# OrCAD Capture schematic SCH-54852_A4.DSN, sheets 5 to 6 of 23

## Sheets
5 C-20 REMOTE DEBUG: size D
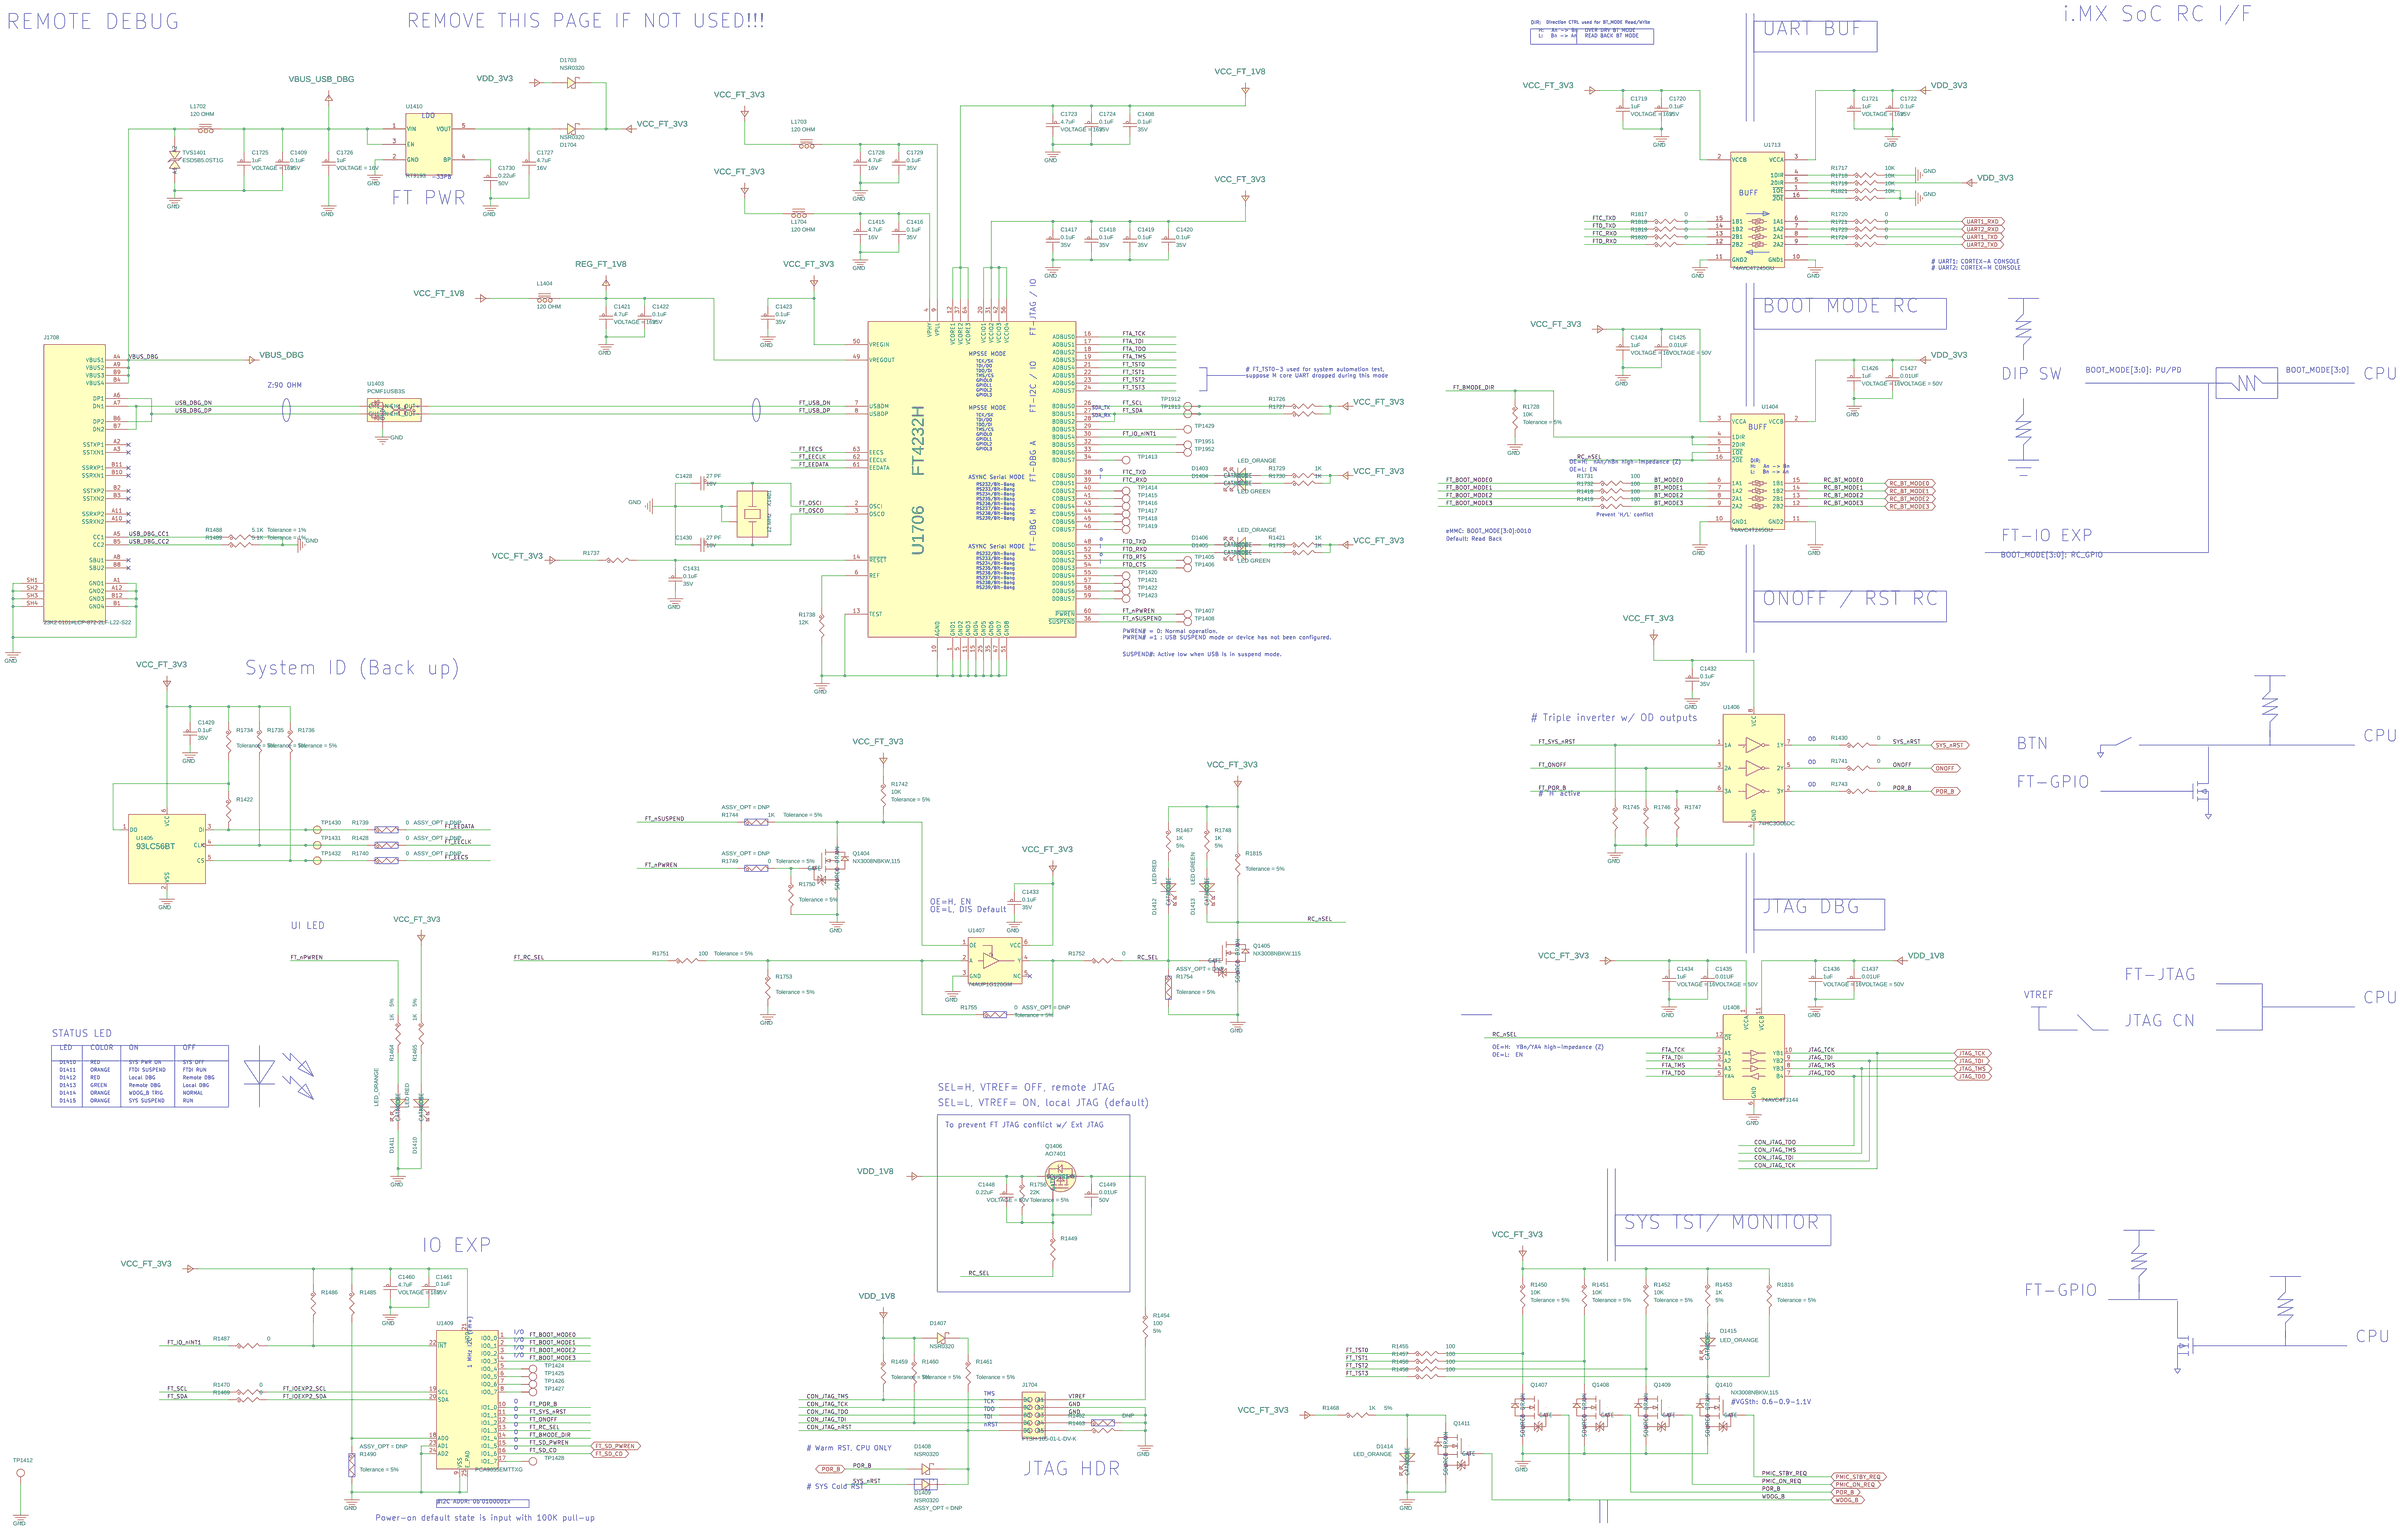
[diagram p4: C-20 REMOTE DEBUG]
6 C-18 CODEC: size C

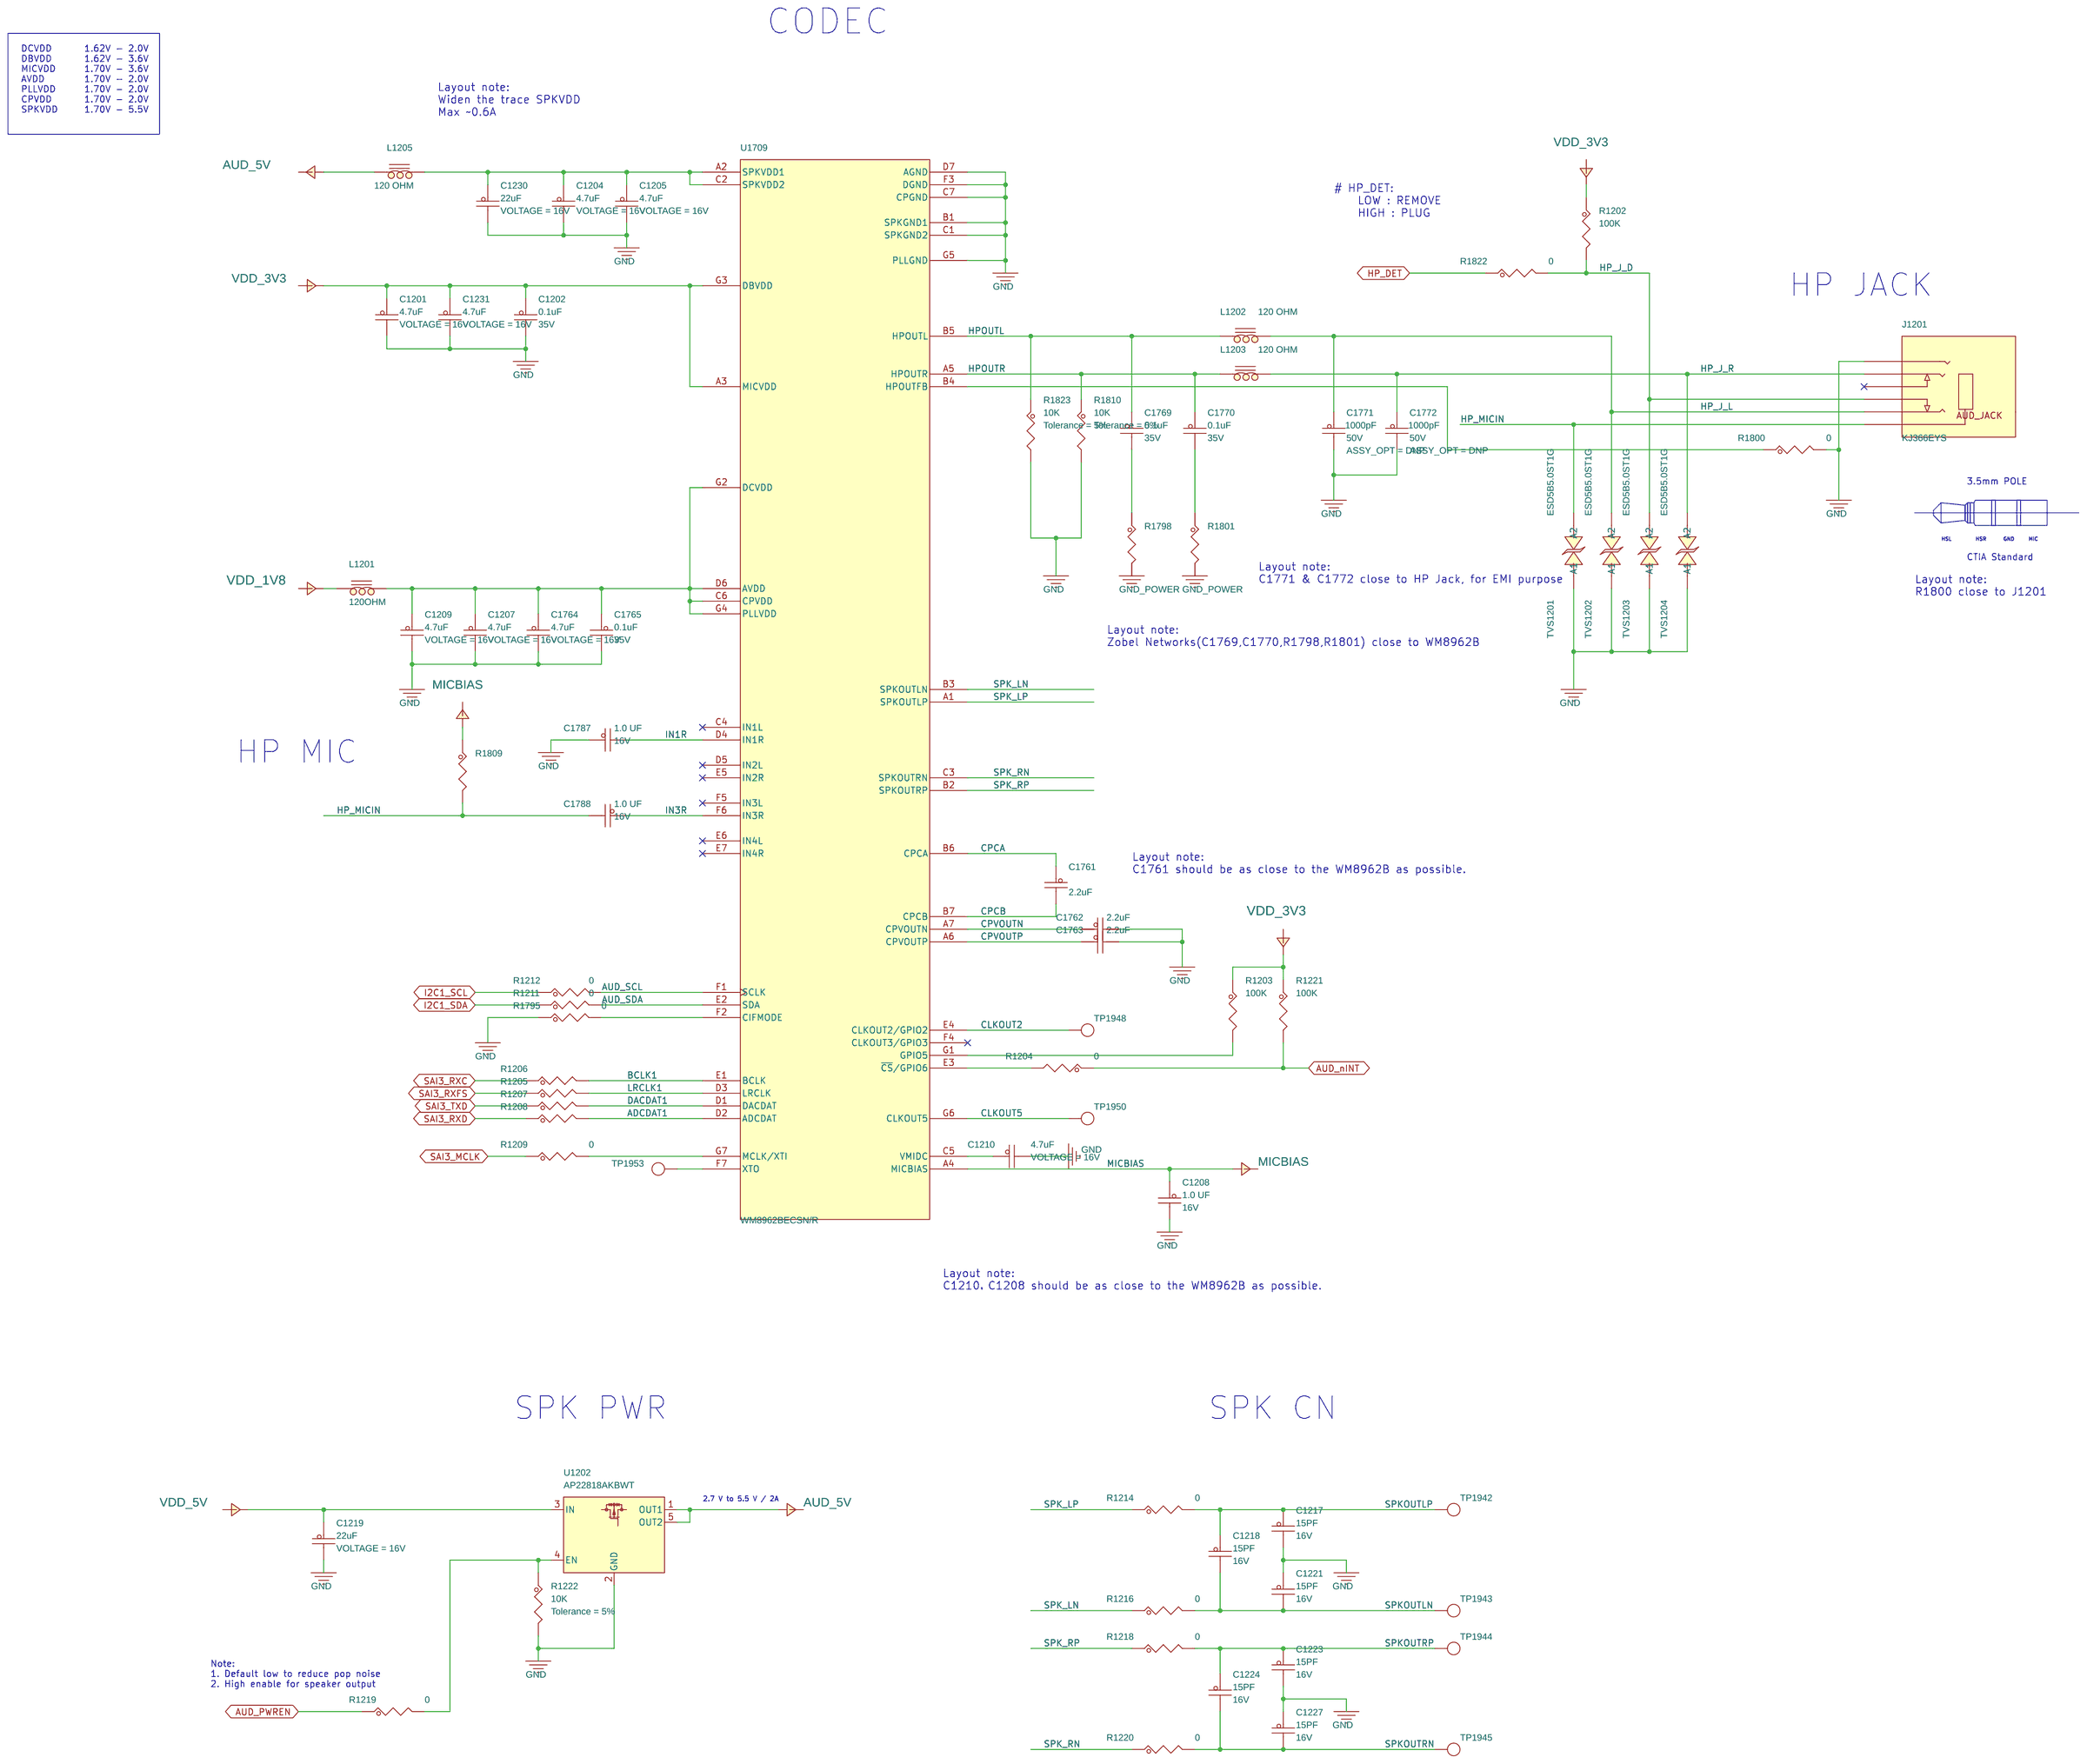
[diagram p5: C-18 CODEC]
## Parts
sheet C-18 CODEC
C1201  4.7uF  [CC0603_OV]
C1202  0.1uF  [CC0402_25]
C1204  4.7uF  [CC0603_OV]
C1205  4.7uF  [CC0603_OV]
C1207  4.7uF  [CC0603_OV]
C1208  1.0 UF  [0603_CC]
C1209  4.7uF  [CC0603_OV]
C1210  4.7uF  [CC0603_OV]
C1217  15PF  [0402_CC]
C1218  15PF  [0402_CC]
C1219  22uF  [CC0805_OV]
C1221  15PF  [0402_CC]
C1223  15PF  [0402_CC]
C1224  15PF  [0402_CC]
C1227  15PF  [0402_CC]
C1230  22uF  [CC0805_OV]
C1231  4.7uF  [CC0603_OV]
C1761  2.2uF  [CC0603_OV]
C1762  2.2uF  [CC0603_OV]
C1763  2.2uF  [CC0603_OV]
C1764  4.7uF  [CC0603_OV]
C1765  0.1uF  [CC0402_25]
C1769  0.1uF  [CC0402_25]
C1770  0.1uF  [CC0402_25]
C1771  1000pF  [0402_CC]
C1772  1000pF  [0402_CC]
C1787  1.0 UF  [0603_CC]
C1788  1.0 UF  [0603_CC]
J1201  KJ366EYS  [con6_audiojack_ra_th]
L1201  120OHM  [0603_CC]
L1202  120 OHM  [IND_0603]
L1203  120 OHM  [IND_0603]
L1205  120 OHM  [IND_0603]
R1202  100K  [0402_CC]
R1203  100K  [0402_CC]
R1204  0  [0402_CC]
R1205  0  [0402_CC]
R1206  0  [0402_CC]
R1207  0  [0402_CC]
R1208  0  [0402_CC]
R1209  0  [0402_CC]
R1211  0  [0402_CC]
R1212  0  [0402_CC]
R1214  0  [0402_CC]
R1216  0  [0402_CC]
R1218  0  [0402_CC]
R1219  0  [0402_CC]
R1220  0  [0402_CC]
R1221  100K  [0402_CC]
R1222  10K  [0402_CC]
R1795  0  [0402_CC]
R1798  20  [0603_CC]
R1800  0  [0402_CC]
R1801  20  [0603_CC]
R1809  2.20K  [0603_CC]
R1810  10K  [0402_CC]
R1822  0  [0402_CC]
R1823  10K  [0402_CC]
TP1942  TPAD_050  [TPAD_050]
TP1943  TPAD_050  [TPAD_050]
TP1944  TPAD_050  [TPAD_050]
TP1945  TPAD_050  [TPAD_050]
TP1948  TPAD_020  [tpad_020]
TP1950  TPAD_020  [tpad_020]
TP1953  TPAD_020  [tpad_020]
TVS1201  ESD5B5.0ST1G  [diode2_sod523]
TVS1202  ESD5B5.0ST1G  [diode2_sod523]
TVS1203  ESD5B5.0ST1G  [diode2_sod523]
TVS1204  ESD5B5.0ST1G  [diode2_sod523]
U1202  AP22818AKBWT  [sot23-5]
U1709  WM8962BECSN/R  [BGA49_0P5_3P62X4]
sheet C-20 REMOTE DEBUG
C1408  0.1uF  [CC0402_25]
C1409  0.1uF  [CC0402_25]
C1415  4.7uF  [CC0603_OV]
C1416  0.1uF  [CC0402_25]
C1417  0.1uF  [CC0402_25]
C1418  0.1uF  [CC0402_25]
C1419  0.1uF  [CC0402_25]
C1420  0.1uF  [CC0402_25]
C1421  4.7uF  [CC0603_OV]
C1422  0.1uF  [CC0402_25]
C1423  0.1uF  [CC0402_25]
C1424  1uF  [CC0402_25]
C1425  0.01UF  [0402_CC]
C1426  1uF  [CC0402_25]
C1427  0.01UF  [0402_CC]
C1428  27 PF  [0402_CC]
C1429  0.1uF  [CC0402_25]
C1430  27 PF  [0402_CC]
C1431  0.1uF  [CC0402_25]
C1432  0.1uF  [CC0402_25]
C1433  0.1uF  [CC0402_25]
C1434  1uF  [CC0402_25]
C1435  0.01UF  [0402_CC]
C1436  1uF  [CC0402_25]
C1437  0.01UF  [0402_CC]
C1448  0.22uF  [0402_CC]
C1449  0.01UF  [0402_CC]
C1460  4.7uF  [CC0603_OV]
C1461  0.1uF  [CC0402_25]
C1719  1uF  [CC0402_25]
C1720  0.1uF  [CC0402_25]
C1721  1uF  [CC0402_25]
C1722  0.1uF  [CC0402_25]
C1723  4.7uF  [CC0603_OV]
C1724  0.1uF  [CC0402_25]
C1725  1uF  [CC0402_25]
C1726  1uF  [CC0402_25]
C1727  4.7uF  [CC0603_OV]
C1728  4.7uF  [CC0603_OV]
C1729  0.1uF  [CC0402_25]
C1730  0.22uF  [0402_CC]
D1403  LED_ORANGE  [led_0603_11mil]
D1404  LED GREEN  [LED_0603]
D1405  LED GREEN  [LED_0603]
D1406  LED_ORANGE  [led_0603_11mil]
D1407  NSR0320  [SOD323]
D1408  NSR0320  [SOD323]
D1409  NSR0320  [SOD323]
D1410  LED RED  [LED_0603]
D1411  LED_ORANGE  [led_0603_11mil]
D1412  LED RED  [LED_0603]
D1413  LED GREEN  [LED_0603]
D1414  LED_ORANGE  [led_0603_11mil]
D1415  LED_ORANGE  [led_0603_11mil]
D1703  NSR0320  [SOD323]
D1704  NSR0320  [SOD323]
J1704  FTSH-105-01-L-DV-K  [hdr205_10m_50_sm_k]
J1708  23K2 0101#LCP-872-2LF-L22-S22  [con24_usb_typec_ra_smt_th_2p2l]
L1404  120 OHM  [IND_0603]
L1702  120 OHM  [IND_0603]
L1703  120 OHM  [IND_0603]
L1704  120 OHM  [IND_0603]
Q1404  NX3008NBKW,115  [sc70_3]
Q1405  NX3008NBKW,115  [sc70_3]
Q1406  AO7401  [sc70_3]
Q1407  NX3008NBKW,115  [sc70_3]
Q1408  NX3008NBKW,115  [sc70_3]
Q1409  NX3008NBKW,115  [sc70_3]
Q1410  NX3008NBKW,115  [sc70_3]
Q1411  NX3008NBKW,115  [sc70_3]
R1418  100  [RC0402_25]
R1419  100  [RC0402_25]
R1421  1K  [0402_CC]
R1422  2.2K  [0402_CC]
R1428  0  [0402_CC]
R1430  0  [0402_CC]
R1449  0  [0402_CC]
R1450  10K  [0402_CC]
R1451  10K  [0402_CC]
R1452  10K  [0402_CC]
R1453  1K  [0402_CC]
R1454  100  [RC0402_25]
R1455  100  [RC0402_25]
R1456  100  [RC0402_25]
R1457  100  [RC0402_25]
R1458  100  [RC0402_25]
R1459  10K  [0402_CC]
R1460  10K  [0402_CC]
R1461  10K  [0402_CC]
R1462  0  [0402_CC]
R1463  0  [0402_CC]
R1464  1K  [0402_CC]
R1465  1K  [0402_CC]
R1467  1K  [0402_CC]
R1468  1K  [0402_CC]
R1469  0  [0402_CC]
R1470  0  [0402_CC]
R1485  10K  [0402_CC]
R1486  10K  [0402_CC]
R1487  0  [0402_CC]
R1488  5.1K  [RC0402_25]
R1489  5.1K  [RC0402_25]
R1490  10K  [0402_CC]
R1717  10K  [0402_CC]
R1718  10K  [0402_CC]
R1719  10K  [0402_CC]
R1720  0  [0402_CC]
R1721  0  [0402_CC]
R1723  0  [0402_CC]
R1724  0  [0402_CC]
R1726  2.2K  [0402_CC]
R1727  2.2K  [0402_CC]
R1728  10K  [0402_CC]
R1729  1K  [0402_CC]
R1730  1K  [0402_CC]
R1731  100  [RC0402_25]
R1732  100  [RC0402_25]
R1733  1K  [0402_CC]
R1734  10K  [0402_CC]
R1735  10K  [0402_CC]
R1736  10K  [0402_CC]
R1737  10K  [0402_CC]
R1738  12K  [0402_CC]
R1739  0  [0402_CC]
R1740  0  [0402_CC]
R1741  0  [0402_CC]
R1742  10K  [0402_CC]
R1743  0  [0402_CC]
R1744  1K  [0402_CC]
R1745  10K  [0402_CC]
R1746  10K  [0402_CC]
R1747  10K  [0402_CC]
R1748  1K  [0402_CC]
R1749  0  [0402_CC]
R1750  10K  [0402_CC]
R1751  100  [RC0402_25]
R1752  0  [0402_CC]
R1753  10K  [0402_CC]
R1754  10K  [0402_CC]
R1755  0  [0402_CC]
R1756  22K  [0402_CC]
R1815  10K  [0402_CC]
R1816  10K  [0402_CC]
R1817  0  [0402_CC]
R1818  0  [0402_CC]
R1819  0  [0402_CC]
R1820  0  [0402_CC]
R1821  10K  [0402_CC]
TP1405  TPAD_020  [tpad_020]
TP1406  TPAD_020  [tpad_020]
TP1407  TPAD_020  [tpad_020]
TP1408  TPAD_020  [tpad_020]
TP1412  TPAD_020  [tpad_020]
TP1413  TPAD_020  [tpad_020]
TP1414  TPAD_020  [tpad_020]
TP1415  TPAD_020  [tpad_020]
TP1416  TPAD_020  [tpad_020]
TP1417  TPAD_020  [tpad_020]
TP1418  TPAD_020  [tpad_020]
TP1419  TPAD_020  [tpad_020]
TP1420  TPAD_020  [tpad_020]
TP1421  TPAD_020  [tpad_020]
TP1422  TPAD_020  [tpad_020]
TP1423  TPAD_020  [tpad_020]
TP1424  TPAD_020  [tpad_020]
TP1425  TPAD_020  [tpad_020]
TP1426  TPAD_020  [tpad_020]
TP1427  TPAD_020  [tpad_020]
TP1428  TPAD_020  [tpad_020]
TP1429  TPAD_020  [tpad_020]
TP1430  TP_35MIL  [testpoint_35mil]
TP1431  TP_35MIL  [testpoint_35mil]
TP1432  TP_35MIL  [testpoint_35mil]
TP1912  TPAD_020  [tpad_020]
TP1913  TPAD_020  [tpad_020]
TP1951  TPAD_020  [tpad_020]
TP1952  TPAD_020  [tpad_020]
TVS1401  ESD5B5.0ST1G  [diode2_sod523]
U1403  PCMF1USB3S  [wlcsp5_0p4_0p82x1p22]
U1404  74AVC4T245GU  [xqfn16_0p4_2p7x1p9]
U1405  93LC56BT  [sot23-6]
U1406  74HC3G06DC  [ssop8_dcu]
U1407  74AUP1G126GM  [udfn6_1x1p5mm]
U1408  74AVC4T3144  [xqfn12_0p4_1p8x2p1]
U1409  PCA9655EMTTXG  [qfn24_4X4_ep2p25mm]
U1410  RT9193  [sot23-5]
U1706  FT4232H  [lqfp64_0p5_10x10]
U1713  74AVC4T245GU  [xqfn16_0p4_2p7x1p9]
X1401  12 MHz  [xtal_4_3p3x2p6mm]

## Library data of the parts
C1201 C1204 C1205 C1207 C1209 C1210 C1231 C1421 C1460 C1723 C1764 = CAP_NP: CAP CER 4.7uF 16V 10% X5R 0603; AGILE_PN: 150-80061; CAD_APPROVED: Yes; FPLIST: CC0603_OV,CC0603,cc0603_0805_nsp,0603_CC_NSP; HEIGHT: 0.95MM; MFG_NAME01: MURATA; MFG_PN01: GRM188R61C475KE11D; ROHS: Yes; Temp Range: -55°C to + 85°C; VOLTAGE: 16V; voltage rating: 6.3V
C1202 C1408 C1409 C1416-C1420 C1422 C1423 C1429 C1431-C1433 C1720 C1722 C1724 C1729 C1765 C1769 C1770 = CAP_NP: CAP CER 0.1UF 35V 10% X5R 0402; AGILE_PN: 150-78506; CAD_APPROVED: Yes; FPLIST: CC0402_25,CC0402_HD,0402_CC,capc0402_l; HEIGHT: 0.55MM; MFG_NAME01: TAIYO YUDEN; MFG_PN01: GMK105BJ104KV-F; ROHS: Yes; Tolerance: 10%; VOLTAGE: 35V
C1208 C1787 C1788 = CAP_NP: CAP CER 1.0UF 16V 10% X7R 0603; AGILE_PN: 150-30028; CAD_APPROVED: Yes; FPLIST: CC0603_OV,CC0603,0603_CC; HEIGHT: 1.0MM; MFG_NAME01: AVX; MFG_PN01: 0603YC105KAT2A; ROHS: Yes; Tolerance: 10%; VOLTAGE: 16V; WVDC: 16V
C1217 C1218 C1221 C1223 C1224 C1227 = CAP_NP: CAP CER 15PF 16V 5% C0G 0402; AGILE_PN: 150-75720; CAD_APPROVED: Yes; FPLIST: CC0402_25,CC0402_HD,0402_CC; HEIGHT: 0.55MM; MFG_NAME01: KEMET; MFG_PN01: C0402C150J4GAC; Package Size: 0402; ROHS: Yes; Tolerance: 5%; VOLTAGE: 16V
C1219 C1230 = CAP_NP: CAP CER 22UF 16V 20% X5R 0805; AGILE_PN: 150-81221; CAD_APPROVED: Yes; FPLIST: CC0805_OV,CC0805,0805_CC; HEIGHT: 1.45MM; MFG_NAME01: TDK Corporation; MFG_PN01: C2012X5R1C226M125AC; ROHS: Yes; Tolerance: 20%; VOLTAGE: 16V
C1761-C1763 = CAP_NP: CAP CER 2.2UF 16V 10% X5R 0603; AGILE_PN: 150-75417; CAD_APPROVED: YES; FPLIST: CC0603_OV,CC0603,0603_CC,cc0603_0402_nsp; HEIGHT: 0.9 MM; MFG_NAME01: CAPAX TECHNOLOGIES INC.; MFG_PN01: 0603B225K160SNT; Package Size: 0603; ROHS: Yes; Tolerance: 10%; VOLTAGE: 16V
C1771 C1772 = CAP_NP: CAP CER 1000PF 50V 5% C0G 0402; AGILE_PN: 150-76334; ASSY_OPT: DNP; CAD_APPROVED: Yes; FPLIST: CC0402_25,CC0402_HD,0402_CC; HEIGHT: 0.55MM; MFG_NAME01: MURATA; MFG_PN01: GRM1555C1H102JA01D; ROHS: Yes; Tolerance: 5%; VOLTAGE: 50V
J1201 = CON_KJ366EYS_AUDIOJACK_6P: CON 6 AUDIO JACK 3.5MM SKT RA SMT -- 177H AU; AGILE_PN: 211-80200; CAD_APPROVED: Yes; HEIGHT: 4.5MM; MFG_NAME01: FODOT ELECTRONICS CO.,LTD.; MFG_PN01: KJ366EYS-00RJ03B; ROHS: Yes; Temp Range: -25 to +85°C; Temp_Range: -25 to +85°C
L1201 = BEAD_0: IND FER BEAD 120OHM@100MHZ 2A 25% 0603; AGILE_PN: 180-30008; CAD_APPROVED: Yes; FPLIST: IND_0603,0603_CC; HEIGHT: 0.95MM; MFG_NAME01: MURATA; MFG_PN01: BLM18PG121SH1; PART_TYPE: FERRITE; PRIORITY_PN: 024-00067; ROHS: Yes; ROOM: RGMII_PHY; Tolerance: 25%
L1202 L1203 L1205 L1404 L1702-L1704 = BEAD_0: IND FER BEAD 120OHM@100MHZ 2A 25% 0603; AGILE_PN: 180-78419; CAD_APPROVED: Yes; FPLIST: IND_0603,0603_CC; HEIGHT: 0.95MM; MFG_NAME01: MURATA; MFG_PN01: BLM18PG121SN1D; ROHS: Yes
R1202 R1203 R1221 = RES: RES MF 100K 1/16W 5% 0402; AGILE_PN: 470-75597; CAD_APPROVED: Yes; FPLIST: RC0402_25,RC0402_HD,0402_CC; HEIGHT: 0.40 MM; MFG_NAME01: VENKEL COMPANY; MFG_PN01: CR0402-16W-104JT; ROHS: Yes; Temp Range: -55C to +155C; Temp_Range: -55C to +155C; Tolerance: 5%; VOLTAGE: 50V
R1204 R1209 R1211 R1212 R1214 R1216 R1218-R1220 R1720 R1721 R1723 R1724 R1795 R1800 R1817-R1820 R1822 = RES: RES MF ZERO OHM 1/16W 5% 0402; AGILE_PN: 470-75394; CAD_APPROVED: Yes; FPLIST: RC0402_25,RC0402_HD,RC0402_X2,0402_CC; HEIGHT: 0.45 MM; MFG_NAME01: ROHM; MFG_PN01: MCR01MZPJ000; ROHS: Yes; Tolerance: 5%; VOLTAGE: 1/16W
R1205-R1208 = RES: RES MF ZERO OHM 1/10W -- 0402; AGILE_PN: 470-79965; CAD_APPROVED: Yes; FPLIST: RC0402_25,RC0402_HD,RC0402_X2,0402_CC; HEIGHT: 0.4MM; MFG_NAME01: Panasonic; MFG_PN01: ERJ-2GE0R00X; ROHS: Yes; SIGNAL_MODEL: DEFAULT_RESISTOR_0.001OHM_2_1
R1222 R1450-R1452 R1459-R1461 R1485 R1486 R1717-R1719 R1728 R1734-R1737 R1742 R1745-R1747 R1750 R1753 R1810 R1815 R1816 R1821 R1823 = RES: RES MF 10K 1/16W 5% 0402; AGILE_PN: 470-75557; CAD_APPROVED: Yes; FPLIST: RC0402_25,RC0402_HD,0402_CC; HEIGHT: 0.4 MM; MFG_NAME01: VISHAY INTERTECHNOLOGY; MFG_PN01: CRCW040210K0JNED; ROHS: Yes; Tolerance: 5%
R1798 R1801 = RES: RES MF 20.0OHM 1/10W 1% 0603; AGILE_PN: 470-75405; CAD_APPROVED: Yes; FPLIST: RC0603_OV,RC0603,0603_CC; HEIGHT: 0.55 MM; MFG_NAME01: KOA SPEER; MFG_PN01: RK73H1JTTD20R0F; ROHS: Yes; SIGNAL_MODEL: DEFAULT_RESISTOR_20OHM_2_1; Tolerance: 1%
R1809 = RES: RES MF 2.20K 1/10W 1% 0603; AGILE_PN: 470-75806; CAD_APPROVED: Yes; FPLIST: RC0603_OV,RC0603,0603_CC; HEIGHT: 0.55 MM; MFG_NAME01: KOA SPEER; MFG_PN01: RK73H1JTTD2201F; ROHS: Yes; SIGNAL_MODEL: DEFAULT_RESISTOR_2200OHM_2_1; Tolerance: 1%
TP1942-TP1945 = TESTLOOP: TEST POINT PAD 50MIL DIA SMT, NO PART TO ORDER; AGILE_PN: 211-76644; ASSY_OPT: DNP; CAD_APPROVED: Yes; HEIGHT: 0.1MM; MFG_NAME01: NOTACOMPONENT; MFG_PN01: NOTACOMPONENT; ROHS: Yes
TP1405-TP1408 TP1412-TP1429 TP1912 TP1913 TP1948 TP1950-TP1953 = TESTLOOP: TEST POINT PAD 0.5MM DIA SMT, NO PART TO ORDER; AGILE_PN: 211-77484; ASSY_OPT: DNP; CAD_APPROVED: Yes; HEIGHT: 0.1MM; ROHS: Yes
TVS1201-TVS1204 TVS1401 = DIODE_TVS_BIDIR: DIODE SUPPRESSOR 16A@30NS 5V@1UA SOD-523; AGILE_PN: 480-76937; CAD_APPROVED: Yes; HEIGHT: 0.7MM; MFG_NAME01: on semiconductor; ROHS: Yes
U1202 = AP22818AKB: IC USB POWER SWITCH 2A 2.7-5.5V TSOT25; 3D_Mechanical_Footprint_File: ftp://fcl.am.freescale.net/ALLEGRO/step/sot23-5.STEP; AGILE_PN: 315-83467; CAD_APPROVED: Yes; HEIGHT: 1MM; MFG_NAME01: DIODES INC; MFG_PN01: AP22818AKBWT-7; ROHS: Yes; Temp Range: -40°C to +85°C; VOLTAGE: 2.7-5.5V
U1709 = WM8962_BGA_49P_CUST: IC AUDIO CODEC 24BIT DAC 2 CH ADC 1.8V BGA49; 3D_Mechanical_Footprint_File: ftp://fcl.am.freescale.net/ALLEGRO/step/BGA49_0P5_3P62X4.STEP; AGILE_PN: 315-80353; CAD_APPROVED: Yes; HEIGHT: 0.75MM; MFG_NAME01: WOLFSON MICROELECTRONICS; ROHS: Yes; VOLTAGE: 1.8V
C1415 C1727 C1728 = CAP_NP: CAP CER 4.7uF 16V 10% X5R 0603; AGILE_PN: 150-80061; CAD_APPROVED: Yes; FPLIST: CC0603_OV,CC0603,cc0603_0805_nsp,0603_CC_NSP; HEIGHT: 0.95MM; MFG_NAME01: MURATA; MFG_PN01: GRM188R61C475KE11D; ROHS: Yes; Temp Range: -55°C to + 85°C; VOLTAGE: 16V
C1424 C1426 C1434 C1436 C1719 C1721 C1726 = CAP_NP: CAP CER 1uF 16V 10% X5R 0402; AGILE_PN: 150-78973; CAD_APPROVED: Yes; FPLIST: CC0402_25,CC0402_HD,0402_CC,capc0402_l; HEIGHT: 0.55 MM; MFG_NAME01: YAGEO; MFG_PN01: CC0402KRX5R7BB105; ROHS: Yes; SIGNAL_MODEL: DEFAULT_CAPACITOR_1e+06pF_2_1; TOL: 10%; Tolerance: 10%; VOLTAGE: 16V; voltage rating: 10V
C1425 C1427 C1435 C1437 = CAP_NP: CAP CER 0.01UF 50V 10% X7R 0402; AGILE_PN: 150-30114; CAD_APPROVED: Yes; FPLIST: CC0402_25,CC0402_HD,0402_CC; HEIGHT: 0.74 MM; MFG_NAME01: KEMET; MFG_PN01: C0402C103K5RAC; ROHS: Yes; Tolerance: 10%; VOLTAGE: 50V
C1428 C1430 = CAP_NP: CAP CER 27PF 16V 5% C0G 0402; AGILE_PN: 150-75267; CAD_APPROVED: Yes; EN: 102-1-02308; FPLIST: CC0402_25,CC0402_HD,0402_CC; HEIGHT: 0.56 MM; MFG_NAME01: AVX; MFG_PN01: 0402YA270JAT2A; PRIORITY_PN: 021-00234; Package Size: 0402; Package Type: Tape & reel; ROHS: Yes; ROOM: RGMII_PHY; SIGNAL_MODEL: DEFAULT_CAPACITOR_22pF_2_1; TOL: 5%; Tolerance: 5%; VOLTAGE: 16V; WVDC: 50V
C1448 = CAP_NP: CAP CER 0.22uF 50V 10% X5R 0402; AGILE_PN: 150-79999; CAD_APPROVED: Yes; FPLIST: CC0402_25,CC0402_HD,0402_CC,capc0402_l; HEIGHT: 0.55MM; MFG_NAME01: TAIYO YUDEN; MFG_PN01: UMK105BJ224KV-F; Package Size: 0402; ROHS: Yes; Temp Range: -55°C to +85°C; Temp_Range: -55°C to +85°C; Tolerance: 10%; VOLTAGE: 50V
C1449 = CAP_NP: CAP CER 0.01UF 50V 10% X7R 0402; AGILE_PN: 150-30114; CAD_APPROVED: Yes; FPLIST: CC0402_25,CC0402_HD,0402_CC,capc0402_l; HEIGHT: 0.55 MM; MFG_NAME01: MURATA; MFG_PN01: GRM155R71H103KA88D; ROHS: Yes; Tolerance: 10%; VOLTAGE: 50V
C1461 = CAP_NP: CAP CER 0.1UF 35V 10% X5R 0402; AGILE_PN: 150-78506; CAD_APPROVED: Yes; FPLIST: CC0402_25,CC0402_HD,0402_CC,capc0402_l; HEIGHT: 0.55MM; MFG_NAME01: TAIYO YUDEN; MFG_PN01: GMK105BJ104KV-F; ROHS: Yes; Temp_Range: -55°C to +125°C; Tolerance: 10%; VOLTAGE: 35V
C1725 = CAP_NP: CAP CER 1uF 16V 10% X5R 0402; AGILE_PN: 150-78973; CAD_APPROVED: Yes; FPLIST: CC0402_25,CC0402_HD,0402_CC,capc0402_l; HEIGHT: 0.55 MM; MFG_NAME01: YAGEO; MFG_PN01: CC0402KRX5R7BB105; ROHS: Yes; Tolerance: 10%; VOLTAGE: 16V
C1730 = CAP_NP: CAP CER 0.22uF 50V 10% X5R 0402; AGILE_PN: 150-79999; CAD_APPROVED: Yes; FPLIST: CC0402_25,CC0402_HD,0402_CC; HEIGHT: 0.55MM; MFG_NAME01: TAIYO YUDEN; MFG_PN01: UMK105BJ224KV-F; Package Size: 0402; ROHS: Yes; Temp Range: -55°C to +85°C; Temp_Range: -55°C to +85°C; Tolerance: 10%; VOLTAGE: 50V
D1403 D1406 D1411 D1414 D1415 = LED: LED OR SGL 20MA 0603; AGILE_PN: 370-76572; CAD_APPROVED: Yes; HEIGHT: 0.28MM; MFG_NAME01: KINGBRIGHT; MFG_PN01: APG1608SEKC/T; ROHS: Yes; Rated Voltage: 2V; Temp Range: -40°C to +85°C; Temp_Range: -40°C to +85°C; VOLTAGE: 2v
D1404 D1405 D1413 = LED: LED GRN SGL 25MA SMT 0603; AGILE_PN: 370-76672; CAD_APPROVED: Yes; HEIGHT: 0.8 MM; MFG_NAME01: DIALIGHT; MFG_PN01: 598-8070-107F; ROHS: Yes; VOLTAGE: 2V
D1407 D1408 D1703 D1704 = DIODE_SCHTKY: DIODE SCH PWR RECT LOW VF 1A 20V SOD323; AGILE_PN: 480-77923; CAD_APPROVED: Yes; HEIGHT: 1.1MM; MFG_NAME01: ON Semiconductor; MFG_PN01: NSR0320MW2T1G; ROHS: Yes
D1409 = DIODE_SCHTKY: DIODE SCH PWR RECT LOW VF 1A 20V SOD323; AGILE_PN: 480-77923; ASSY_OPT: DNP; CAD_APPROVED: Yes; HEIGHT: 1.1MM; MFG_NAME01: ON Semiconductor; MFG_PN01: NSR0320MW2T1G; ROHS: Yes
D1410 D1412 = LED: LED RED SGL 25MA 0603; AGILE_PN: 370-76658; CAD_APPROVED: Yes; HEIGHT: 0.8 MM; MFG_NAME01: DIALIGHT; MFG_PN01: 598-8010-107F; ROHS: Yes
J1704 = CONN_HDR_5X2: HDR 2X5 SMT 50MIL CTR 246H AU; 3D_Mechanical_Footprint_File: ftp://fcl.am.freescale.net/ALLEGRO/step/hdr205_10m_50_sm_k.STEP; AGILE_PN: 211-79478; CAD_APPROVED: Yes; HEIGHT: 6.25MM; MFG_NAME01: SAMTEC; ROHS: Yes
J1708 = USB24_TYPEC_SH4: CON 24 USB TYPE C RA SHLD HYBRID SMT-TH 0.5MM SP 145H AU 87L; AGILE_PN: 211-83409; CAD_APPROVED: Yes; HEIGHT: 3.67MM; MFG_NAME01: ANYTRONIC CORPORATION LIMITED; MFG_PN01: 23K20101#LCP-872-2LF-L22-S22; ROHS: Yes; Temp Range: -55°C to +105°C
Q1404 Q1405 Q1407-Q1411 = NX3008NBKW_SOT323: TRAN NMOS SW 30V 350mA AEC-Q101 SC-70; AGILE_PN: 480-79736; CAD_APPROVED: Yes; HEIGHT: 1.1MM; MFG_NAME01: NEXPERIA; ROHS: Yes
Q1406 = MOSFET_P: TRAN PMOS 20V 1.4A SOT-323; AGILE_PN: 480-79637; CAD_APPROVED: Yes; HEIGHT: 1.1MM; MFG_NAME01: ALPHA AND OMEGA SEMICONDUCTOR; ROHS: Yes
R1418 R1419 R1454-R1458 R1731 R1732 R1751 = RES: RES MF 100 OHM 1/16W 5% 0402; AGILE_PN: 470-82142; CAD_APPROVED: Yes; FPLIST: RC0402_25,RC0402_HD,RC0402_X2,0402_CC; HEIGHT: 0.45MM; MFG_NAME01: SMEC; MFG_PN01: RC73L2Z101JTF; ROHS: Yes; Temp Range: -55°C to +175°C; Tolerance: 5%
R1421 R1453 R1464 R1465 R1467 R1468 R1729 R1730 R1733 R1748 = RES: RES MF 1.0K 1/16W 5% 0402; AGILE_PN: 470-75555; CAD_APPROVED: Yes; FPLIST: RC0402_25,RC0402_HD,RC0402_X2,0402_CC,CAPC0402_L; HEIGHT: 0.41mm; MFG_NAME01: VISHAY INTERTECHNOLOGY; MFG_PN01: CRCW04021K00JNED; ROHS: Yes; Tolerance: 5%
R1422 R1726 R1727 = RES: RES MF 2.2K 1/16W 5% 0402; AGILE_PN: 470-76602; CAD_APPROVED: Yes; FPLIST: RC0402_25,RC0402_HD,0402_CC; HEIGHT: 0.4 MM; MFG_NAME01: YAGEO AMERICA; MFG_PN01: RC0402JR-072K2L; RATING: 1/16W; ROHS: Yes; Tolerance: 5%
R1428 R1739 R1740 R1755 = RES: RES MF ZERO OHM 1/16W 5% 0402; AGILE_PN: 470-75394; ASSY_OPT: DNP; CAD_APPROVED: Yes; FPLIST: RC0402_25,RC0402_HD,RC0402_X2,0402_CC; HEIGHT: 0.45 MM; MFG_NAME01: YAGEO AMERICA; MFG_PN01: RC0402JR-070RL; ROHS: Yes; Tolerance: 5%; VOLTAGE: 1/16W
R1430 R1487 R1741 R1743 R1752 = RES: RES MF ZERO OHM 1/16W 5% 0402; AGILE_PN: 470-75394; CAD_APPROVED: Yes; FPLIST: RC0402_25,RC0402_HD,RC0402_X2,0402_CC; HEIGHT: 0.45 MM; MFG_NAME01: YAGEO AMERICA; MFG_PN01: RC0402JR-070RL; ROHS: Yes; Tolerance: 5%; VOLTAGE: 1/16W
R1449 R1463 = RES: RES MF ZERO OHM 1/16W 5% 0402; AGILE_PN: 470-75394; CAD_APPROVED: Yes; FPLIST: RC0402_25,RC0402_HD,RC0402_X2,0402_CC; HEIGHT: 0.45 MM; MFG_NAME01: ROHM; MFG_PN01: MCR01MZPJ000; ROHS: Yes; SIGNAL_MODEL: DEFAULT_RESISTOR_10000OHM_2_1; TOL: 1%; Tolerance: 5%; VOLTAGE: 1/16W
R1462 = RES: RES MF ZERO OHM 1/16W 5% 0402; AGILE_PN: 470-75394; ASSY_OPT: DNP; CAD_APPROVED: Yes; FPLIST: RC0402_25,RC0402_HD,RC0402_X2,0402_CC; HEIGHT: 0.45 MM; MFG_NAME01: ROHM; MFG_PN01: MCR01MZPJ000; ROHS: Yes; SIGNAL_MODEL: DEFAULT_RESISTOR_10000OHM_2_1; TOL: 1%; Tolerance: 5%; VOLTAGE: 1/16W
R1469 R1470 = RES: RES MF ZERO OHM 1/16W 5% 0402; AGILE_PN: 470-75394; CAD_APPROVED: Yes; FPLIST: RC0402_25,RC0402_HD,RC0402_X2,0402_CC; HEIGHT: 0.45 MM; MFG_NAME01: YAGEO AMERICA; MFG_PN01: RC0402JR-070RL; ROHS: Yes; Temp_Range: -55°C to +155°C; Tolerance: 5%; VOLTAGE: 1/16W
R1488 R1489 = RES: RES MF 5.1K  1/16W 1% 0402; AGILE_PN: 470-30914; CAD_APPROVED: Yes; FPLIST: RC0402_25,RC0402_HD,0402_CC; HEIGHT: 0.40 MM; MFG_NAME01: YAGEO AMERICA; MFG_PN01: RC0402FR-075K1L; ROHS: Yes; Tolerance: 1%
R1490 R1754 = RES: RES MF 10K 1/16W 5% 0402; AGILE_PN: 470-75557; ASSY_OPT: DNP; CAD_APPROVED: Yes; FPLIST: RC0402_25,RC0402_HD,0402_CC; HEIGHT: 0.4 MM; MFG_NAME01: VISHAY INTERTECHNOLOGY; MFG_PN01: CRCW040210K0JNED; ROHS: Yes; Tolerance: 5%
R1738 = RES: RES MF 12K 1/10W 1% AEC-Q200 0402; AGILE_PN: 470-30955; CAD_APPROVED: Yes; EN: 101-1-03373; FPLIST: RC0402_25,RC0402_HD,0402_CC; HEIGHT: 0.40 MM; MFG_NAME01: KOA SPEER; MFG_PN01: RK73H1ETTP1202F; ROHS: Yes; TOL: 1%; Temp Range: -55C to +155C; Tolerance: 1%; VOLTAGE: 50V
R1744 = RES: RES MF 1.0K 1/16W 5% 0402; AGILE_PN: 470-75555; ASSY_OPT: DNP; CAD_APPROVED: Yes; FPLIST: RC0402_25,RC0402_HD,RC0402_X2,0402_CC,CAPC0402_L; HEIGHT: 0.41mm; MFG_NAME01: VISHAY INTERTECHNOLOGY; MFG_PN01: CRCW04021K00JNED; ROHS: Yes; Tolerance: 5%
R1749 = RES: RES MF ZERO OHM 1/16W 5% 0402; AGILE_PN: 470-75394; ASSY_OPT: DNP; CAD_APPROVED: Yes; FPLIST: RC0402_25,RC0402_HD,RC0402_X2,0402_CC; HEIGHT: 0.45 MM; MFG_NAME01: ROHM; MFG_PN01: MCR01MZPJ000; ROHS: Yes; Tolerance: 5%; VOLTAGE: 1/16W
R1756 = RES: RES MF 22K 1/16W 5% 0402; AGILE_PN: 470-75609; CAD_APPROVED: Yes; FPLIST: RC0402_25,RC0402_HD,0402_CC; HEIGHT: 0.41mm; MFG_NAME01: SMEC; MFG_PN01: RC73L2Z223JTF; ROHS: Yes; Tolerance: 5%
TP1430-TP1432 = T_POINT_R: TEST POINT PAD .035 SMT, no part to order; AGILE_PN: 510-75618; CAD_APPROVED: Yes; HEIGHT: 0.1MM; ROHS: Yes
U1403 = PESD1USB30_5P: IC EMI FILTER ESD PROTECTION 15kV/LINE WLCSP5; 3D_Mechanical_Footprint_File: http://fcl.am.freescale.net/ALLEGRO/step/wlcsp5_0p4_0p82x1p22.STEP; AGILE_PN: 315-84061; CAD_APPROVED: Yes; HEIGHT: 0.6MM; MFG_NAME01: NEXPERIA; MFG_PN01: PCMF1USB3SZ; ROHS: Yes
U1404 U1713 = 74AVC4T245GU_XQFN16: IC XCVR VXLTR 4BIT DUAL 0.8-3.6V XQFN16; 3D_Mechanical_Footprint_File: ftp://fcl.am.freescale.net/ALLEGRO/step/xqfn16_0p4_2p7x1p9.STEP; AGILE_PN: 312-82314; CAD_APPROVED: Yes; HEIGHT: 0.5MM; MFG_NAME01: Nexperia; ROHS: Yes; Temp Range: -40°C ~ 125°C
U1405 = 93AA56BT_SOT23-6: IC MEM EEPROM SERIAL 2K 16BIT 2.5-5.5V SOT23-6; AGILE_PN: 334-77717; CAD_APPROVED: Yes; HEIGHT: 1.45MM; MFG_NAME01: MICROCHIP TECHNOLOGY INC; MFG_PN01: 93LC56BT-I/OT; ROHS: Yes; Temp Range: -40C to +85C; VOLTAGE: 2.5-5.5V
U1406 = 74HC3G06DC: IC INV 3CH W/OPEN DRAIN OUT 2.0-6.0V VSSOP8; 3D_Mechanical_Footprint_File: ftp://fcl.am.freescale.net/ALLEGRO/step/ssop8_dcu.STEP; AGILE_PN: 312-83300; CAD_APPROVED: Yes; HEIGHT: 1.0MM; MFG_NAME01: NEXPERIA; ROHS: Yes; Temp Range: -40C to +125C; VOLTAGE: 2.0-6.0V
U1407 = 74AUP1G126GM: IC BUFFER/LINE DRIVER 3STATE 0.8-3.6V XSON6; AGILE_PN: 312-82356; CAD_APPROVED: Yes; HEIGHT: 0.5MM; MFG_NAME01: Nexperia; MFG_PN01: 74AUP1G126GM,115; Package Size: XSON-6; ROHS: Yes; Supply Voltage: 1.8 V, 2.5 V, 3.3 V
U1408 = 74AVC4T3144_12P_A: IC BUF DUAL 4BIT NON-INVERT TS 0.8-3.6V XQFN12; AGILE_PN: 315-82443; CAD_APPROVED: Yes; HEIGHT: 0.5MM; MFG_NAME01: Nexperia; MFG_PN01: 74AVC4T3144GU12X; ROHS: Yes; Supply Voltage: 0.8-3.6V; Temp Range: -40°C to 125°C; VOLTAGE: 0.8-3.6V
U1409 = PCA9655EMTTXG_WQFN24_A: IC I/O EXPANDER 16BIT I2C 1.65-5.5V WQFN24; AGILE_PN: 312-83382; CAD_APPROVED: Yes; HEIGHT: 0.8MM; MFG_NAME01: onsemi; Package Size: 24-WFQFN Exposed Pad; ROHS: Yes; Supply Voltage: 1.65V ~ 5.5V; Temp Range: -55 to +125°C
U1410 = RT9193-33PB: IC VREG LDO 3.3V 300MA SOT-23-5; AGILE_PN: 315-76265; CAD_APPROVED: Yes; HEIGHT: 1.295MM; MFG_NAME01: RICHTEK; ROHS: Yes
U1706 = FT4232HL_LQFP64: IC QUAD USB UART/FIFO 3.3V LQFP64; AGILE_PN: 312-81268; CAD_APPROVED: Yes; EN: 301-0-02252; HEIGHT: 1.6MM; MFG_NAME01: FUTURE TECHNOLOGY DEVICES INTERNATIONAL LTD.; MFG_PN01: FT4232HL-REEL; ROHS: Yes; VOLTAGE: 3-3.6V
X1401 = XTAL_13: XTAL 12Mhz 18pF -- SMD; AGILE_PN: 230-77934; CAD_APPROVED: Yes; EN: 108-1-00213; HEIGHT: 0.8 MM; MFG_NAME01: TXC CORP; MFG_PN01: 7M-12.000MAAJ-T; ROHS: Yes

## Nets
GND: C1201.2 C1202.2 C1204.2 C1205.2 C1207.2 C1208.2 C1209.2 C1210.2 C1217.2 C1219.2 C1221.1 C1223.2 C1227.1 C1230.2 C1231.2 C1408.2 C1409.2 C1415.2 C1416.2 C1417.2 C1418.2 C1419.2 C1420.2 C1421.2 C1422.2 C1423.2 C1424.2 C1425.2 C1426.2 C1427.2 C1428.2 C1429.2 C1430.2 C1431.2 C1432.2 C1433.2 C1434.2 C1435.2 C1436.2 C1437.2 C1460.2 C1461.2 C1719.2 C1720.2 C1721.2 C1722.2 C1723.2 C1724.2 C1725.2 C1726.2 C1727.2 C1728.2 C1729.2 C1730.2 C1762.2 C1763.2 C1764.2 C1765.2 C1771.2 C1772.2 C1787.1 D1410.C(CATHODE) D1411.C(CATHODE) D1414.C(CATHODE) J1201.2 J1704.3(A2) J1704.5(A3) J1708.A1(GND1) J1708.A12(GND2) J1708.B1(GND4) J1708.B12(GND3) J1708.SH1 J1708.SH2 J1708.SH3 J1708.SH4 Q1404.2(SOURCE) Q1405.2(SOURCE) Q1407.2(SOURCE) Q1408.2(SOURCE) Q1409.2(SOURCE) Q1410.2(SOURCE) Q1411.2(SOURCE) R1222.2 R1462.2 R1463.2 R1488.2 R1489.2 R1490.2 R1717.2 R1719.2 R1728.2 R1738.2 R1745.2 R1746.2 R1747.2 R1750.2 R1753.2 R1754.2 R1795.1 R1798.2 R1800.2 R1801.2 R1810.2 R1821.2 R1823.2 TP1412.1(Pin1) TVS1201.1(A1) TVS1202.1(A1) TVS1203.1(A1) TVS1204.1(A1) TVS1401.1(A1) U1202.2(GND) U1403.B1(GND) U1404.10(GND1) U1404.11(GND2) U1405.2(VSS) U1406.4(GND) U1407.3(GND) U1408.6(GND) U1409.9(VSS) U1409.23(AD1) U1409.24(AD2) U1409.25(E_PAD) U1410.2(GND) U1706.1(GND1) U1706.5(GND2) U1706.10(AGND) U1706.11(GND3) U1706.13(TEST) U1706.15(GND4) U1706.25(GND5) U1706.35(GND6) U1706.47(GND7) U1706.51(GND8) U1709.B1(SPKGND1) U1709.C1(SPKGND2) U1709.C7(CPGND) U1709.D7(AGND) U1709.F3(DGND) U1709.G5(PLLGND) U1713.10(GND1) U1713.11(GND2) X1401.2 X1401.4 ; also on sheet 1 4 7 8 9 10 11 12 16 17 18 19 20 21 22 23
VBUS_DBG: J1708.A4(VBUS1) J1708.A9(VBUS2) J1708.B4(VBUS4) J1708.B9(VBUS3) L1702.1 TVS1401.2(A2)
VBUS_USB_DBG: C1409.1 C1725.1 C1726.1 L1702.2 U1410.1(VIN) U1410.3(EN)
VCC_FT_1V8: C1408.1 C1723.1 C1724.1 L1404.1 U1706.12(VCORE1) U1706.37(VCORE2) U1706.64(VCORE3)
VCC_FT_3V3: C1417.1 C1418.1 C1419.1 C1420.1 C1423.1 C1424.1 C1425.1 C1429.1 C1432.1 C1433.1 C1434.1 C1435.1 C1460.1 C1461.1 C1719.1 C1720.1 D1703.C D1704.C L1703.1 L1704.1 R1421.2 R1450.1 R1451.1 R1452.1 R1453.1 R1465.1 R1467.1 R1468.1 R1485.1 R1486.1 R1726.2 R1727.2 R1729.2 R1730.2 R1733.2 R1734.1 R1735.1 R1736.1 R1737.1 R1742.1 R1748.1 R1815.1 R1816.1 U1404.3(VCCA) U1405.6(VCC) U1406.8(VCC) U1407.6(VCC) U1408.1(VCCA) U1409.21(VDD) U1706.20(VCCIO1) U1706.31(VCCIO2) U1706.42(VCCIO3) U1706.50(VREGIN) U1706.56(VCCIO4) U1713.2(VCCB) ; also on sheet 21
VDD_1V8: C1436.1 C1437.1 C1448.1 D1407.A L1201.1 Q1406.2(SOURCE) R1459.1 R1460.1 R1756.1 U1408.11(VCCB) ; also on sheet 7 8 9 12 16 17 18 19 21 23
VDD_3V3: C1201.1 C1202.1 C1231.1 C1426.1 C1427.1 C1721.1 C1722.1 D1703.A R1202.1 R1203.1 R1221.1 R1718.2 U1404.2(VCCB) U1709.A3(MICVDD) U1709.G3(DBVDD) U1713.3(VCCA) ; also on sheet 7 8 9 10 11 12 16 17 19 20 21 22 23
VDD_5V: C1219.1 U1202.3(IN) ; also on sheet 9 10 11 19 22
ADCDAT1: R1208.2 U1709.D2(ADCDAT)
AUD_5V: L1205.1 U1202.1(OUT1) U1202.5(OUT2)
AUD_nINT: R1204.1 R1221.2 ; also on sheet 12
AUD_PWREN: R1219.1 ; also on sheet 12
AUD_SCL: R1212.2 U1709.F1(SCLK)
AUD_SDA: R1211.2 U1709.E2(SDA)
BCLK1: R1206.2 U1709.E1(BCLK)
BT_MODE0: R1731.2 U1404.6(1A1)
BT_MODE1: R1732.2 U1404.7(1A2)
BT_MODE2: R1418.2 U1404.8(2A1)
BT_MODE3: R1419.2 U1404.9(2A2)
CLKOUT2: TP1948.1(Pin1) U1709.E4(CLKOUT2/GPIO2)
CLKOUT5: TP1950.1(Pin1) U1709.G6(CLKOUT5)
CON_JTAG_nRST: D1408.C D1409.C J1704.10(B5) R1461.2
CPCA: C1761.1 U1709.B6(CPCA)
CPCB: C1761.2 U1709.B7(CPCB)
CPVOUTN: C1762.1 U1709.A7(CPVOUTN)
CPVOUTP: C1763.1 U1709.A6(CPVOUTP)
DACDAT1: R1207.2 U1709.D1(DACDAT)
FT_BMODE_DIR: R1728.1 U1404.4(1DIR) U1404.5(2DIR) U1409.14(IO1_4)
FT_BOOT_MODE0: R1731.1 U1409.1(IO0_0)
FT_BOOT_MODE1: R1732.1 U1409.2(IO0_1)
FT_BOOT_MODE2: R1418.1 U1409.3(IO0_2)
FT_BOOT_MODE3: R1419.1 U1409.4(IO0_3)
FT_EECLK: R1428.2 U1706.62(EECLK)
FT_EECS: R1740.2 U1706.63(EECS)
FT_EEDATA: R1739.2 U1706.61(EEDATA)
FT_IO_nINT1: R1487.1 U1706.30(BDBUS4)
FT_IOEXP2_SCL: R1470.2 U1409.19(SCL)
FT_IOEXP2_SDA: R1469.2 U1409.20(SDA)
FT_nPWREN: R1464.1 R1749.1 TP1407.1(Pin1) U1706.60(~{PWREN})
FT_nSUSPEND: R1744.1 TP1408.1(Pin1) U1706.36(~{SUSPEND})
FT_ONOFF: R1746.1 U1406.3(2A) U1409.12(IO1_2)
FT_OSCI: C1428.1 U1706.2(OSCI) X1401.1
FT_OSCO: C1430.1 U1706.3(OSCO) X1401.3
FT_POR_B: R1747.1 U1406.6(3A) U1409.10(IO1_0)
FT_RC_SEL: R1751.1 U1409.13(IO1_3)
FT_SCL: R1470.1 R1726.1 TP1912.1(Pin1) U1706.26(BDBUS0)
FT_SD_CD: U1409.16(IO1_6) ; also on sheet 21
FT_SD_PWREN: U1409.15(IO1_5) ; also on sheet 21
FT_SDA: R1469.1 R1727.1 TP1913.1(Pin1) U1706.27(BDBUS1) U1706.28(BDBUS2)
FT_SYS_nRST: R1745.1 U1406.1(1A) U1409.11(IO1_1)
FT_TST0: R1455.1 U1706.21(ADBUS4)
FT_TST1: R1457.1 U1706.22(ADBUS5)
FT_TST2: R1456.1 U1706.23(ADBUS6)
FT_TST3: R1458.1 U1706.24(ADBUS7)
FT_USB_DN: U1403.C1(CH1_OUT+) U1706.7(USBDM)
FT_USB_DP: U1403.C2(CH1_OUT-) U1706.8(USBDP)
FTA_TCK: U1408.2(A1) U1706.16(ADBUS0)
FTA_TDI: U1408.3(A2) U1706.17(ADBUS1)
FTA_TDO: U1408.5(YA4) U1706.18(ADBUS2)
FTA_TMS: U1408.4(A3) U1706.19(ADBUS3)
FTC_RXD: D1404.C(CATHODE) R1819.1 U1706.39(CDBUS1)
FTC_TXD: D1403.C(CATHODE) R1817.1 U1706.38(CDBUS0)
FTD_CTS: TP1406.1(Pin1) U1706.54(DDBUS3)
FTD_RTS: TP1405.1(Pin1) U1706.53(DDBUS2)
FTD_RXD: D1405.C(CATHODE) R1820.1 U1706.52(DDBUS1)
FTD_TXD: D1406.C(CATHODE) R1818.1 U1706.48(DDBUS0)
HP_DET: R1822.1 ; also on sheet 12
HP_J_D: J1201.5 R1202.2 R1822.2 TVS1203.2(A2)
HP_J_L: C1771.1 J1201.4 L1202.2 TVS1202.2(A2)
HP_J_R: C1772.1 J1201.3 L1203.2 TVS1204.2(A2)
HP_MICIN: C1788.2 J1201.1 R1809.2 TVS1201.2(A2)
HPOUTL: C1769.1 L1202.1 R1823.1 U1709.B5(HPOUTL)
HPOUTR: C1770.1 L1203.1 R1810.1 U1709.A5(HPOUTR)
I2C1_SCL: R1212.1 ; also on sheet 7 10 12 17 19 20
I2C1_SDA: R1211.1 ; also on sheet 7 10 12 17 19 20
IN1R: C1787.2 U1709.D4(IN1R)
IN3R: C1788.1 U1709.F6(IN3R)
JTAG_TCK: J1704.4(B2) U1408.10(YB1) ; also on sheet 1
JTAG_TDI: J1704.8(B4) R1460.2 U1408.9(YB2) ; also on sheet 1
JTAG_TDO: J1704.6(B3) U1408.7(B4) ; also on sheet 1
JTAG_TMS: J1704.2(B1) R1459.2 U1408.8(YB3) ; also on sheet 1
LRCLK1: R1205.2 U1709.D3(LRCLK)
MICBIAS: C1208.1 R1809.1 U1709.A4(MICBIAS)
ONOFF: R1741.2 ; also on sheet 1 19
PMIC_ON_REQ: Q1409.1(GATE) ; also on sheet 1 11 17
PMIC_STBY_REQ: Q1410.1(GATE) ; also on sheet 1 17
POR_B: D1408.A Q1408.1(GATE) R1743.2 ; also on sheet 1 12 17
RC_BT_MODE0: U1404.15(1B1) ; also on sheet 23
RC_BT_MODE1: U1404.14(1B2) ; also on sheet 23
RC_BT_MODE2: U1404.13(2B1) ; also on sheet 23
RC_BT_MODE3: U1404.12(2B2) ; also on sheet 23
RC_nSEL: D1413.C(CATHODE) Q1405.3(DRAIN) R1815.2 U1404.1(~{1OE}) U1404.16(~{2OE}) U1408.12(~{OE})
RC_SEL: D1412.C(CATHODE) Q1405.1(GATE) R1449.2 R1752.2 R1754.1
REG_FT_1V8: C1421.1 C1422.1 L1404.2 U1706.49(VREGOUT)
SAI3_MCLK: R1209.1 ; also on sheet 12
SAI3_RXC: R1206.1 ; also on sheet 12
SAI3_RXD: R1208.1 ; also on sheet 12
SAI3_RXFS: R1205.1 ; also on sheet 12
SAI3_TXD: R1207.1 ; also on sheet 12
SPK_LN: R1216.1 U1709.B3(SPKOUTLN)
SPK_LP: R1214.1 U1709.A1(SPKOUTLP)
SPK_RN: R1220.1 U1709.C3(SPKOUTRN)
SPK_RP: R1218.1 U1709.B2(SPKOUTRP)
SPKOUTLN: C1218.2 C1221.2 R1216.2 TP1943.1(Pin1)
SPKOUTLP: C1217.1 C1218.1 R1214.2 TP1942.1(Pin1)
SPKOUTRN: C1224.2 C1227.2 R1220.2 TP1945.1(Pin1)
SPKOUTRP: C1223.1 C1224.1 R1218.2 TP1944.1(Pin1)
SYS_nRST: D1409.A R1430.2 ; also on sheet 17 19 22
UART1_RXD: R1720.2 ; also on sheet 20 22
UART1_TXD: R1723.2 ; also on sheet 20 22 23
UART2_RXD: R1721.2 ; also on sheet 20 22
UART2_TXD: R1724.2 ; also on sheet 20 22 23
USB_DBG_CC1: J1708.A5(CC1) R1488.1
USB_DBG_CC2: J1708.B5(CC2) R1489.1
USB_DBG_DN: J1708.A7(DN1) J1708.B7(DN2) U1403.A1(CH1_IN+)
USB_DBG_DP: J1708.A6(DP1) J1708.B6(DP2) U1403.A2(CH1_IN-)
VTREF: J1704.1(A1) R1454.2
WDOG_B: Q1407.1(GATE) Q1411.1(GATE) ; also on sheet 17 20
N115646354: C1727.1 D1704.A U1410.5(VOUT)
N115646421: C1728.1 C1729.1 L1703.2 U1706.9(VPLL)
N115646547: C1730.1 U1410.4(BP)
N115646842: C1415.1 C1416.1 L1704.2 U1706.4(VPHY)
N115647748: TP1429.1(Pin1) U1706.29(BDBUS3)
N115647777: TP1951.1(Pin1) U1706.32(BDBUS5)
N115647791: TP1952.1(Pin1) U1706.33(BDBUS6)
N115647810: TP1413.1(Pin1) U1706.34(BDBUS7)
N115647904: D1403.A(ANODE) R1729.1
N115647959: D1404.A(ANODE) R1730.1
N115647999: TP1414.1(Pin1) U1706.40(CDBUS2)
N115648034: TP1415.1(Pin1) U1706.41(CDBUS3)
N115648083: TP1416.1(Pin1) U1706.43(CDBUS4)
N115648105: TP1417.1(Pin1) U1706.44(CDBUS5)
N115648131: TP1418.1(Pin1) U1706.45(CDBUS6)
N115648181: TP1419.1(Pin1) U1706.46(CDBUS7)
N115648263: D1406.A(ANODE) R1421.1
N115648354: D1405.A(ANODE) R1733.1
N115648363: C1431.1 R1737.2 U1706.14(~{RESET})
N115648415: R1738.1 U1706.6(REF)
N115648419: TP1420.1(Pin1) U1706.55(DDBUS4)
N115648439: R1422.1 R1734.2 U1405.1(DO)
N115648441: R1428.1 R1735.2 TP1431.1(TP) U1405.4(CLK)
N115648443: R1736.2 R1740.1 TP1432.1(TP) U1405.5(CS)
N115648445: TP1421.1(Pin1) U1706.57(DDBUS5)
N115648473: TP1422.1(Pin1) U1706.58(DDBUS6)
N115648499: TP1423.1(Pin1) U1706.59(DDBUS7)
N115648584: R1422.2 R1739.1 TP1430.1(TP) U1405.3(DI)
N115648905: R1430.1 U1406.7(1Y)
N115648976: R1741.1 U1406.5(2Y)
N115649042: R1743.1 U1406.2(3Y)
N115649073: Q1404.3(DRAIN) R1742.2 R1744.2 U1407.1(OE)
N115649242: D1412.A(ANODE) R1467.2
N115649244: D1413.A(ANODE) R1748.2
N115649263: Q1404.1(GATE) R1749.2 R1750.1
N115649426: D1411.A(ANODE) R1464.2
N115649428: D1410.A(ANODE) R1465.2
N115649511: R1751.2 R1753.1 R1755.1 U1407.2(A)
N115649521: R1752.1 R1755.2 U1407.4(Y)
N115650186: R1486.2 R1487.2 U1409.22(~{INT})
N115650188: R1485.2 R1490.1 U1409.18(AD0)
N115650272: TP1424.1(Pin1) U1409.5(IO0_4)
N115650294: TP1425.1(Pin1) U1409.6(IO0_5)
N115650321: TP1426.1(Pin1) U1409.7(IO0_6)
N115650337: C1449.1 Q1406.3(DRAIN) R1454.1
N115650366: TP1427.1(Pin1) U1409.8(IO0_7)
N115650410: C1448.2 C1449.2 Q1406.1(GATE) R1449.1 R1756.2
N115650590: TP1428.1(Pin1) U1409.17(IO1_7)
N115650809: Q1407.3(DRAIN) R1450.2 R1455.2
N115650811: Q1408.3(DRAIN) R1451.2 R1457.2
N115650813: Q1409.3(DRAIN) R1452.2 R1456.2
N115650815: D1415.A(ANODE) R1453.2
N115650891: D1407.C R1461.1
N115651044: D1415.C(CATHODE) Q1410.3(DRAIN) R1458.2 R1816.2
N115651255: D1414.A(ANODE) Q1411.3(DRAIN) R1468.2
N115651302: J1704.7(A4) R1462.1
N115651381: J1704.9(A5) R1463.1
N115756645: R1204.2 U1709.E3(~{CS}/GPIO6)
N115756807: R1209.2 U1709.G7(MCLK/XTI)
N115757278: R1219.2 R1222.1 U1202.4(EN)
N115865392: R1795.2 U1709.F2(CIFMODE)
N115871876: R1203.2 U1709.G1(GPIO5)
N115938225: C1204.1 C1205.1 C1230.1 L1205.2 U1709.A2(SPKVDD1) U1709.C2(SPKVDD2)
N115938370: R1800.1 U1709.B4(HPOUTFB)
N115938505: C1207.1 C1209.1 C1764.1 C1765.1 L1201.2 U1709.C6(CPVDD) U1709.D6(AVDD) U1709.G2(DCVDD) U1709.G4(PLLVDD)
N115954867: C1769.2 R1798.1
N115954870: C1770.2 R1801.1
N115959933: C1210.1 U1709.C5(VMIDC)
N116057568: TP1953.1(Pin1) U1709.F7(XTO)
N116084647: R1718.1 U1713.5(2DIR)
N116084649: R1723.1 U1713.8(2A1)
N116084651: R1717.1 U1713.4(1DIR)
N116084659: R1724.1 U1713.9(2A2)
N116084661: R1719.1 U1713.1(~{1OE})
N116086427: R1817.2 U1713.15(1B1)
N116086430: R1818.2 U1713.14(1B2)
N116086433: R1819.2 U1713.13(2B1)
N116086500: R1820.2 U1713.12(2B2)
N116087925: R1821.1 U1713.16(~{2OE})
N116088365: R1720.1 U1713.6(1A1)
N116088374: R1721.1 U1713.7(1A2)

Not connected (* = marked no-connect by the designer): J1201 6*; J1708 A2(SSTXP1)* A3(SSTXN1)* A8(SBU1)* A10(SSRXN2)* A11(SSRXP2)* B2(SSTXP2)* B3(SSTXN2)* B8(SBU2)* B10(SSRXN1)* B11(SSRXP1)*; U1407 5(NC)*; U1709 C4(IN1L)* D5(IN2L)* E5(IN2R)* E6(IN4L)* E7(IN4R)* F4(CLKOUT3/GPIO3)* F5(IN3L)*

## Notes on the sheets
sheet 5
- i.MX SoC RC I/F
- REMOTE DEBUG
- REMOVE THIS PAGE IF NOT USED!!!
- DIR:
- H:   An -> Bn
  L:   Bn -> An
- Direction CTRL used for BT_MODE Read/Write
- OVER DRV BT MODE
  READ BACK BT MODE
- UART BUF
- LDO
- -33PB
- FT PWR
- BUFF
- # UART1: CORTEX-A CONSOLE
  # UART2: CORTEX-M CONSOLE
- BOOT MODE RC
- FT-JTAG / IO
- MPSSE MODE
- TCK/SK
  TDI/DO
  TDO/DI
  TMS/CS
  GPIOL0
  GPIOL1
  GPIOL2
  GPIOL3
- # FT_TST0-3 used for system automation test,
  suppose M core UART dropped during this mode
- DIP SW
- BOOT_MODE[3:0]: PU/PD
- BOOT_MODE[3:0]
- CPU
- Z:90 OHM
- MPSSE MODE
- SDA_TX
- TCK/SK
  TDI/DO
  TDO/DI
  TMS/CS
  GPIOL0
  GPIOL1
  GPIOL2
  GPIOL3
- FT-I2C / IO
- SDA_RX
- BUFF
- OE=H:  nAn/nBn high-impedance (Z)
- DIR:
  H:   An -> Bn
  L:   Bn -> An
- o
- OE=L: EN
- ASYNC Serial MODE
- RS232/Bit-Bang
  RS233/Bit-Bang
  RS234/Bit-Bang
  RS235/Bit-Bang
  RS236/Bit-Bang
  RS237/Bit-Bang
  RS238/Bit-Bang
  RS239/Bit-Bang
- FT-DBG A
- i
- Prevent 'H/L' confilct
- o
- Default: Read Back
- eMMC: BOOT_MODE[3:0]:0010
- FT-IO EXP
- ASYNC Serial MODE
- i
- RS232/Bit-Bang
  RS233/Bit-Bang
  RS234/Bit-Bang
  RS235/Bit-Bang
  RS236/Bit-Bang
  RS237/Bit-Bang
  RS238/Bit-Bang
  RS239/Bit-Bang
- FT-DBG M
- o
- BOOT_MODE[3:0]: RC_GPIO
- i
- ONOFF / RST RC
- PWREN# = 0: Normal operation.
  PWREN# =1 : USB SUSPEND mode or device has not been configured.
- SUSPEND#: Active low when USB is in suspend mode.
- System ID (Back up)
- # Triple inverter w/ OD outputs
- OD
- BTN
- CPU
- OD
- OD
- FT-GPIO
- # 'H' active
- OE=H, EN
- JTAG DBG
- OE=L, DIS Default
- UI LED
- FT-JTAG
- VTREF
- CPU
- JTAG CN
- STATUS LED
- LED
- COLOR
- ON
- OFF
- OE=H:  YBn/YA4 high-impedance (Z)
- OE=L:  EN
- D1410
- RED
- SYS PWR ON
- SYS OFF
- D1411
- ORANGE
- FTDI SUSPEND
- FTDI RUN
- D1412
- D1413
- GREEN
- RED
- Local DBG
- Remote DBG
- Local DBG
- Remote DBG
- SEL=H, VTREF= OFF, remote JTAG
- D1414
- ORANGE
- WDOG_B TRIG
- NORMAL
- D1415
- ORANGE
- SYS SUSPEND
- RUN
- SEL=L, VTREF= ON, local JTAG (default)
- To prevent FT JTAG conflict w/ Ext JTAG
- SYS TST/ MONITOR
- IO EXP
- FT-GPIO
- I/O
- I/O
- CPU
- I/O
- I/O
- 1 MHz I2C (Fm+)
- TMS
- O
- TCK
- #VGSth: 0.6-0.9-1.1V
- O
- TDO
- O
- TDI
- O
- nRST
- O
- O
- O
- # Warm RST, CPU ONLY
- JTAG HDR
- # SYS Cold RST
- #I2C ADDR: 0b'0100001x
- Power-on default state is input with 100K pull-up
sheet 6
- CODEC
- DCVDD
  DBVDD
  MICVDD
  AVDD
  PLLVDD
  CPVDD
  SPKVDD
- 1.62V - 2.0V
  1.62V - 3.6V
  1.70V - 3.6V
  1.70V - 2.0V
  1.70V - 2.0V
  1.70V - 2.0V
  1.70V - 5.5V
- Layout note:
  Widen the trace SPKVDD
  Max ~0.6A
- # HP_DET:
      LOW : REMOVE
      HIGH : PLUG
- HP JACK
- 3.5mm POLE
- HSL
- HSR
- GND
- MIC
- Layout note:
  C1771 & C1772 close to HP Jack, for EMI purpose
- CTIA Standard
- Layout note:
  R1800 close to J1201
- Layout note:
  Zobel Networks(C1769,C1770,R1798,R1801) close to WM8962B
- HP MIC
- Layout note:
  C1761 should be as close to the WM8962B as possible.
- Layout note:
  C1210，C1208 should be as close to the WM8962B as possible.
- SPK PWR
- SPK CN
- 2.7 V to 5.5 V / 2A
- Note:
  1. Default low to reduce pop noise
  2. High enable for speaker output
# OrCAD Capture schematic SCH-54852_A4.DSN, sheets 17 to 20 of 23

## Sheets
17 C-09 PMIC: size C
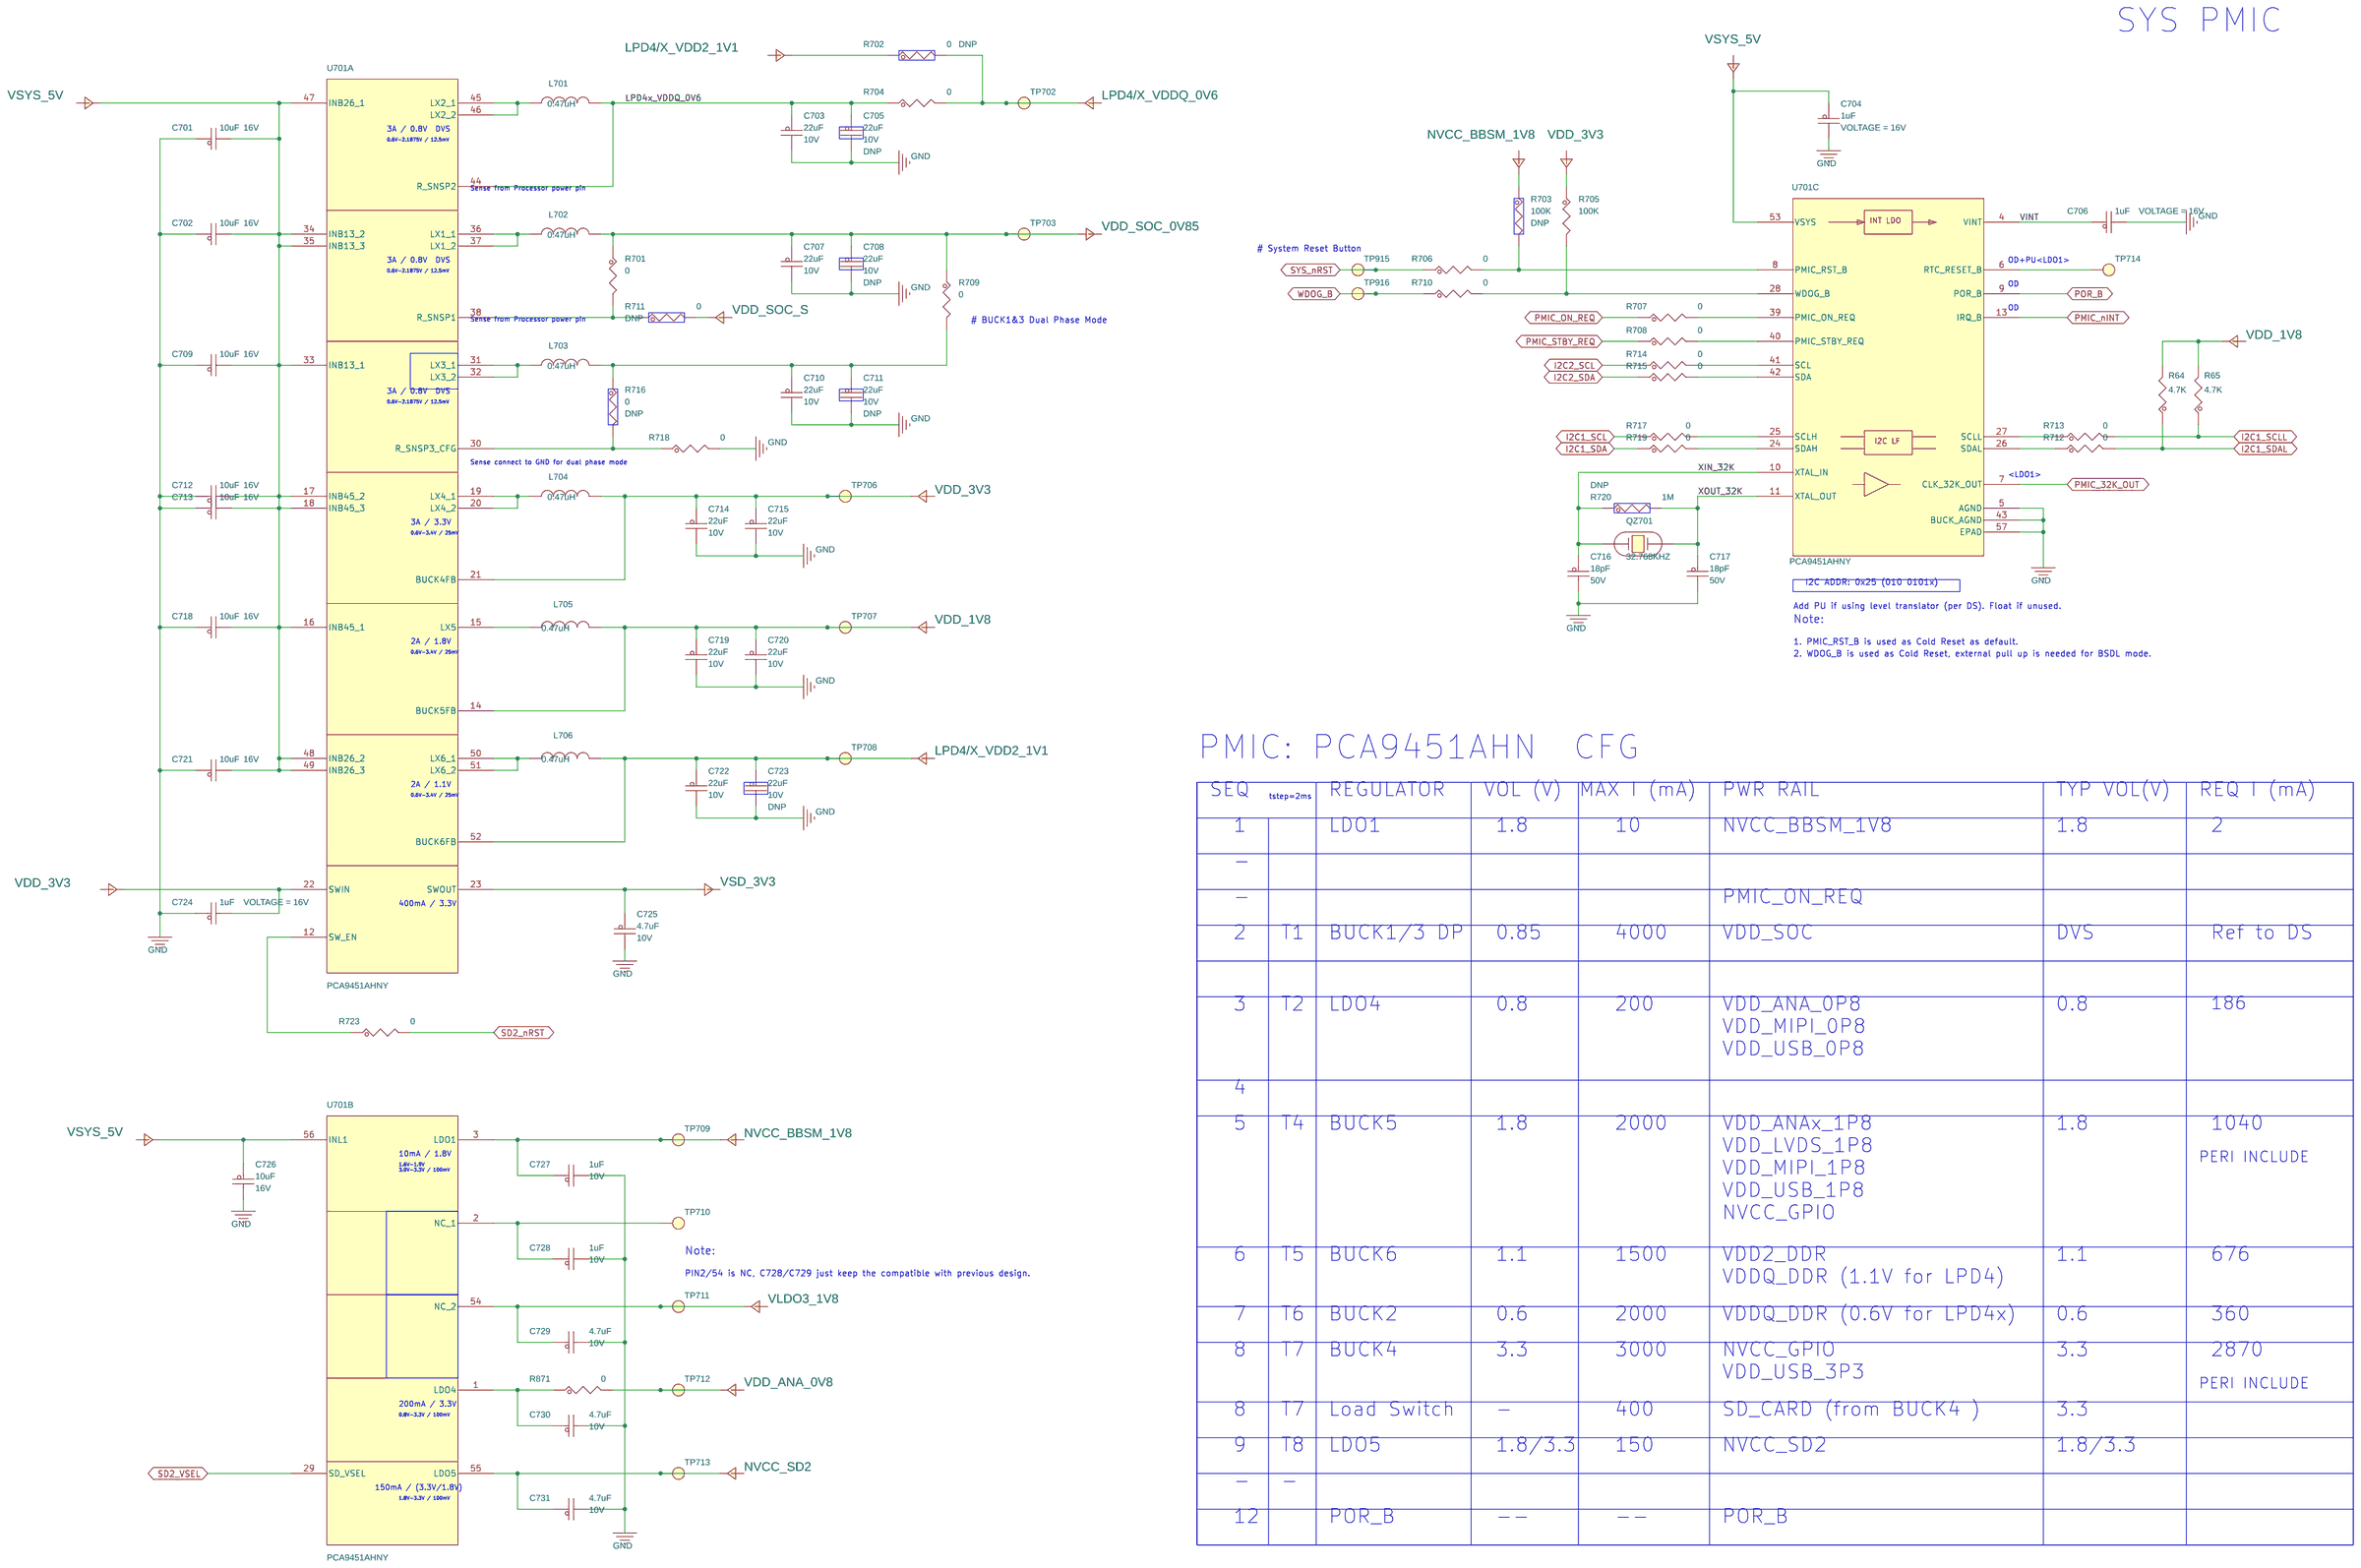
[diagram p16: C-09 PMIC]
18 C-05 LPDDR4/x: size C
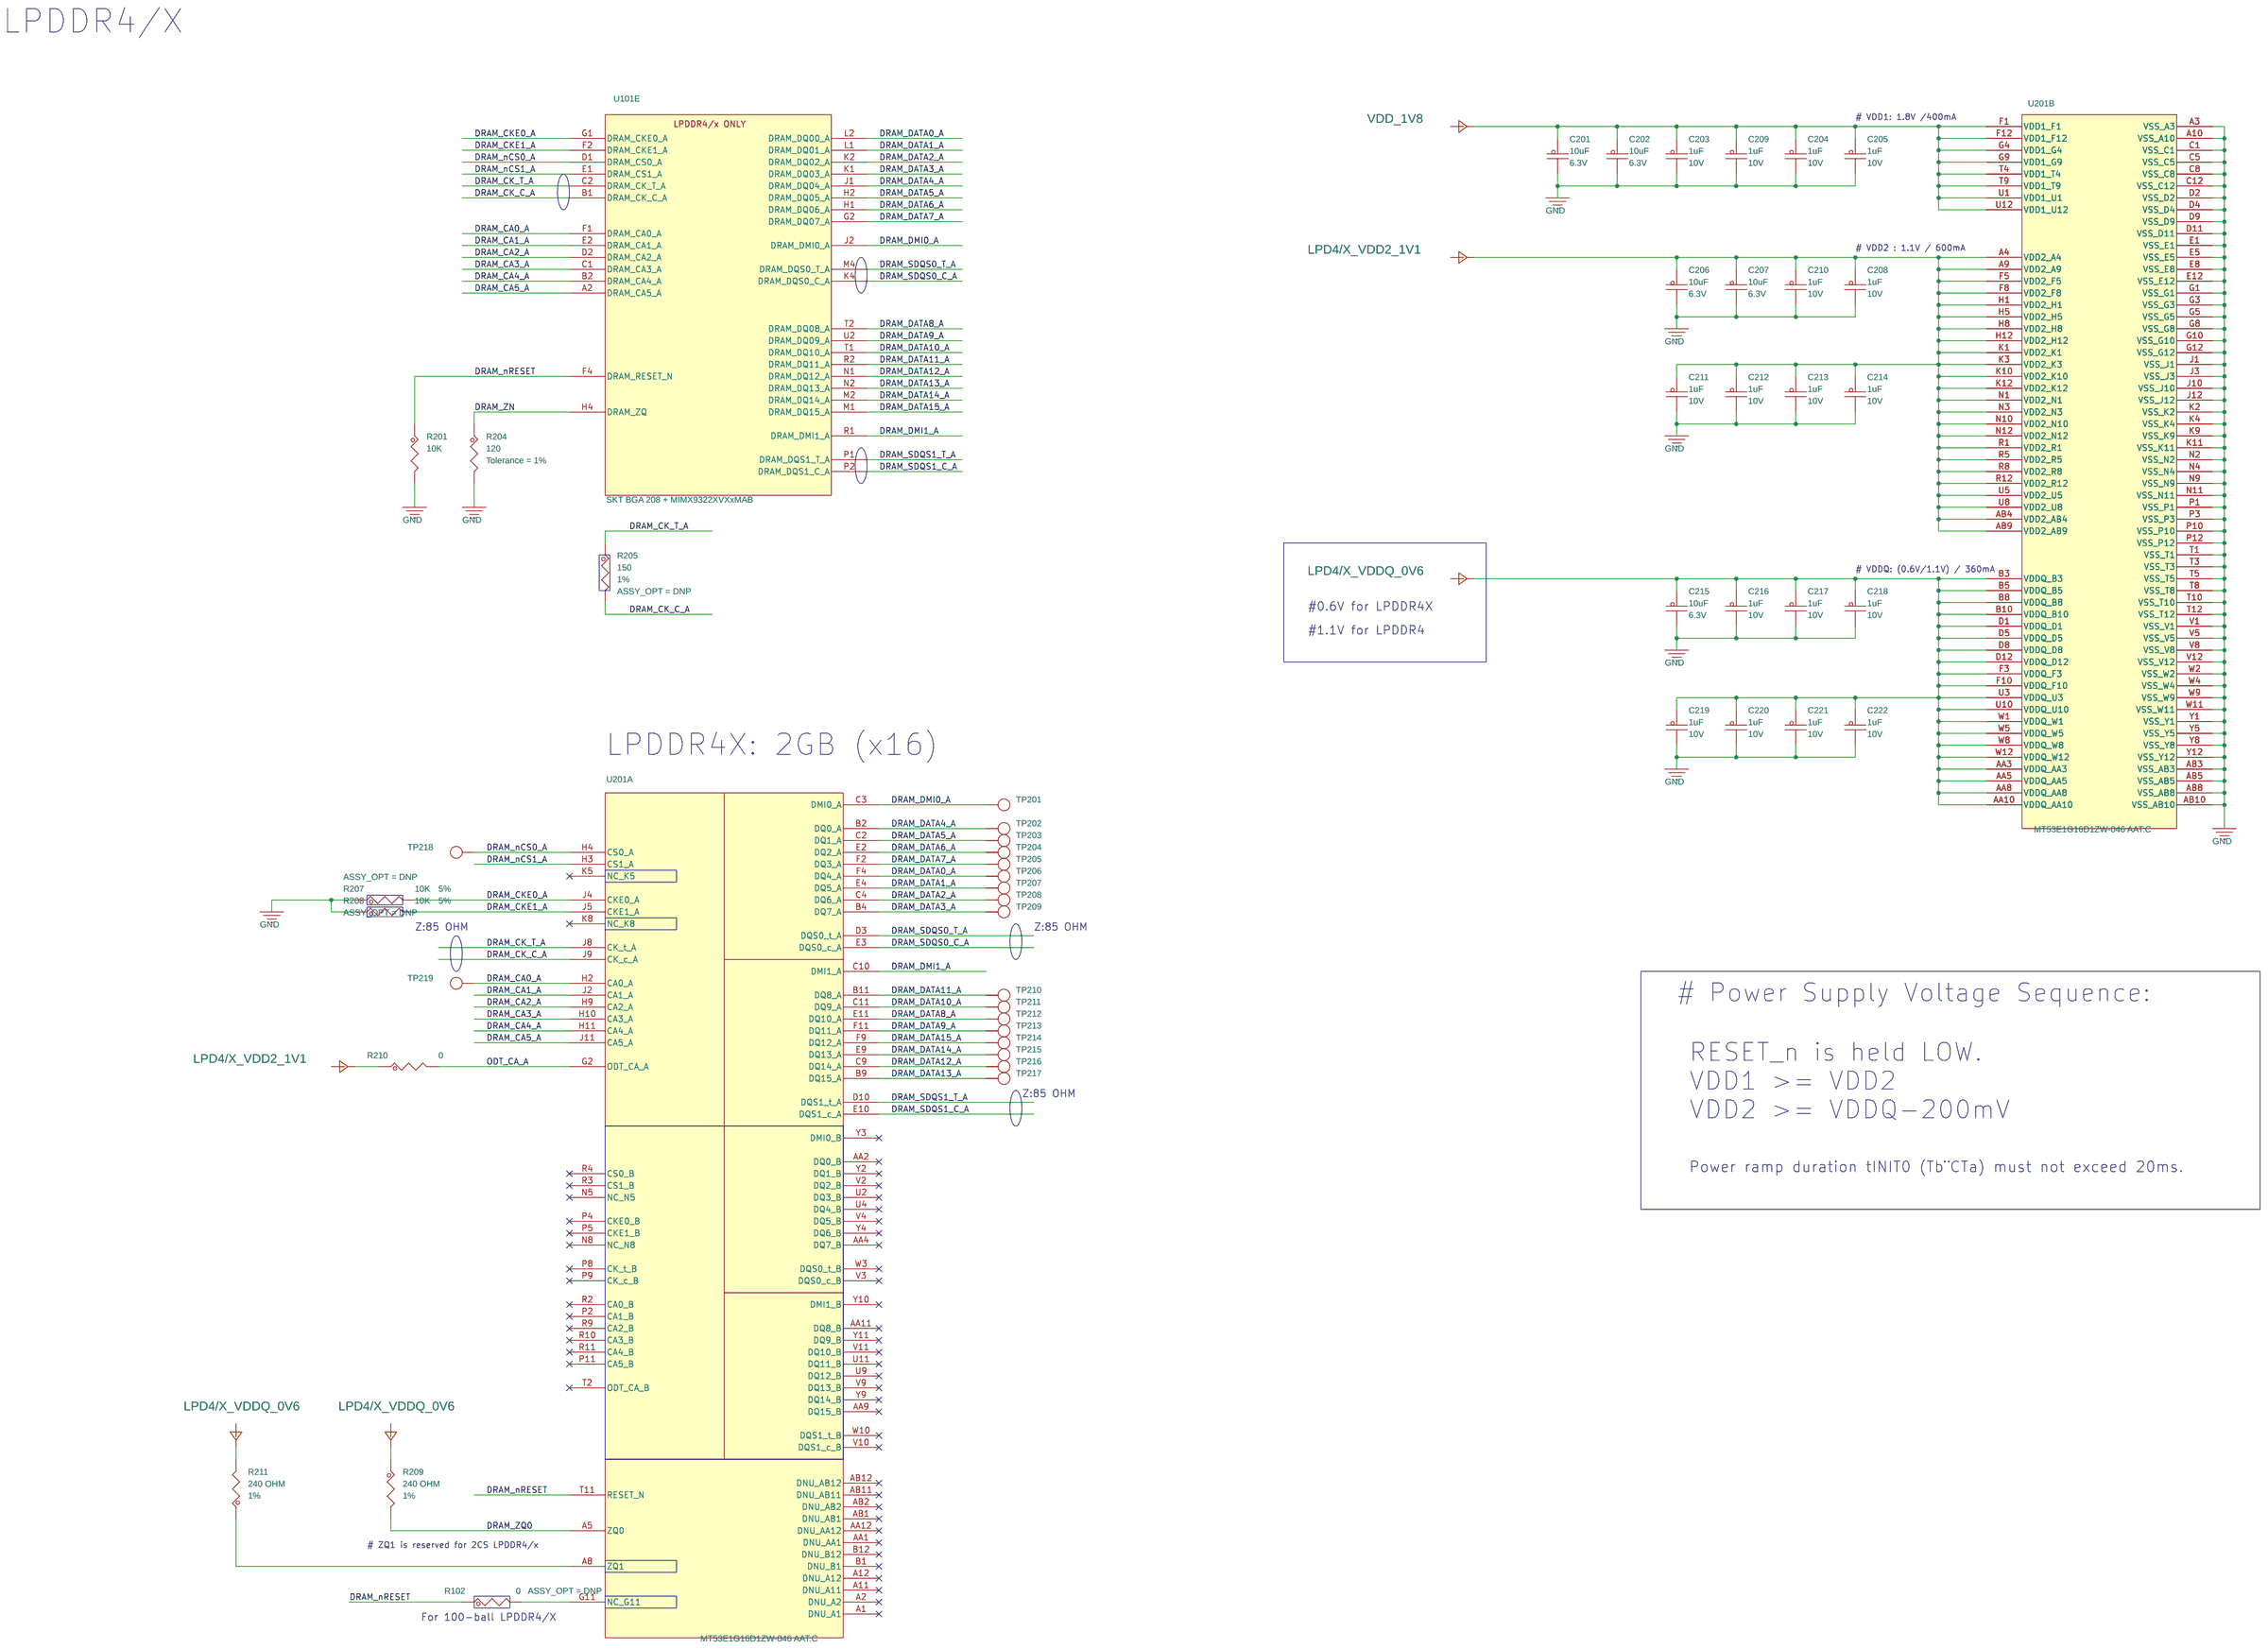
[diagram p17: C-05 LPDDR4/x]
19 C-16 RPi/IMU/ADC: size C
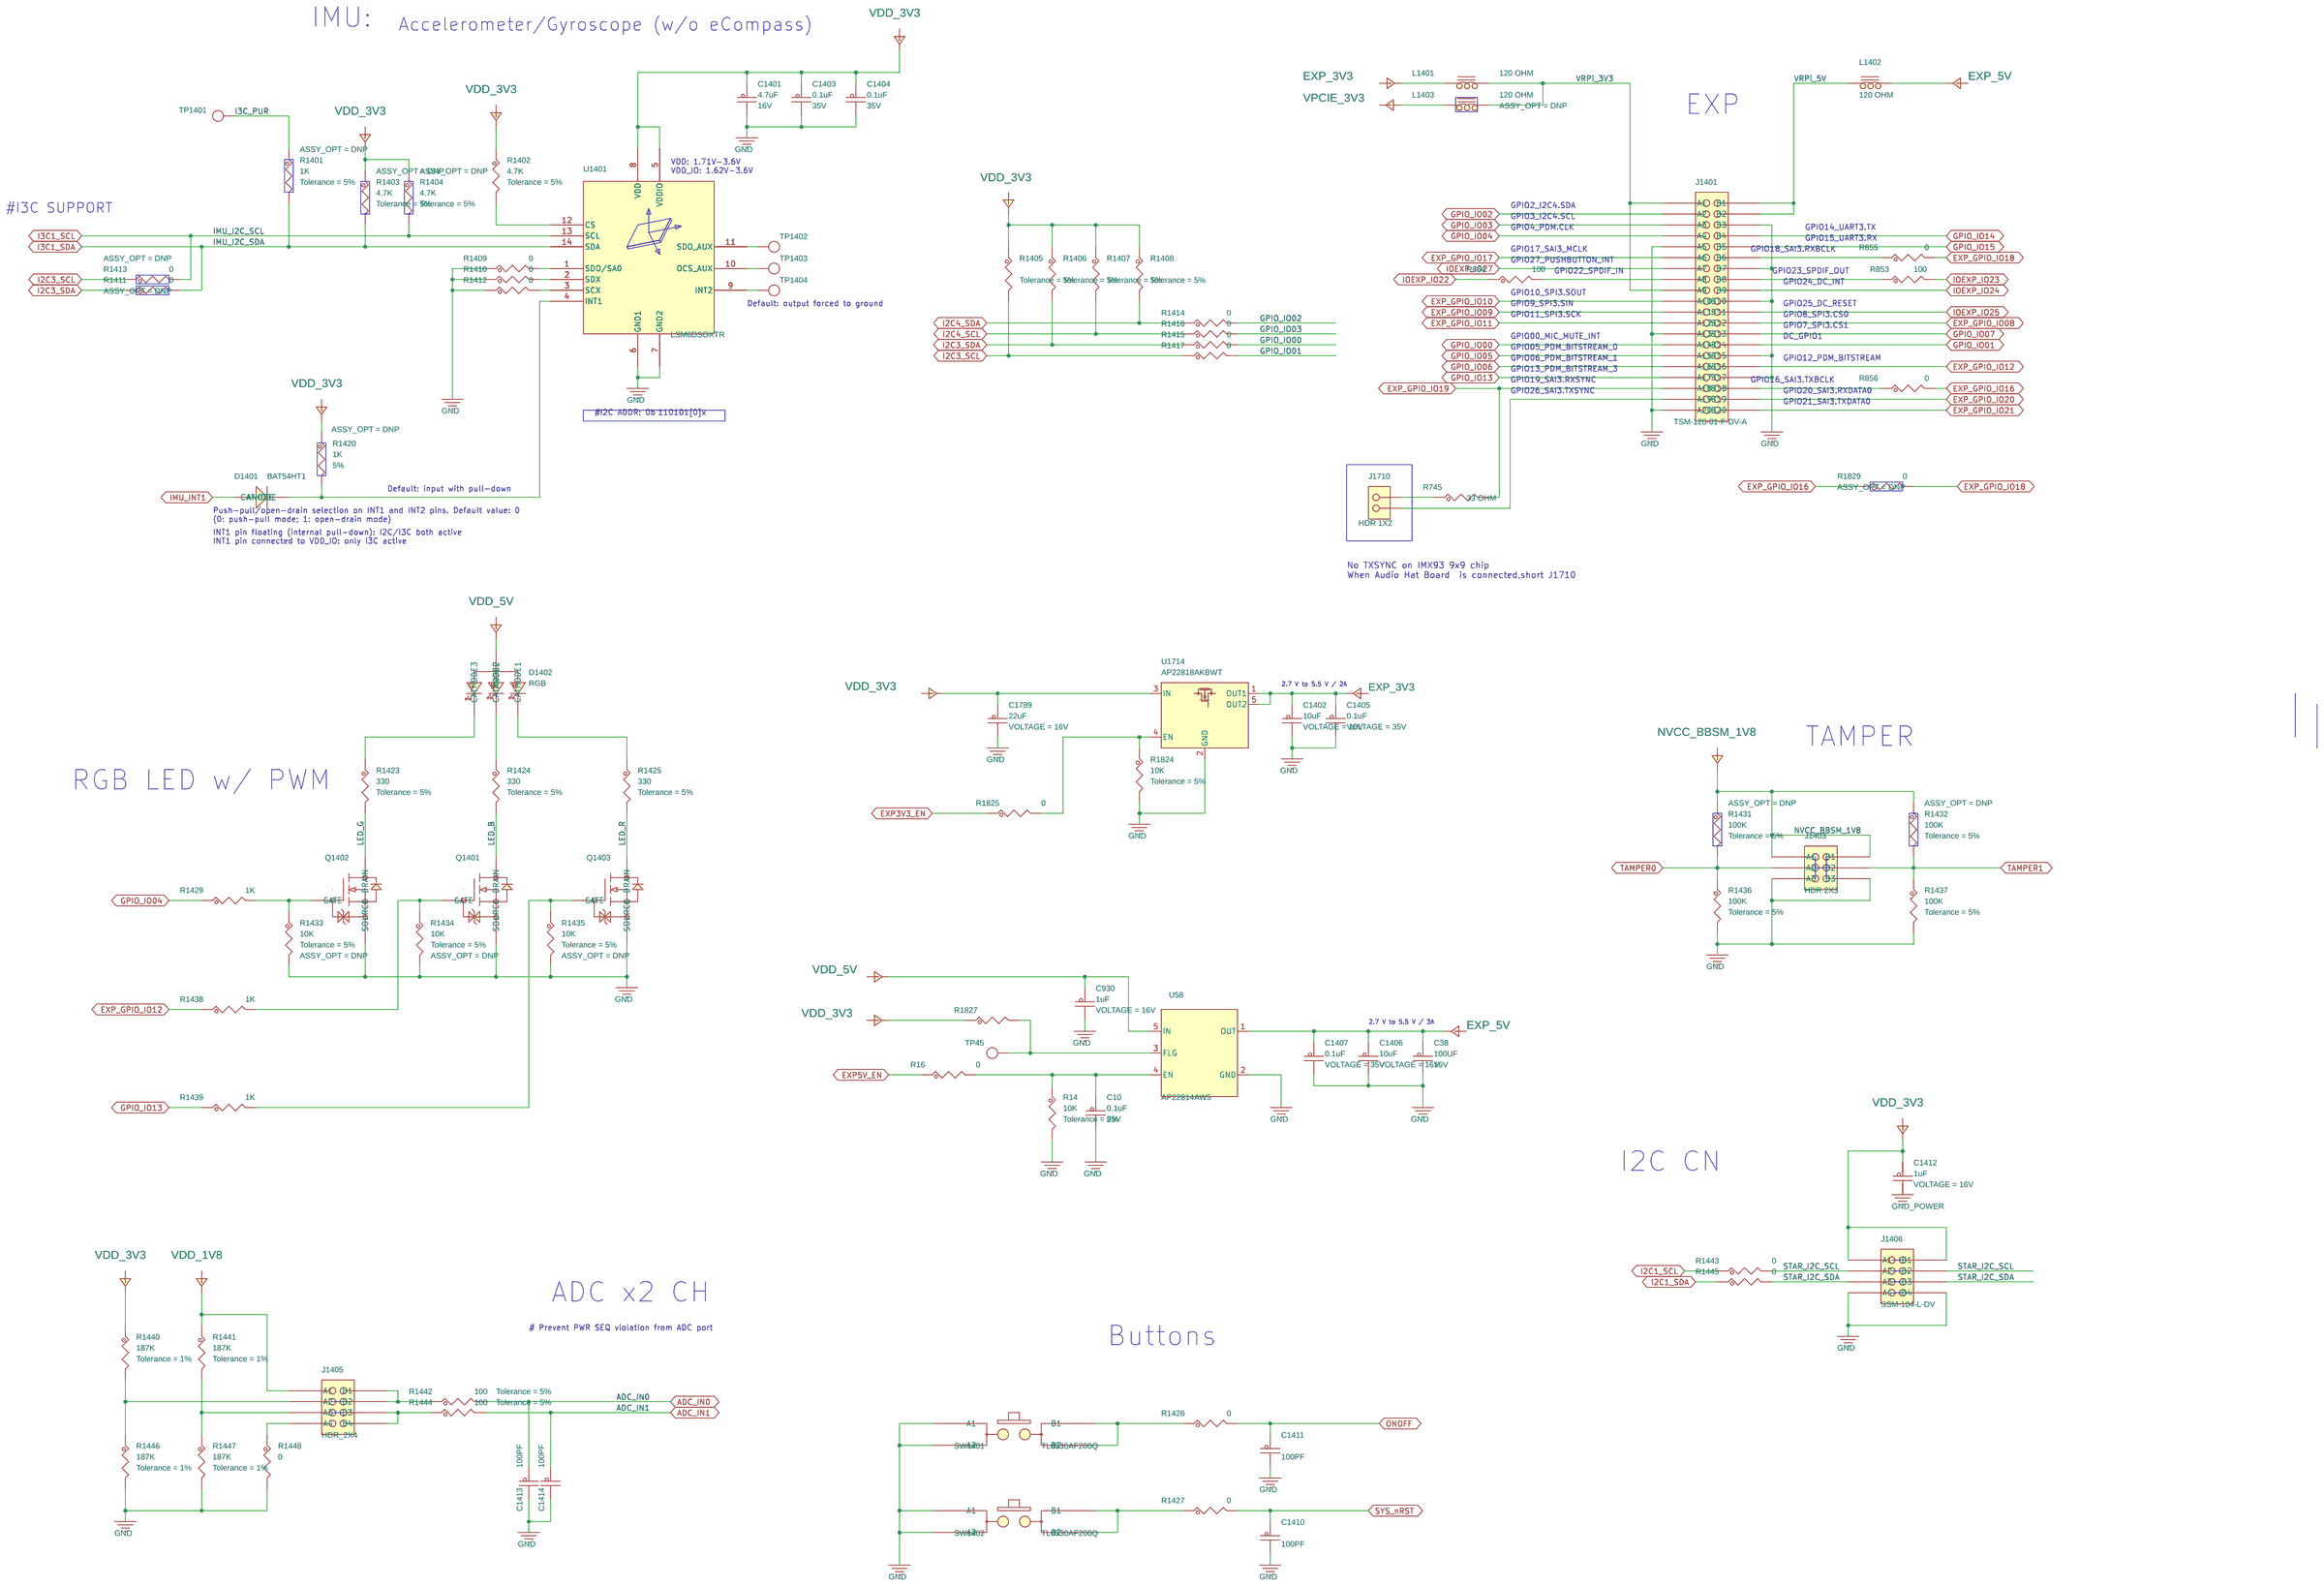
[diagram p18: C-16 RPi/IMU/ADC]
20 C-06 CPU IO/PHY: size C

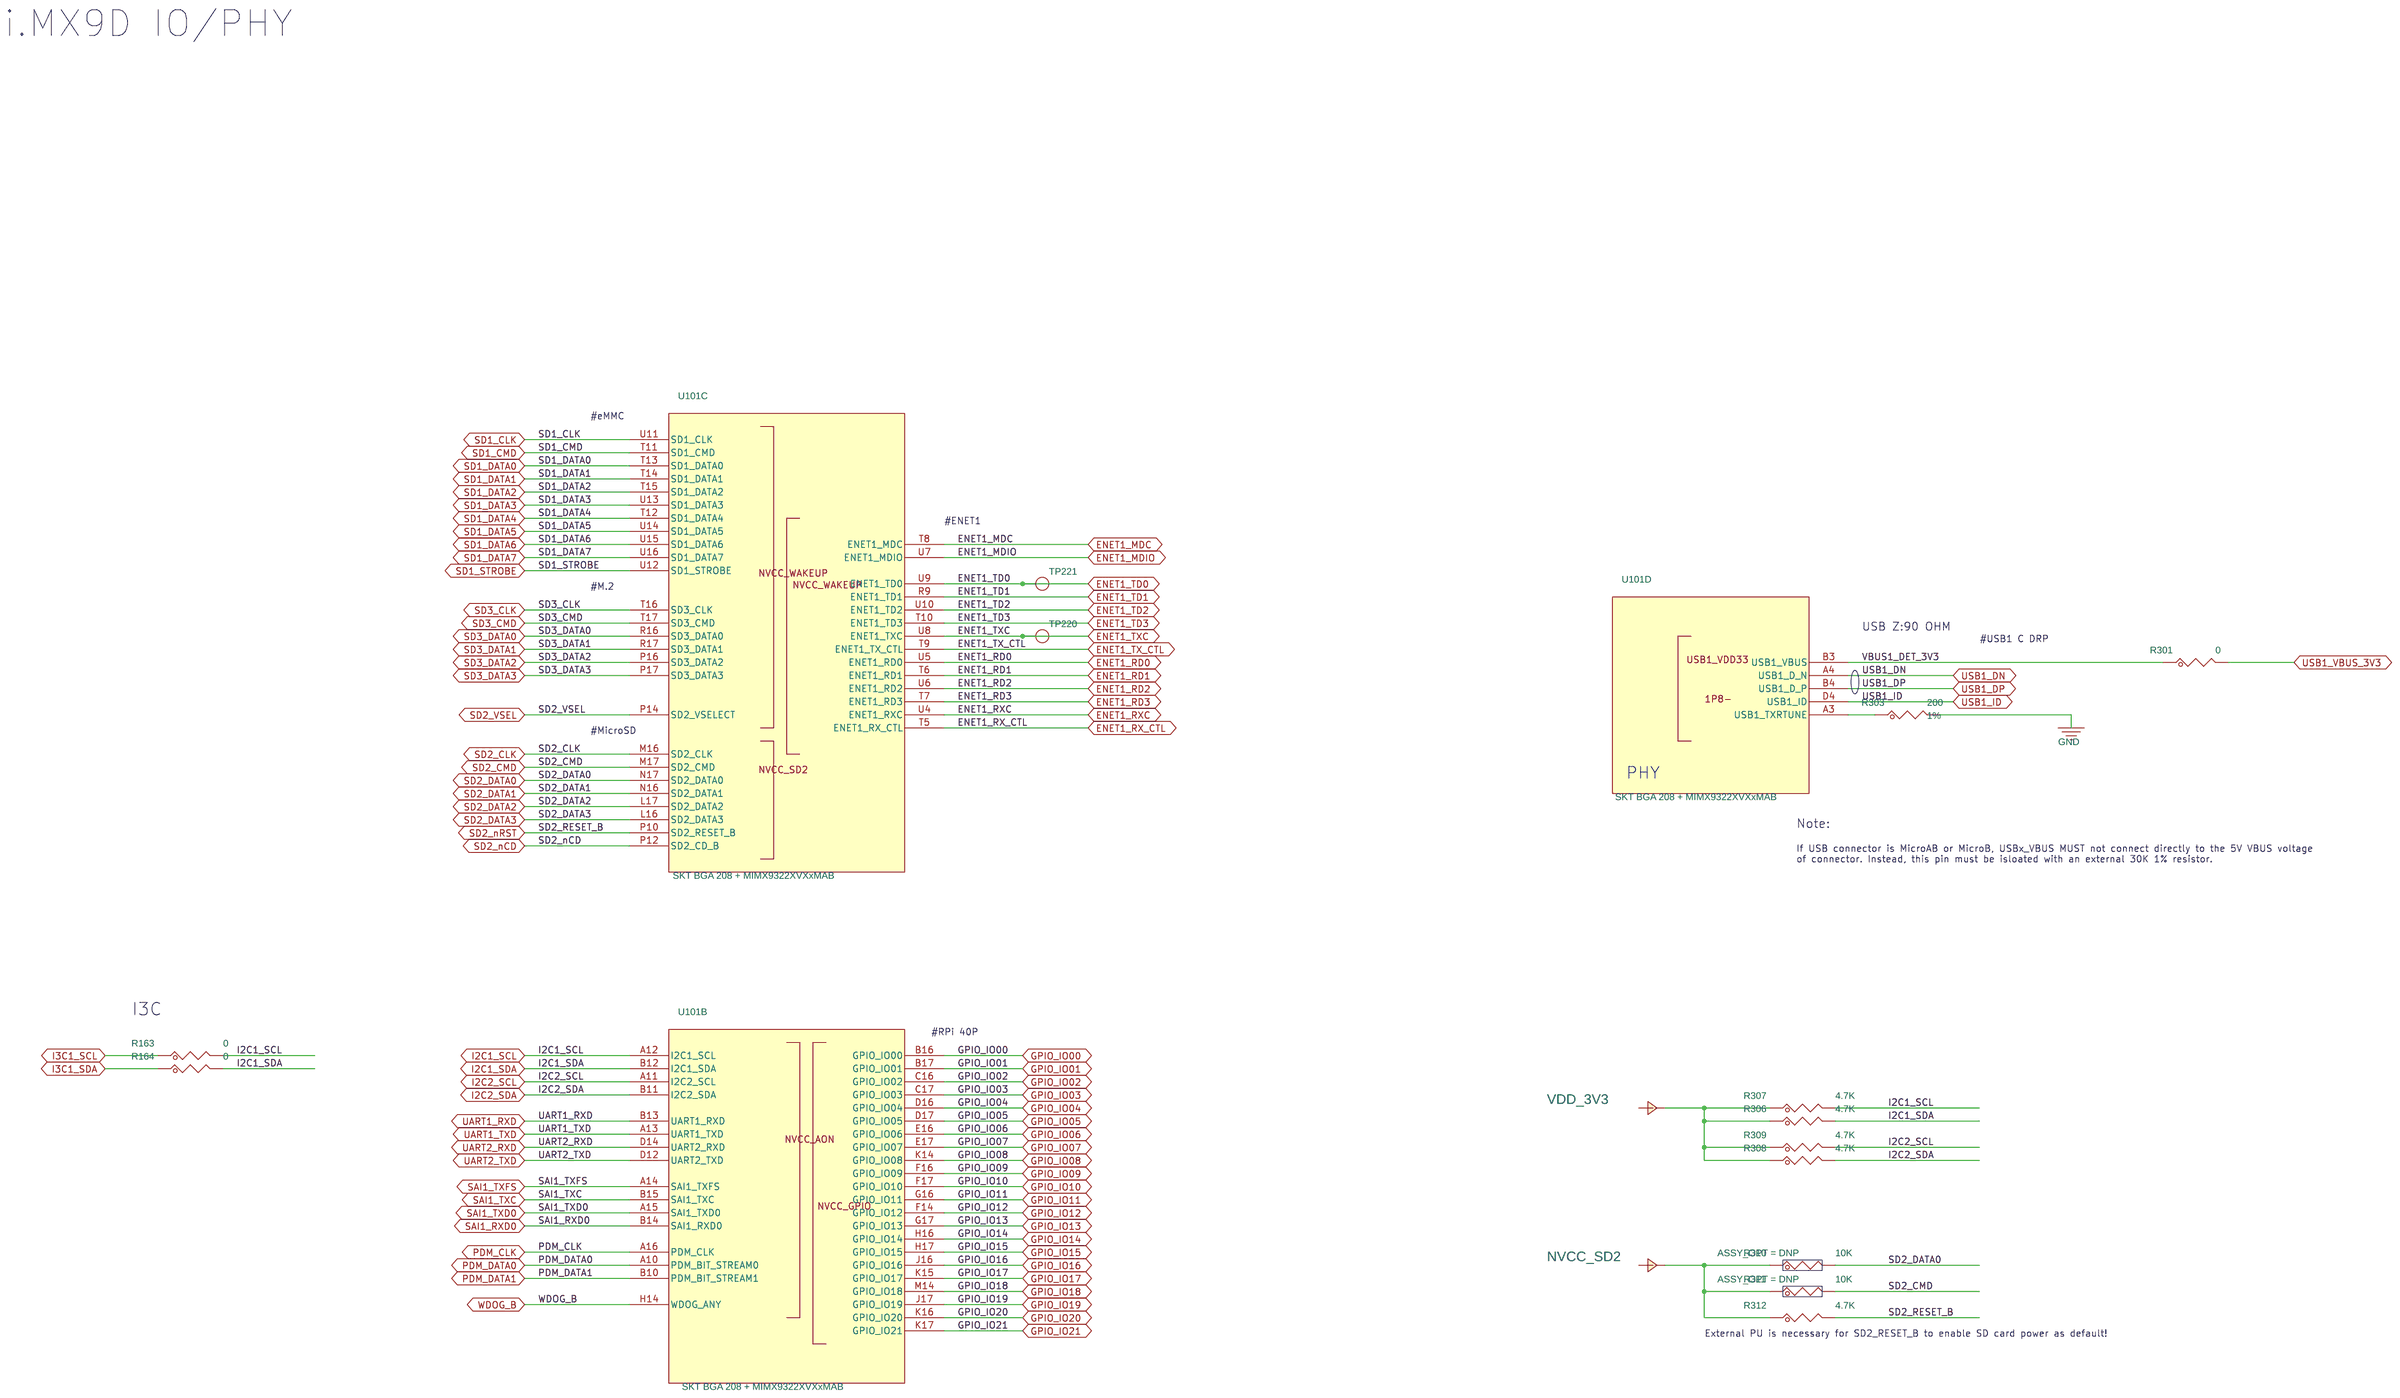
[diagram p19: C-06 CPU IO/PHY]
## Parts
sheet C-05 LPDDR4/x
C201  10uF  [0402_CC]
C202  10uF  [0402_CC]
C203  1uF  [0201_CC]
C204  1uF  [0201_CC]
C205  1uF  [0201_CC]
C206  10uF  [0402_CC]
C207  10uF  [0402_CC]
C208  1uF  [0201_CC]
C209  1uF  [0201_CC]
C210  1uF  [0201_CC]
C211  1uF  [0201_CC]
C212  1uF  [0201_CC]
C213  1uF  [0201_CC]
C214  1uF  [0201_CC]
C215  10uF  [0402_CC]
C216  1uF  [0201_CC]
C217  1uF  [0201_CC]
C218  1uF  [0201_CC]
C219  1uF  [0201_CC]
C220  1uF  [0201_CC]
C221  1uF  [0201_CC]
C222  1uF  [0201_CC]
R102  0  [rc0402_25]
R201  10K  [0402_CC]
R204  120  [0402_CC]
R205  150  [0402_CC]
R207  10K  [0402_CC]
R208  10K  [0402_CC]
R209  240 OHM  [0201_CC]
R210  0  [0402_CC]
R211  240 OHM  [0201_CC]
TP201  TPAD_015  [TPAD_015]
TP202  TPAD_015  [TPAD_015]
TP203  TPAD_015  [TPAD_015]
TP204  TPAD_015  [TPAD_015]
TP205  TPAD_015  [TPAD_015]
TP206  TPAD_015  [TPAD_015]
TP207  TPAD_015  [TPAD_015]
TP208  TPAD_015  [TPAD_015]
TP209  TPAD_015  [TPAD_015]
TP210  TPAD_015  [TPAD_015]
TP211  TPAD_015  [TPAD_015]
TP212  TPAD_015  [TPAD_015]
TP213  TPAD_015  [TPAD_015]
TP214  TPAD_015  [TPAD_015]
TP215  TPAD_015  [TPAD_015]
TP216  TPAD_015  [TPAD_015]
TP217  TPAD_015  [TPAD_015]
TP218  TPAD_015  [TPAD_015]
TP219  TPAD_015  [TPAD_015]
U201  MT53E1G16D1ZW-046 AAT:C  [bga200_0p65x0p8_10x14p5]  (sections A,B)
sheet C-06 CPU IO/PHY
R163  0  [0402_CC]
R164  0  [0402_CC]
R301  0  [0201_CC]
R303  200  [0201_CC]
R306  4.7K  [0402_CC]
R307  4.7K  [0402_CC]
R308  4.7K  [0402_CC]
R309  4.7K  [0402_CC]
R310  10K  [0402_CC]
R311  10K  [0402_CC]
R312  4.7K  [0402_CC]
TP220  TPAD_015  [TPAD_015]
TP221  TPAD_015  [TPAD_015]
sheet C-07 CPU MISC
U101  SKT BGA 208 + MIMX9322XVXxMAB  [skt_bga208_0p5_17p725sq_elast]  (sections A,B,C,D,E,F)
sheet C-09 PMIC
C701  10uF  [CC0603]
C702  10uF  [CC0603]
C703  22uF  [CC0603]
C704  1uF  [0402_CC]
C705  22uF  [CC0603]
C706  1uF  [0402_CC]
C707  22uF  [CC0603]
C708  22uF  [CC0603]
C709  10uF  [CC0603]
C710  22uF  [CC0603]
C711  22uF  [CC0603]
C712  10uF  [CC0603]
C713  10uF  [CC0603]
C714  22uF  [CC0603]
C715  22uF  [CC0603]
C716  18pF  [0201_CC]
C717  18pF  [0201_CC]
C718  10uF  [CC0603]
C719  22uF  [CC0603]
C720  22uF  [CC0603]
C721  10uF  [CC0603]
C722  22uF  [CC0603]
C723  22uF  [CC0603]
C724  1uF  [0402_CC]
C725  4.7uF  [cc0402_tol0p15]
C726  10uF  [CC0603]
C727  1uF  [0201_CC]
C728  1uF  [0201_CC]
C729  4.7uF  [cc0402_tol0p15]
C730  4.7uF  [cc0402_tol0p15]
C731  4.7uF  [cc0402_tol0p15]
L701  0.47uH  [ind_sph2520]
L702  0.47uH  [ind_sph2520]
L703  0.47uH  [ind_sph2520]
L704  0.47uH  [ind_sph2520]
L705  0.47uH  [IND_2016A]
L706  0.47uH  [IND_2016A]
QZ701  32.768KHZ  [XTAL2-3P2X1P5-SM]
R64  4.7K  [RC0402_25]
R65  4.7K  [RC0402_25]
R701  0  [0402_CC]
R702  0  [0603_CC]
R703  100K  [0402_CC]
R704  0  [0603_CC]
R705  100K  [0402_CC]
R706  0  [0402_CC]
R707  0  [0402_CC]
R708  0  [0402_CC]
R709  0  [0603_CC]
R710  0  [0402_CC]
R711  0  [0402_CC]
R712  0  [0201_CC]
R713  0  [0201_CC]
R714  0  [0402_CC]
R715  0  [0402_CC]
R716  0  [0402_CC]
R717  0  [0201_CC]
R718  0  [0402_CC]
R719  0  [0201_CC]
R720  1M  [0201_CC]
R723  0  [0402_CC]
R871  0  [0402_CC]
TP702  TP_35MIL  [testpoint_35mil]
TP703  TP_35MIL  [testpoint_35mil]
TP706  TP_35MIL  [testpoint_35mil]
TP707  TP_35MIL  [testpoint_35mil]
TP708  TP_35MIL  [testpoint_35mil]
TP709  TP_35MIL  [testpoint_35mil]
TP710  TP_35MIL  [testpoint_35mil]
TP711  TP_35MIL  [testpoint_35mil]
TP712  TP_35MIL  [testpoint_35mil]
TP713  TP_35MIL  [testpoint_35mil]
TP714  TP_35MIL  [testpoint_35mil]
TP915  TP_35MIL  [testpoint_35mil]
TP916  TP_35MIL  [testpoint_35mil]
U701  PCA9451AHNY  [hvqfn56_0p4_7x7_ep4p7mm]  (sections A,B,C)
sheet C-16 RPi/IMU/ADC
C10  0.1uF  [0402_CC]
C38  100UF  [1210_CC]
C930  1uF  [CC0402_25]
C1401  4.7uF  [CC0603_OV]
C1402  10uF  [CC0603_OV]
C1403  0.1uF  [CC0402_25]
C1404  0.1uF  [CC0402_25]
C1405  0.1uF  [CC0402_25]
C1406  10uF  [CC0603_OV]
C1407  0.1uF  [CC0402_25]
C1410  100PF  [CC0402_25]
C1411  100PF  [CC0402_25]
C1412  1uF  [CC0402_25]
C1413  100PF  [CC0402_25]
C1414  100PF  [CC0402_25]
C1789  22uF  [CC0805_OV]
D1401  BAT54HT1  [SOD323]
D1402  RGB  [led4_3p4x3_sm]
J1401  TSM-120-01-F-DV-A  [hdr220_tsm_a_sm]
J1403  HDR 2X3  [hdr203_tmm_210h]
J1405  HDR_2X4  [HDR204_TMM_SM]
J1406  SSM-104-L-DV  [con_2x4_skt_100_sm]
J1710  HDR 1X2  [hdr102_tmm]
L1401  120 OHM  [IND_0603]
L1402  120 OHM  [IND_0603]
L1403  120 OHM  [IND_0603]
Q1401  NX3008NBKW,115  [sc70_3]
Q1402  NX3008NBKW,115  [sc70_3]
Q1403  NX3008NBKW,115  [sc70_3]
R14  10K  [0402_CC]
R16  0  [0402_CC]
R745  33 OHM  [RC0402_25]
R853  100  [RC0402_25]
R854  100  [RC0402_25]
R855  0  [0402_CC]
R856  0  [0402_CC]
R1401  1K  [0402_CC]
R1402  4.7K  [RC0402_25]
R1403  4.7K  [RC0402_25]
R1404  4.7K  [RC0402_25]
R1405  2.2K  [0402_CC]
R1406  2.2K  [0402_CC]
R1407  2.2K  [0402_CC]
R1408  2.2K  [0402_CC]
R1409  0  [0402_CC]
R1410  0  [0402_CC]
R1411  0  [0402_CC]
R1412  0  [0402_CC]
R1413  0  [0402_CC]
R1414  0  [0402_CC]
R1415  0  [0402_CC]
R1416  0  [0402_CC]
R1417  0  [0402_CC]
R1420  1K  [0402_CC]
R1423  330  [RC0402_25]
R1424  330  [RC0402_25]
R1425  330  [RC0402_25]
R1426  0  [0402_CC]
R1427  0  [0402_CC]
R1429  1K  [0402_CC]
R1431  100K  [0402_CC]
R1432  100K  [0402_CC]
R1433  10K  [0402_CC]
R1434  10K  [0402_CC]
R1435  10K  [0402_CC]
R1436  100K  [0402_CC]
R1437  100K  [0402_CC]
R1438  1K  [0402_CC]
R1439  1K  [0402_CC]
R1440  187K  [0402_CC]
R1441  187K  [0402_CC]
R1442  100  [RC0402_25]
R1443  0  [0402_CC]
R1444  100  [RC0402_25]
R1445  0  [0402_CC]
R1446  187K  [0402_CC]
R1447  187K  [0402_CC]
R1448  0  [0402_CC]
R1824  10K  [0402_CC]
R1825  0  [0402_CC]
R1827  10K  [0402_CC]
R1829  0  [0402_CC]
SW1401  TL6330AF200Q  [sw4_spst_4p6x2p8_sm]
SW1402  TL6330AF200Q  [sw4_spst_4p6x2p8_sm]
TP45  TPAD_050  [TPAD_050]
TP1401  TPAD_020  [tpad_020]
TP1402  TEST POINT  [tp_th_018]
TP1403  TEST POINT  [tp_th_018]
TP1404  TEST POINT  [tp_th_018]
U58  AP22814AW5  [sot25]
U1401  LSM6DSOXTR  [lga14_0p5_3x2p5]
U1714  AP22818AKBWT  [sot23-5]

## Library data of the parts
C201 C202 C206 C207 C215 = CAP_NP: CAP CER 10UF 6.3V 20% X5R 0402; 3D_Mechanical_Footprint_File: cc0402_tol0p2; AGILE_PN: 150-79163; CAD_APPROVED: Yes; FPLIST: CC0402_25,CC0402_HD,0402_CC; HEIGHT: 0.7 MM; MFG_NAME01: SAMSUNG ELECTRO MECHANICS; MFG_PN01: CL05A106MQ5NUNC; ROHS: Yes; Tolerance: 20%; VOLTAGE: 6.3V
C203-C205 C208-C214 C216-C222 C727 C728 = CAP_NP: CAP CER 1.0uF 10V 10% X5R 0201; AGILE_PN: 150-81088; CAD_APPROVED: Yes; FPLIST: CC0201,CC0201_HD,0201_CC,cc_0201_cir; HEIGHT: 0.35MM; MFG_NAME01: SAMSUNG ELECTRO MECHANICS; MFG_PN01: CL03A105KP3NSNC; Package Size: 0201 (0603 Metric); Package Type: SMD/SMT; ROHS: Yes; Temp Range: -55°C to 85°C; Tolerance: 10%; VOLTAGE: 10V
R102 = RES: RES MF ZERO OHM 1/8W -- AEC-Q200 0402; AGILE_PN: 470-82894; ASSY_OPT: DNP; CAD_APPROVED: Yes; FPLIST: rc0402_25,rc0402_hd,0402_cc; HEIGHT: 0.4 MM; MFG_NAME01: VISHAY; MFG_PN01: RCC04020000Z0ED; Package Size: 0402 [1005 Metric]; Package Type: SMD/SMT; ROHS: Yes; Temp Range: -55 °C to +155 °C
R14 R201 R1824 R1827 = RES: RES MF 10K 1/16W 5% 0402; AGILE_PN: 470-75557; CAD_APPROVED: Yes; FPLIST: RC0402_25,RC0402_HD,0402_CC; HEIGHT: 0.4 MM; MFG_NAME01: VISHAY INTERTECHNOLOGY; MFG_PN01: CRCW040210K0JNED; ROHS: Yes; Tolerance: 5%
R204 = RES: RES MF 120 OHM 1/10W 1% AEC-Q200 0402; AGILE_PN: 470-82646; CAD_APPROVED: Yes; FPLIST: RC0402_25,RC0402_HD,0402_CC; HEIGHT: 0.4MM; MFG_NAME01: Panasonic; MFG_PN01: ERJ-2RKF1200X; ROHS: Yes; Temp Range: -55°C ~ 155°C; Tolerance: 1%; VOLTAGE: 1/10W
R205 = RES: RES MF 150 OHM 1/16W 1% 0402; AGILE_PN: 470-75353; ASSY_OPT: DNP; CAD_APPROVED: Yes; FPLIST: RC0402_25,RC0402_HD,0402_CC; HEIGHT: 0.4MM; MFG_NAME01: NIC COMPONENTS CORP; MFG_PN01: NRCL04F1500TRF; ROHS: Yes; Tolerance: 1%
R207 R208 R310 R311 R1433-R1435 = RES: RES MF 10K 1/16W 5% 0402; AGILE_PN: 470-75557; ASSY_OPT: DNP; CAD_APPROVED: Yes; FPLIST: RC0402_25,RC0402_HD,0402_CC; HEIGHT: 0.4 MM; MFG_NAME01: VISHAY INTERTECHNOLOGY; MFG_PN01: CRCW040210K0JNED; ROHS: Yes; Tolerance: 5%
R209 R211 = RES: RES MF 240 OHM 1/20W 1% 0201; AGILE_PN: 470-81317; CAD_APPROVED: Yes; FPLIST: CC0201,CC0201_HD,0201_CC; HEIGHT: 0.26MM; MFG_NAME01: YAGEO AMERICA; MFG_PN01: RC0201FR-07240RL; ROHS: Yes; Temp Range: -55°C ~ 125°C; Temp_Range: -55°C ~ 125°C; Tolerance: 1%; VOLTAGE: 25V
R163 R164 R210 R701 R706-R708 R710 R714 R715 R718 R723 R855 R856 R1409 R1410 R1412 R1414-R1417 R1426 R1427 R1443 R1445 R1448 = RES: RES MF ZERO OHM 1/16W 5% 0402; AGILE_PN: 470-75394; CAD_APPROVED: Yes; FPLIST: RC0402_25,RC0402_HD,RC0402_X2,0402_CC; HEIGHT: 0.45 MM; MFG_NAME01: YAGEO AMERICA; MFG_PN01: RC0402JR-070RL; ROHS: Yes; Tolerance: 5%; VOLTAGE: 1/16W
TP201-TP221 = TestLoop: TEST POINT PAD 15MIL DIA SMT, NO PART TO ORDER; AGILE_PN: 211-76645; CAD_APPROVED: Yes; HEIGHT: 0.1MM; MFG_NAME01: NOTACOMPONENT; MFG_PN01: NOTACOMPONENT; ROHS: Yes
U201 = MT53E1G16D1FW-046_200P_A: IC MEM LPDDR4/LPDDR4X SDRAM 1GX16 1.1V AEC-Q100 TFBGA200; 3D_Mechanical_Footprint_File: http://fcl.am.freescale.net/ALLEGRO/step/bga200_0p65x0p8_10x14p5.STEP; AGILE_PN: 334-10016; CAD_APPROVED: Yes; HEIGHT: 1.1; MFG_NAME01: Micron; Package Size: 10.0 x 14.5 x 1.0MM; ROHS: NULL; Supply Voltage: 1.1V; Temp Range: -40C to +105C; VOLTAGE: 1.1V
R301 R712 R713 R717 R719 = RES: RES MF ZERO OHM 1/20W -- 0201; AGILE_PN: 470-76631; CAD_APPROVED: Yes; FPLIST: RC0201,0201_CC,RC0201_X2; HEIGHT: 0.30 MM; MFG_NAME01: BOURNS; MFG_PN01: CR0201-J/-000GLF; ROHS: Yes
R303 = RES: RES MF 200 OHM 1/20W 1% 0201; AGILE_PN: 470-82323; CAD_APPROVED: Yes; FPLIST: RC0201,0201_CC; HEIGHT: 0.26MM; MFG_NAME01: YAGEO AMERICA; MFG_PN01: RC0201FR-07200RL; ROHS: Yes; Temp Range: -55°C ~ 125°C; Temp_Range: -55°C ~ 125°C; Tolerance: 1%; VOLTAGE: 25V
R64 R65 R306-R309 R312 = RES: RES MF 4.7K 1/10W 5% AEC-Q200 0402; AGILE_PN: 470-82064; CAD_APPROVED: Yes; FPLIST: RC0402_25,RC0402_HD,0402_CC,RC0402_X2; HEIGHT: 0.41mm; MFG_NAME01: KOA SPEER; MFG_PN01: RK73B1ETTP472J; ROHS: Yes; Temp Range: -55C to +155C; Temp_Range: -55C to +155C; Tolerance: 5%; VOLTAGE: 50V
U101 = MIMX9322XVXxMAB_BGA208: SUBASSEMBLY SKT 208 BGA ELASTOMER SMT 0.5MM 414H AU + IC CPU 1.7GHz -- FCPBGA208; AGILE_PN: TMP-CIP-14977; HEIGHT: 10.503MM; MFG_NAME01: SUBASSEMBLY; MFG_PN01: 211-81858,330-77547; PRE_APN: 750-79017; ROHS: Yes
C701 C702 C709 C712 C713 C718 C721 C726 = CAP_NP: CAP CER 10.0uF 16V 10% X5R 0603; AGILE_PN: 150-80060; CAD_APPROVED: Yes; FPLIST: CC0603_OV,CC0603,0603_CC,cc0603_0805_nsp; HEIGHT: 0.9MM; MFG_NAME01: MURATA; MFG_PN01: GRM188R61C106KAALD; Package Size: 0603; Package Type: SMT; ROHS: Yes; Temp Range: -55°C to +85°C; Temp_Range: -55°C to +85°C; Tolerance: 10%; VOLTAGE: 16V
C703 C707 C710 C714 C715 C719 C720 C722 = CAP_NP: CAP CER 22uF 10V 20% X5R 0603; AGILE_PN: 150-79530; CAD_APPROVED: Yes; FPLIST: CC0603_OV,CC0603,0603_cc_tol; HEIGHT: 1MM; MFG_NAME01: TDK; MFG_PN01: C1608X5R1A226M080AC; Package Size: 0603; ROHS: Yes; SIGNAL_MODEL: DEFAULT_CAPACITOR_2.2e+07pF_2_1; Tolerance: 20%; VOLTAGE: 10V; WVDC: 6.3V
C704 C706 C724 C930 = CAP_NP: CAP CER 1uF 16V 10% X5R 0402; AGILE_PN: 150-78973; CAD_APPROVED: Yes; FPLIST: CC0402_25,CC0402_HD,0402_CC,capc0402_l; HEIGHT: 0.55 MM; MFG_NAME01: YAGEO; MFG_PN01: CC0402KRX5R7BB105; ROHS: Yes; Tolerance: 10%; VOLTAGE: 16V
C705 C708 C711 C723 = CAP_NP: CAP CER 22uF 10V 20% X5R 0603; AGILE_PN: 150-79530; ASSY_OPT: DNP; CAD_APPROVED: Yes; FPLIST: CC0603_OV,CC0603,0603_cc_tol; HEIGHT: 1MM; MFG_NAME01: TDK; MFG_PN01: C1608X5R1A226M080AC; Package Size: 0603; ROHS: Yes; SIGNAL_MODEL: DEFAULT_CAPACITOR_2.2e+07pF_2_1; Tolerance: 20%; VOLTAGE: 10V; WVDC: 6.3V
C716 C717 = CAP_NP: CAP CER 18pF 50V 5% C0G 0201; AGILE_PN: 150-79476; CAD_APPROVED: Yes; FPLIST: CC0201,CC0201_HD,0201_CC; HEIGHT: 0.33MM; MFG_NAME01: MURATA; MFG_PN01: GRM0335C1H180JA01D; Package Size: 0201; Package Type: &#966;180mm Paper taping; ROHS: Yes; Tolerance: 5%; VOLTAGE: 50V
C725 C729-C731 = CAP_NP: CAP CER 4.7uF 10V 10% X5R 0402; AGILE_PN: 150-80044; CAD_APPROVED: Yes; FPLIST: cc0402_tol0p15,cc0402_tol0p15_ov,0402_cc_nsp; HEIGHT: 0.65MM; MFG_NAME01: SAMSUNG ELECTRO MECHANICS; MFG_PN01: CL05A475KP5NRNC; ROHS: Yes; Tolerance: 10%; VOLTAGE: 10V
L701-L704 = INDUCTOR: IND PWR 0.47uH@1MHZ 4.7A 20% SMT; AGILE_PN: 180-78647; CAD_APPROVED: Yes; HEIGHT: 1.2MM; MFG_NAME01: SHENZHEN SUNLORD ELECTRONICS CO., LTD; MFG_PN01: WPN252012ER47MT; PART_TYPE: INDUCTOR\POWER; ROHS: Yes; TOL: 20%; Temp Range: -40°C to +125°C; Temp_Range: -40°C to +125°C; Tolerance: 20%
L705 L706 = INDUCTOR: IND PWR 0.47uH@1MHz 3.4A 20% 2016; AGILE_PN: 180-78995; CAD_APPROVED: Yes; HEIGHT: 1.2MM; MFG_NAME01: SHENZHEN SUNLORD ELECTRONICS CO., LTD; MFG_PN01: WPN201612HR47MT; PART_TYPE: INDUCTOR\POWER; Package Size: 2x1.6x1.2 mm; ROHS: Yes; Temp Range: -40°C to 125°C; Temp_Range: -40°C to 125°C; Tolerance: 20%
QZ701 = XTAL: XTAL 32.768KHZ 12.5PF 20PPM 3.2X1.5MM SMT; AGILE_PN: 230-77653; CAD_APPROVED: Yes; HEIGHT: 0.9MM; MFG_NAME01: Abracon Corporation; MFG_PN01: ABS07-32.768KHZ-T; ROHS: Yes
R702 = RES: RES MF ZERO OHM 1/10W -- 0603; AGILE_PN: 470-80866; ASSY_OPT: DNP; CAD_APPROVED: Yes; FPLIST: RC0603_OV,RC0603,R603-X2,0603_CC,IND_0603HP_NSP,CC0603_OV_NSP; HEIGHT: 0.6MM; MFG_NAME01: YAGEO AMERICA; MFG_PN01: RC0603FR-070RL; ROHS: Yes; Temp Range: –55 °C to +155 °C
R703 = RES: RES MF 100K 1/16W 5% 0402; AGILE_PN: 470-75597; ASSY_OPT: DNP; CAD_APPROVED: Yes; FPLIST: RC0402_25,RC0402_HD,0402_CC; HEIGHT: 0.40 MM; MFG_NAME01: VENKEL COMPANY; MFG_PN01: CR0402-16W-104JT; ROHS: Yes; Temp Range: -55C to +155C; Tolerance: 5%; VOLTAGE: 50V
R704 R709 = RES: RES MF ZERO OHM 1/10W -- 0603; AGILE_PN: 470-80866; CAD_APPROVED: Yes; FPLIST: RC0603_OV,RC0603,R603-X2,0603_CC,IND_0603HP_NSP,CC0603_OV_NSP; HEIGHT: 0.6MM; MFG_NAME01: YAGEO AMERICA; MFG_PN01: RC0603FR-070RL; ROHS: Yes; Temp Range: –55 °C to +155 °C
R705 = RES: RES MF 100K 1/16W 5% 0402; AGILE_PN: 470-75597; CAD_APPROVED: Yes; FPLIST: RC0402_25,RC0402_HD,0402_CC; HEIGHT: 0.40 MM; MFG_NAME01: VENKEL COMPANY; MFG_PN01: CR0402-16W-104JT; ROHS: Yes; Temp Range: -55C to +155C; Tolerance: 5%; VOLTAGE: 50V
R711 R716 R1411 R1413 R1829 = RES: RES MF ZERO OHM 1/16W 5% 0402; AGILE_PN: 470-75394; ASSY_OPT: DNP; CAD_APPROVED: Yes; FPLIST: RC0402_25,RC0402_HD,RC0402_X2,0402_CC; HEIGHT: 0.45 MM; MFG_NAME01: YAGEO AMERICA; MFG_PN01: RC0402JR-070RL; ROHS: Yes; Tolerance: 5%; VOLTAGE: 1/16W
R720 = RES: RES MF 1.0M 1/20W 5% AEC-Q200 0201; AGILE_PN: 470-79975; ASSY_OPT: DNP; CAD_APPROVED: Yes; FPLIST: RC0201,0201_CC; HEIGHT: 0.26MM; MFG_NAME01: PANASONIC; MFG_PN01: ERJ-1GNJ105C; ROHS: Yes; Temp Range: 55°C ~ 125°C; Temp_Range: 55°C ~ 125°C; Tolerance: 5%; VOLTAGE: 25V
R16 R871 R1825 = RES: RES MF ZERO OHM 1/16W 5% 0402; AGILE_PN: 470-75394; CAD_APPROVED: Yes; FPLIST: RC0402_25,RC0402_HD,RC0402_X2,0402_CC; HEIGHT: 0.45 MM; MFG_NAME01: ROHM; MFG_PN01: MCR01MZPJ000; ROHS: Yes; Tolerance: 5%; VOLTAGE: 1/16W
TP702 TP703 TP706-TP714 TP915 TP916 = T_POINT_R: TEST POINT PAD .035 SMT, no part to order; AGILE_PN: 510-75618; ASSY_OPT: DNP; CAD_APPROVED: Yes; HEIGHT: 0.1MM; ROHS: Yes
U701 = PCA9451AHNY: IC POWER MANAGEMENT 2.7-5.5V HVQFN56; 3D_Mechanical_Footprint_File: http://fcl.am.freescale.net/ALLEGRO/step/hvqfn56_0p4_7x7_ep4p7mm.step; AGILE_PN: TMP-CIP-8249; CAD_APPROVED: Yes; HEIGHT: 1MM; MFG_NAME01: NXP SEMICONDUCTORS; PRE_APN: 315-83273; Package Size: 7x7; ROHS: Yes
C10 = CAP_NP: CAP CER 0.1UF 25V 10% X5R 0402; AGILE_PN: 150-78633; CAD_APPROVED: Yes; FPLIST: CC0402_25,CC0402_HD,0402_CC; HEIGHT: 0.55MM; MFG_NAME01: YAGEO AMERICA; MFG_PN01: CC0402KRX5R8BB104; Package Size: 0402; ROHS: Yes; Tolerance: 10%; VOLTAGE: 25V
C38 = CAP_NP: CAP CER 100uF 16V 20% X5R 1210; AGILE_PN: 150-79142; CAD_APPROVED: Yes; FPLIST: CC1210,1210_CC; HEIGHT: 2.8MM; MFG_NAME01: TAIYO YUDEN; MFG_PN01: EMK325ABJ107MM-T; Package Size: 1210; ROHS: Yes; Tolerance: 20%; VOLTAGE: 16V
C1401 = CAP_NP: CAP CER 4.7uF 16V 10% X5R 0603; AGILE_PN: 150-80061; CAD_APPROVED: Yes; EN: 102-1-01650; FPLIST: CC0603_OV,CC0603,cc0603_0805_nsp,0603_CC_NSP; HEIGHT: 0.95MM; MFG_NAME01: MURATA; MFG_PN01: GRM188R61C475KE11D; ROHS: Yes; TOL: 10%; Temp Range: -55°C to + 85°C; VOLTAGE: 16V
C1402 C1406 = CAP_NP: CAP CER 10uF 16V 20% X5R 0603; AGILE_PN: 150-80336; CAD_APPROVED: Yes; FPLIST: CC0603_OV,CC0603,0603_CC_NSP; HEIGHT: 1MM; LEAD_FREE: YES; MFG_NAME01: MURATA; MFG_PN01: GRM188R61C106MA73D; Package Size: 0603; Package Type: SMD; ROHS: Yes; Temp_Range: -55°C ~ 85°C; Tolerance: 20%; VOLTAGE: 16V
C1403 C1404 = CAP_NP: CAP CER 0.1UF 35V 10% X5R 0402; AGILE_PN: 150-78506; CAD_APPROVED: Yes; EN: 102-1-02300; FPLIST: CC0402_25,CC0402_HD,0402_CC,capc0402_l; HEIGHT: 0.55MM; MFG_NAME01: TAIYO YUDEN; MFG_PN01: GMK105BJ104KV-F; ROHS: Yes; TOL: 10%; Tolerance: 10%; VOLTAGE: 35V
C1405 C1407 = CAP_NP: CAP CER 0.1UF 35V 10% X5R 0402; AGILE_PN: 150-78506; CAD_APPROVED: Yes; FPLIST: CC0402_25,CC0402_HD,0402_CC,capc0402_l; HEIGHT: 0.55MM; MFG_NAME01: TAIYO YUDEN; MFG_PN01: GMK105BJ104KV-F; ROHS: Yes; Tolerance: 10%; VOLTAGE: 35V
C1410 C1411 C1413 C1414 = CAP_NP: CAP CER 100PF 16V 5% C0G 0402; AGILE_PN: 150-75721; CAD_APPROVED: Yes; FPLIST: CC0402_25,CC0402_HD,0402_CC,capc0402_l; HEIGHT: 0.55MM; MFG_NAME01: KEMET; MFG_PN01: C0402C101J4GAC; Package Size: 0402; ROHS: Yes; Tolerance: 5%; VOLTAGE: 16V
C1412 = CAP_NP: CAP CER 1uF 16V 10% X5R 0402; AGILE_PN: 150-78973; CAD_APPROVED: Yes; FPLIST: CC0402_25,CC0402_HD,0402_CC,capc0402_l; HEIGHT: 0.55 MM; MFG_NAME01: YAGEO; MFG_PN01: CC0402KRX5R7BB105; ROHS: Yes; SIGNAL_MODEL: DEFAULT_CAPACITOR_1e+06pF_2_1; TOL: 10%; Tolerance: 10%; VOLTAGE: 16V; voltage rating: 10V
C1789 = CAP_NP: CAP CER 22UF 16V 20% X5R 0805; AGILE_PN: 150-81221; CAD_APPROVED: Yes; FPLIST: CC0805_OV,CC0805,0805_CC; HEIGHT: 1.45MM; MFG_NAME01: TDK Corporation; MFG_PN01: C2012X5R1C226M125AC; ROHS: Yes; Tolerance: 20%; VOLTAGE: 16V
D1401 = DIODE: DIODE SCH 30V 200MA -- SOD323; AGILE_PN: 480-30039; CAD_APPROVED: Yes; HEIGHT: 1.15MM; MFG_NAME01: ON SEMICONDUCTOR; MFG_PN01: BAT54HT1G
D1402 = LED_GPLY6900: LED RGB MULTI 20MA SMT; AGILE_PN: 370-76731; CAD_APPROVED: Yes; HEIGHT: 2.04 MM; MFG_NAME01: EVERLIGHT INTERNATIONAL CORPORATION; MFG_PN01: 67-03A/R6GHBHW-A01/2T/MS; VOLTAGE: 1.7-3.7V
J1401 = CONN_HDR_20X2: HDR 2X20 SMT 2.54MM CTR 395H AU; 3D_Mechanical_Footprint_File: ftp://fcl.am.freescale.net/ALLEGRO/step/hdr220_tsm_a_sm.step; AGILE_PN: 211-80156; CAD_APPROVED: Yes; HEIGHT: 10.03MM; MFG_NAME01: SAMTEC; ROHS: Yes; Temp Range: -55°C ~ 125°C
J1403 = CONN_HDR_3X2: HDR 2X3 TH 2MM CTR 217H AU 110L; 3D_Mechanical_Footprint_File: ftp://fcl.am.freescale.net/ALLEGRO/step/hdr203_tmm_210h.STEP; AGILE_PN: 210-77094; CAD_APPROVED: Yes; FPLIST: hdr203_tmm_210h,hdr203_tmm; HEIGHT: 5.33MM; MFG_NAME01: SAMTEC; MFG_PN01: TMM-103-02-G-D; ROHS: Yes
J1405 = CONN_HDR_4X2: HDR 2X4 SMT 78.7MIL CTR 235H AU LOPRO; 3D_Mechanical_Footprint_File: ftp://fcl.am.freescale.net/ALLEGRO/step/hdr204_tmm_sm.STEP; AGILE_PN: 211-75114; CAD_APPROVED: Yes; HEIGHT: 5.97MM; MFG_NAME01: SAMTEC; MFG_PN01: TMM-104-01-S-D-SM; Package Size: SMD-8; Package Type: SMD; ROHS: Yes; Temp Range: -55°C to +125°C
J1406 = CONN_HDR_4X2: CON 2X4 SKT SMT 2.54MM CTR 300H AU; 3D_Mechanical_Footprint_File: ftp://fcl.am.freescale.net/ALLEGRO/step/con_2x4_skt_100_sm.STEP; AGILE_PN: 211-79467; CAD_APPROVED: Yes; HEIGHT: 7.62MM; MFG_NAME01: SAMTEC; ROHS: Yes
J1710 = CONN_HDR_2X1: HDR 1X2 TH 2MM SP 217H AU 110L; AGILE_PN: 210-77112; CAD_APPROVED: Yes; FPLIST: hdr102_tmm,sh_hdr102_tmm_bottom; HEIGHT: 5.2MM; MFG_NAME01: SAMTEC; MFG_PN01: TMM-102-02-G-S; ROHS: Yes
L1401 L1402 = BEAD_0: IND FER BEAD 120OHM@100MHZ 2A 25% 0603; AGILE_PN: 180-78419; CAD_APPROVED: Yes; FPLIST: IND_0603,0603_CC; HEIGHT: 0.95MM; MFG_NAME01: SHENZHEN SUNLORD ELECTRONICS CO., LTD; MFG_PN01: PZ1608U121-2R0TF; ROHS: Yes
L1403 = BEAD_0: IND FER BEAD 120OHM@100MHZ 2A 25% 0603; AGILE_PN: 180-78419; ASSY_OPT: DNP; CAD_APPROVED: Yes; FPLIST: IND_0603,0603_CC; HEIGHT: 0.95MM; MFG_NAME01: SHENZHEN SUNLORD ELECTRONICS CO., LTD; MFG_PN01: PZ1608U121-2R0TF; ROHS: Yes
Q1401-Q1403 = NX3008NBKW_SOT323: TRAN NMOS SW 30V 350mA AEC-Q101 SC-70; AGILE_PN: 480-79736; CAD_APPROVED: Yes; HEIGHT: 1.1MM; MFG_NAME01: NEXPERIA; ROHS: Yes
R745 = RES: RES MF 33 OHM 1/10W 1% AEC-Q200  0402; AGILE_PN: 470-80961; CAD_APPROVED: Yes; FPLIST: RC0402_25,RC0402_HD,0402_CC; HEIGHT: 0.4 MM; MFG_NAME01: PANASONIC; MFG_PN01: ERJ2RKF33R0X; ROHS: Yes; Tolerance: 1%
R853 R854 R1442 R1444 = RES: RES MF 100 OHM 1/16W 5% 0402; AGILE_PN: 470-82142; CAD_APPROVED: Yes; FPLIST: RC0402_25,RC0402_HD,RC0402_X2,0402_CC; HEIGHT: 0.45MM; MFG_NAME01: SMEC; MFG_PN01: RC73L2Z101JTF; ROHS: Yes; Temp Range: -55°C to +175°C; Tolerance: 5%
R1401 R1420 = RES: RES MF 1.0K 1/16W 5% 0402; AGILE_PN: 470-75555; ASSY_OPT: DNP; CAD_APPROVED: Yes; FPLIST: RC0402_25,RC0402_HD,RC0402_X2,0402_CC,CAPC0402_L; HEIGHT: 0.41mm; MFG_NAME01: VISHAY INTERTECHNOLOGY; MFG_PN01: CRCW04021K00JNED; ROHS: Yes; Tolerance: 5%
R1402 = RES: RES MF 4.7K 1/16W 5% 0402; AGILE_PN: 470-75626; CAD_APPROVED: Yes; FPLIST: RC0402_25,RC0402_HD,0402_CC,RC0402_X2; HEIGHT: 0.41mm; MFG_NAME01: NIC COMPONENTS CORP; MFG_PN01: NRCL04J472TRF; ROHS: Yes; Tolerance: 5%
R1403 R1404 = RES: RES MF 4.7K 1/16W 5% 0402; AGILE_PN: 470-75626; ASSY_OPT: DNP; CAD_APPROVED: Yes; FPLIST: RC0402_25,RC0402_HD,0402_CC,RC0402_X2; HEIGHT: 0.41mm; MFG_NAME01: NIC COMPONENTS CORP; MFG_PN01: NRCL04J472TRF; ROHS: Yes; Tolerance: 5%
R1405-R1408 = RES: RES MF 2.2K 1/16W 5% 0402; AGILE_PN: 470-76602; CAD_APPROVED: Yes; FPLIST: RC0402_25,RC0402_HD,0402_CC; HEIGHT: 0.4 MM; MFG_NAME01: YAGEO AMERICA; MFG_PN01: RC0402JR-072K2L; RATING: 1/16W; ROHS: Yes; Tolerance: 5%
R1423-R1425 = RES: RES MF 330 OHM 1/16W 5% 0402; AGILE_PN: 470-82124; CAD_APPROVED: Yes; FPLIST: RC0402_25,RC0402_HD,0402_CC; HEIGHT: 0.4MM; MFG_NAME01: NIC COMPONENTS CORP; MFG_PN01: NRCL04J331TRF; ROHS: Yes; Temp Range: -55 ~ +155; Tolerance: 5%
R1429 R1438 R1439 = RES: RES MF 1.0K 1/16W 5% 0402; AGILE_PN: 470-75555; CAD_APPROVED: Yes; FPLIST: RC0402_25,RC0402_HD,RC0402_X2,0402_CC,CAPC0402_L; HEIGHT: 0.41mm; MFG_NAME01: VISHAY INTERTECHNOLOGY; MFG_PN01: CRCW04021K00JNED; ROHS: Yes; Tolerance: 5%
R1431 R1432 = RES: RES MF 100K 1/16W 5% 0402; AGILE_PN: 470-75597; ASSY_OPT: DNP; CAD_APPROVED: Yes; FPLIST: RC0402_25,RC0402_HD,0402_CC; HEIGHT: 0.40 MM; MFG_NAME01: VENKEL COMPANY; MFG_PN01: CR0402-16W-104JT; ROHS: Yes; Temp Range: -55C to +155C; Temp_Range: -55C to +155C; Tolerance: 5%; VOLTAGE: 50V
R1436 R1437 = RES: RES MF 100K 1/16W 5% 0402; AGILE_PN: 470-75597; CAD_APPROVED: Yes; FPLIST: RC0402_25,RC0402_HD,0402_CC; HEIGHT: 0.40 MM; MFG_NAME01: VENKEL COMPANY; MFG_PN01: CR0402-16W-104JT; ROHS: Yes; Temp Range: -55C to +155C; Temp_Range: -55C to +155C; Tolerance: 5%; VOLTAGE: 50V
R1440 R1441 R1446 R1447 = RES: RES MF 187K 1/16W 1% 0402; AGILE_PN: 470-31090; CAD_APPROVED: Yes; FPLIST: RC0402_25,RC0402_HD,0402_CC; HEIGHT: 0.40 MM; MFG_NAME01: WALSIN TECHNOLOGY CORP.; MFG_PN01: WR04X1873FTL; ROHS: Yes; Temp Range: -55C to +155C; Temp_Range: -55C to +155C; Tolerance: 1%; VOLTAGE: 50V
SW1401 SW1402 = SW_PB_ESW: SW SPST NO TACTILE 50mA 12V SMT; 3D_Mechanical_Footprint_File: ftp://fcl.am.freescale.net/ALLEGRO/step/sw4_spst_4p6x2p8_sm.STEP; AGILE_PN: 510-78339; CAD_APPROVED: Yes; HEIGHT: 1.9MM; MFG_NAME01: E SWITCH; Package Size: 4.6x2.8x1.9mm; ROHS: Yes; Temp Range: -40 to +85C
TP45 = TESTLOOP: TEST POINT PAD 50MIL DIA SMT, NO PART TO ORDER; AGILE_PN: 211-76644; CAD_APPROVED: Yes; HEIGHT: 0.1MM; MFG_NAME01: NOTACOMPONENT; MFG_PN01: NOTACOMPONENT; ROHS: Yes
TP1401 = TESTLOOP: TEST POINT PAD 0.5MM DIA SMT, NO PART TO ORDER; AGILE_PN: 211-77484; ASSY_OPT: DNP; CAD_APPROVED: Yes; HEIGHT: 0.1MM; ROHS: Yes
TP1402-TP1404 = TESTLOOP: TEST POINT PAD 036-018MIL TH, NO PART TO ORDER; AGILE_PN: 280-76691; CAD_APPROVED: Yes; HEIGHT: 0.127MM; MFG_NAME01: NA; MFG_PN01: NO PART TO ORDER1; ROHS: Yes
U58 = AP22816_SOT25_5P: IC USB PWR SW 3A 2.7-5.5V SOT25; 3D_Mechanical_Footprint_File: ftp://fcl.am.freescale.net/ALLEGRO/step/sot25.step; AGILE_PN: TMP-CIP-12027; CAD_APPROVED: Yes; HEIGHT: 1.4MM; MFG_NAME01: DIODES INC; MFG_PN01: AP22814AW5-7; PRE_APN: 315-83844; Package Size: SC-74A, SOT-753; ROHS: Yes; Supply Voltage: Not Required; Temp Range: -40°C to + 85°C; VOLTAGE: 2.7-5.5V
U1401 = LSM6DSO_LGA14P: IC 3D ACCELEROMETER GYRO 1.71-3.6V LGA14; 3D_Mechanical_Footprint_File: ftp://fcl.am.freescale.net/ALLEGRO/step/lga14_0p5_3x2p5.STEP; AGILE_PN: 312-82731; CAD_APPROVED: Yes; HEIGHT: 0.86MM; MFG_NAME01: ST MICROELECTRONICS; Package Size: LGA-14L; ROHS: Yes; Temp Range: -40°C to 85°C
U1714 = AP22818AKB: IC USB POWER SWITCH 2A 2.7-5.5V TSOT25; 3D_Mechanical_Footprint_File: ftp://fcl.am.freescale.net/ALLEGRO/step/sot23-5.STEP; AGILE_PN: 315-83467; CAD_APPROVED: Yes; HEIGHT: 1MM; MFG_NAME01: DIODES INC; MFG_PN01: AP22818AKBWT-7; ROHS: Yes; Temp Range: -40°C to +85°C; VOLTAGE: 2.7-5.5V

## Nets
GND: C10.2 C38.2 C201.2 C202.2 C203.2 C204.2 C205.2 C206.2 C207.2 C208.2 C209.2 C210.2 C211.2 C212.2 C213.2 C214.2 C215.2 C216.2 C217.2 C218.2 C219.2 C220.2 C221.2 C222.2 C701.1 C702.1 C703.2 C704.2 C705.2 C706.2 C707.2 C708.2 C709.1 C710.2 C711.2 C712.1 C713.1 C714.2 C715.2 C716.2 C717.2 C718.1 C719.2 C720.2 C721.1 C722.2 C723.2 C724.1 C725.2 C726.2 C727.2 C728.2 C729.2 C730.2 C731.2 C930.2 C1401.2 C1402.2 C1403.2 C1404.2 C1405.2 C1406.2 C1407.2 C1410.2 C1411.2 C1412.2 C1413.2 C1414.2 C1789.2 J1401.6(B3) J1401.9(A5) J1401.14(B7) J1401.20(B10) J1401.25(A13) J1401.30(B15) J1401.34(B17) J1401.39(A20) J1403.5(A3) J1403.6(B3) J1406.7(A4) J1406.8(B4) Q1401.2(SOURCE) Q1402.2(SOURCE) Q1403.2(SOURCE) R14.2 R201.2 R204.2 R207.1 R208.1 R303.2 R718.2 R1409.1 R1410.1 R1412.1 R1433.2 R1434.2 R1435.2 R1436.2 R1437.2 R1446.2 R1447.2 R1448.2 R1824.2 SW1401.1(A1) SW1401.2(A2) SW1402.1(A1) SW1402.2(A2) U58.2(GND) U201.A3(VSS) U201.A10(VSS) U201.AB3(VSS) U201.AB5(VSS) U201.AB8(VSS) U201.AB10(VSS) U201.C1(VSS) U201.C5(VSS) U201.C8(VSS) U201.C12(VSS) U201.D2(VSS) U201.D4(VSS) U201.D9(VSS) U201.D11(VSS) U201.E1(VSS) U201.E5(VSS) U201.E8(VSS) U201.E12(VSS) U201.G1(VSS) U201.G3(VSS) U201.G5(VSS) U201.G8(VSS) U201.G10(VSS) U201.G12(VSS) U201.J1(VSS) U201.J3(VSS) U201.J10(VSS) U201.J12(VSS) U201.K2(VSS) U201.K4(VSS) U201.K9(VSS) U201.K11(VSS) U201.N2(VSS) U201.N4(VSS) U201.N9(VSS) U201.N11(VSS) U201.P1(VSS) U201.P3(VSS) U201.P10(VSS) U201.P12(VSS) U201.T1(VSS) U201.T3(VSS) U201.T5(VSS) U201.T8(VSS) U201.T10(VSS) U201.T12(VSS) U201.V1(VSS) U201.V5(VSS) U201.V8(VSS) U201.V12(VSS) U201.W2(VSS) U201.W4(VSS) U201.W9(VSS) U201.W11(VSS) U201.Y1(VSS) U201.Y5(VSS) U201.Y8(VSS) U201.Y12(VSS) U701.5(AGND) U701.43(BUCK_AGND) U701.57(EPAD) U1401.6(GND1) U1401.7(GND2) U1714.2(GND) ; also on sheet 1 4 5 6 7 8 9 10 11 12 16 21 22 23
VBUS1_DET_3V3: R301.1 U101.B3(USB1_VBUS)
VDD_1V8: C201.1 C202.1 C203.1 C204.1 C205.1 C209.1 C719.1 C720.1 J1405.1(A1) L705.2 R64.2 R65.2 R1441.1 TP707.1(TP) U201.F1(VDD1) U201.F12(VDD1) U201.G4(VDD1) U201.G9(VDD1) U201.T4(VDD1) U201.T9(VDD1) U201.U1(VDD1) U201.U12(VDD1) U701.14(BUCK5FB) ; also on sheet 5 6 7 8 9 12 16 21 23
VDD_3V3: C714.1 C715.1 C724.2 C1401.1 C1403.1 C1404.1 C1412.1 C1789.1 J1406.1(A1) J1406.2(B1) L704.2 R306.1 R307.1 R308.1 R309.1 R705.1 R1402.1 R1403.1 R1404.1 R1405.1 R1406.1 R1407.1 R1408.1 R1420.1 R1440.1 R1827.1 TP706.1(TP) U701.21(BUCK4FB) U701.22(SWIN) U1401.5(VDDIO) U1401.8(VDD) U1714.3(IN) ; also on sheet 5 6 7 8 9 10 11 12 16 21 22 23
VDD_5V: C930.1 D1402.2(ANODE) U58.5(IN) ; also on sheet 6 9 10 11 22
VDD_ANA_0V8: R871.2 TP712.1(TP) ; also on sheet 16
VDD_SOC_0V85: C707.1 C708.1 L702.2 R701.1 R709.1 R711.2 TP703.1(TP) ; also on sheet 16
VINT: C706.1 U701.4(VINT)
ADC_IN0: C1413.1 R1442.2 ; also on sheet 1
ADC_IN1: C1414.1 R1444.2 ; also on sheet 1
DRAM_CA0_A: TP219.1(Pin1) U101.F1(DRAM_CA0_A) U201.H2(CA0_A)
DRAM_CA1_A: U101.E2(DRAM_CA1_A) U201.J2(CA1_A)
DRAM_CA2_A: U101.D2(DRAM_CA2_A) U201.H9(CA2_A)
DRAM_CA3_A: U101.C1(DRAM_CA3_A) U201.H10(CA3_A)
DRAM_CA4_A: U101.B2(DRAM_CA4_A) U201.H11(CA4_A)
DRAM_CA5_A: U101.A2(DRAM_CA5_A) U201.J11(CA5_A)
DRAM_CK_C_A: R205.2 U101.B1(DRAM_CK_C_A) U201.J9(CK_c_A)
DRAM_CK_T_A: R205.1 U101.C2(DRAM_CK_T_A) U201.J8(CK_t_A)
DRAM_CKE0_A: R207.2 U101.G1(DRAM_CKE0_A) U201.J4(CKE0_A)
DRAM_CKE1_A: R208.2 U101.F2(DRAM_CKE1_A) U201.J5(CKE1_A)
DRAM_DATA0_A: TP206.1(Pin1) U101.L2(DRAM_DQ00_A) U201.F4(DQ4_A)
DRAM_DATA1_A: TP207.1(Pin1) U101.L1(DRAM_DQ01_A) U201.E4(DQ5_A)
DRAM_DATA2_A: TP208.1(Pin1) U101.K2(DRAM_DQ02_A) U201.C4(DQ6_A)
DRAM_DATA3_A: TP209.1(Pin1) U101.K1(DRAM_DQ03_A) U201.B4(DQ7_A)
DRAM_DATA4_A: TP202.1(Pin1) U101.J1(DRAM_DQ04_A) U201.B2(DQ0_A)
DRAM_DATA5_A: TP203.1(Pin1) U101.H2(DRAM_DQ05_A) U201.C2(DQ1_A)
DRAM_DATA6_A: TP204.1(Pin1) U101.H1(DRAM_DQ06_A) U201.E2(DQ2_A)
DRAM_DATA7_A: TP205.1(Pin1) U101.G2(DRAM_DQ07_A) U201.F2(DQ3_A)
DRAM_DATA8_A: TP212.1(Pin1) U101.T2(DRAM_DQ08_A) U201.E11(DQ10_A)
DRAM_DATA9_A: TP213.1(Pin1) U101.U2(DRAM_DQ09_A) U201.F11(DQ11_A)
DRAM_DATA10_A: TP211.1(Pin1) U101.T1(DRAM_DQ10_A) U201.C11(DQ9_A)
DRAM_DATA11_A: TP210.1(Pin1) U101.R2(DRAM_DQ11_A) U201.B11(DQ8_A)
DRAM_DATA12_A: TP216.1(Pin1) U101.N1(DRAM_DQ12_A) U201.C9(DQ14_A)
DRAM_DATA13_A: TP217.1(Pin1) U101.N2(DRAM_DQ13_A) U201.B9(DQ15_A)
DRAM_DATA14_A: TP215.1(Pin1) U101.M2(DRAM_DQ14_A) U201.E9(DQ13_A)
DRAM_DATA15_A: TP214.1(Pin1) U101.M1(DRAM_DQ15_A) U201.F9(DQ12_A)
DRAM_DMI0_A: TP201.1(Pin1) U101.J2(DRAM_DMI0_A) U201.C3(DMI0_A)
DRAM_DMI1_A: U101.R1(DRAM_DMI1_A) U201.C10(DMI1_A)
DRAM_nCS0_A: TP218.1(Pin1) U101.D1(DRAM_CS0_A) U201.H4(CS0_A)
DRAM_nCS1_A: U101.E1(DRAM_CS1_A) U201.H3(CS1_A)
DRAM_nRESET: R102.1 R201.1 U101.F4(DRAM_RESET_N) U201.T11(RESET_N)
DRAM_SDQS0_C_A: U101.K4(DRAM_DQS0_C_A) U201.E3(DQS0_c_A)
DRAM_SDQS0_T_A: U101.M4(DRAM_DQS0_T_A) U201.D3(DQS0_t_A)
DRAM_SDQS1_C_A: U101.P2(DRAM_DQS1_C_A) U201.E10(DQS1_c_A)
DRAM_SDQS1_T_A: U101.P1(DRAM_DQS1_T_A) U201.D10(DQS1_t_A)
DRAM_ZN: R204.1 U101.H4(DRAM_ZQ)
DRAM_ZQ0: R209.2 U201.A5(ZQ0)
ENET1_MDC: U101.T8(ENET1_MDC) ; also on sheet 8
ENET1_MDIO: U101.U7(ENET1_MDIO) ; also on sheet 8
ENET1_RD0: U101.U5(ENET1_RD0) ; also on sheet 8
ENET1_RD1: U101.T6(ENET1_RD1) ; also on sheet 8
ENET1_RD2: U101.U6(ENET1_RD2) ; also on sheet 8
ENET1_RD3: U101.T7(ENET1_RD3) ; also on sheet 8
ENET1_RX_CTL: U101.T5(ENET1_RX_CTL) ; also on sheet 8
ENET1_RXC: U101.U4(ENET1_RXC) ; also on sheet 8
ENET1_TD0: TP221.1(Pin1) U101.U9(ENET1_TD0) ; also on sheet 8
ENET1_TD1: U101.R9(ENET1_TD1) ; also on sheet 8
ENET1_TD2: U101.U10(ENET1_TD2) ; also on sheet 8
ENET1_TD3: U101.T10(ENET1_TD3) ; also on sheet 8
ENET1_TX_CTL: U101.T9(ENET1_TX_CTL) ; also on sheet 8
ENET1_TXC: TP220.1(Pin1) U101.U8(ENET1_TXC) ; also on sheet 8
EXP3V3_EN: R1825.1 ; also on sheet 12
EXP5V_EN: R16.1 ; also on sheet 12
EXP_3V3: C1402.1 C1405.1 L1401.1 U1714.1(OUT1) U1714.5(OUT2)
EXP_5V: C38.1 C1406.1 C1407.1 L1402.2 U58.1(OUT)
EXP_GPIO_IO08: J1401.24(B12) ; also on sheet 12
EXP_GPIO_IO09: J1401.21(A11) ; also on sheet 12
EXP_GPIO_IO10: J1401.19(A10) ; also on sheet 12
EXP_GPIO_IO11: J1401.23(A12) ; also on sheet 12
EXP_GPIO_IO12: J1401.32(B16) R1438.1 ; also on sheet 12
EXP_GPIO_IO16: R856.2 R1829.1 ; also on sheet 12
EXP_GPIO_IO17: J1401.11(A6) ; also on sheet 12
EXP_GPIO_IO18: R855.2 R1829.2 ; also on sheet 12
EXP_GPIO_IO19: J1401.35(A18) R745.2 ; also on sheet 12
EXP_GPIO_IO20: J1401.38(B19) ; also on sheet 12
EXP_GPIO_IO21: J1401.40(B20) ; also on sheet 12
GPIO_IO00: J1401.27(A14) R1415.2 U101.B16(GPIO_IO00)
GPIO_IO01: J1401.28(B14) R1417.2 U101.B17(GPIO_IO01)
GPIO_IO02: J1401.3(A2) R1414.2 U101.C16(GPIO_IO02)
GPIO_IO03: J1401.5(A3) R1416.2 U101.C17(GPIO_IO03)
GPIO_IO04: J1401.7(A4) R1429.1 U101.D16(GPIO_IO04)
GPIO_IO05: J1401.29(A15) U101.D17(GPIO_IO05)
GPIO_IO06: J1401.31(A16) U101.E16(GPIO_IO06)
GPIO_IO07: J1401.26(B13) U101.E17(GPIO_IO07)
GPIO_IO08: U101.K14(GPIO_IO08) ; also on sheet 12
GPIO_IO09: U101.F16(GPIO_IO09) ; also on sheet 12
GPIO_IO10: U101.F17(GPIO_IO10) ; also on sheet 12
GPIO_IO11: U101.G16(GPIO_IO11) ; also on sheet 12
GPIO_IO12: U101.F14(GPIO_IO12) ; also on sheet 12
GPIO_IO13: J1401.33(A17) R1439.1 U101.G17(GPIO_IO13)
GPIO_IO14: J1401.8(B4) U101.H16(GPIO_IO14)
GPIO_IO15: J1401.10(B5) U101.H17(GPIO_IO15)
GPIO_IO16: U101.J16(GPIO_IO16) ; also on sheet 12
GPIO_IO17: U101.K15(GPIO_IO17) ; also on sheet 12
GPIO_IO18: U101.M14(GPIO_IO18) ; also on sheet 12
GPIO_IO19: U101.J17(GPIO_IO19) ; also on sheet 12
GPIO_IO20: U101.K16(GPIO_IO20) ; also on sheet 12
GPIO_IO21: U101.K17(GPIO_IO21) ; also on sheet 12
I2C1_SCL: R163.2 R307.2 R717.1 R1443.1 U101.A12(I2C1_SCL) ; also on sheet 6 7 10 12
I2C1_SCLL: R65.1 R713.2 ; also on sheet 7
I2C1_SDA: R164.2 R306.2 R719.1 R1445.1 U101.B12(I2C1_SDA) ; also on sheet 6 7 10 12
I2C1_SDAL: R64.1 R712.2 ; also on sheet 7
I2C2_SCL: R309.2 R714.1 U101.A11(I2C2_SCL) ; also on sheet 12
I2C2_SDA: R308.2 R715.1 U101.B11(I2C2_SDA) ; also on sheet 12
I2C3_SCL: R1405.2 R1413.1 R1417.1 ; also on sheet 10
I2C3_SDA: R1406.2 R1411.1 R1415.1 ; also on sheet 10
I2C4_SCL: R1407.2 R1416.1 ; also on sheet 10
I2C4_SDA: R1408.2 R1414.1 ; also on sheet 10
I3C1_SCL: R163.1 R1404.2 R1413.2 U1401.13(SCL) ; also on sheet 22
I3C1_SDA: R164.1 R1401.2 R1403.2 R1411.2 U1401.14(SDA) ; also on sheet 22
I3C_PUR: R1401.1 TP1401.1(Pin1)
IMU_INT1: D1401.A(ANODE) ; also on sheet 12
IOEXP_IO22: R854.1
IOEXP_IO23: R853.2
IOEXP_IO24: J1401.18(B9) ; also on sheet 12
IOEXP_IO25: J1401.22(B11) ; also on sheet 12
IOEXP_IO27: J1401.13(A7) ; also on sheet 12
LED_B: Q1401.3(DRAIN) R1424.2
LED_G: Q1402.3(DRAIN) R1423.2
LED_R: Q1403.3(DRAIN) R1425.2
LPD4/x_VDD2_1V1: C206.1 C207.1 C208.1 C210.1 C211.1 C212.1 C213.1 C214.1 C722.1 C723.1 L706.2 R210.1 R702.1 TP708.1(TP) U201.A4(VDD2) U201.A9(VDD2) U201.AB4(VDD2) U201.AB9(VDD2) U201.F5(VDD2) U201.F8(VDD2) U201.H1(VDD2) U201.H5(VDD2) U201.H8(VDD2) U201.H12(VDD2) U201.K1(VDD2) U201.K3(VDD2) U201.K10(VDD2) U201.K12(VDD2) U201.N1(VDD2) U201.N3(VDD2) U201.N10(VDD2) U201.N12(VDD2) U201.R1(VDD2) U201.R5(VDD2) U201.R8(VDD2) U201.R12(VDD2) U201.U5(VDD2) U201.U8(VDD2) U701.52(BUCK6FB) ; also on sheet 16
LPD4/x_VDDQ_0V6: C215.1 C216.1 C217.1 C218.1 C219.1 C220.1 C221.1 C222.1 R209.1 R211.2 R702.2 R704.2 TP702.1(TP) U201.AA3(VDDQ) U201.AA5(VDDQ) U201.AA8(VDDQ) U201.AA10(VDDQ) U201.B3(VDDQ) U201.B5(VDDQ) U201.B8(VDDQ) U201.B10(VDDQ) U201.D1(VDDQ) U201.D5(VDDQ) U201.D8(VDDQ) U201.D12(VDDQ) U201.F3(VDDQ) U201.F10(VDDQ) U201.U3(VDDQ) U201.U10(VDDQ) U201.W1(VDDQ) U201.W5(VDDQ) U201.W8(VDDQ) U201.W12(VDDQ) ; also on sheet 16
LPD4x_VDDQ_0V6: C703.1 C705.1 L701.2 R704.1 U701.44(R_SNSP2)
NVCC_BBSM_1V8: C727.1 J1403.1(A1) J1403.2(B1) R703.1 R1431.1 R1432.1 TP709.1(TP) U701.3(LDO1) ; also on sheet 1 16
NVCC_SD2: C731.1 R310.1 R311.1 R312.1 TP713.1(TP) U701.55(LDO5) ; also on sheet 16 21
ODT_CA_A: R210.2 U201.G2(ODT_CA_A)
ONOFF: C1411.1 R1426.2 ; also on sheet 1 5
PDM_CLK: U101.A16(PDM_CLK) ; also on sheet 23
PDM_DATA0: U101.A10(PDM_BIT_STREAM0) ; also on sheet 23
PDM_DATA1: U101.B10(PDM_BIT_STREAM1) ; also on sheet 23
PMIC_32K_OUT: U701.7(CLK_32K_OUT) ; also on sheet 1 7
PMIC_nINT: U701.13(IRQ_B) ; also on sheet 12
PMIC_ON_REQ: R707.1 ; also on sheet 1 5 11
PMIC_STBY_REQ: R708.1 ; also on sheet 1 5
POR_B: U701.9(POR_B) ; also on sheet 1 5 12
SAI1_RXD0: U101.B14(SAI1_RXD0) ; also on sheet 7
SAI1_TXC: U101.B15(SAI1_TXC) ; also on sheet 7
SAI1_TXD0: U101.A15(SAI1_TXD0) ; also on sheet 7 23
SAI1_TXFS: U101.A14(SAI1_TXFS) ; also on sheet 7 23
SD1_CLK: U101.U11(SD1_CLK) ; also on sheet 21
SD1_CMD: U101.T11(SD1_CMD) ; also on sheet 21
SD1_DATA0: U101.T13(SD1_DATA0) ; also on sheet 21
SD1_DATA1: U101.T14(SD1_DATA1) ; also on sheet 21
SD1_DATA2: U101.T15(SD1_DATA2) ; also on sheet 21
SD1_DATA3: U101.U13(SD1_DATA3) ; also on sheet 21
SD1_DATA4: U101.T12(SD1_DATA4) ; also on sheet 21
SD1_DATA5: U101.U14(SD1_DATA5) ; also on sheet 21
SD1_DATA6: U101.U15(SD1_DATA6) ; also on sheet 21
SD1_DATA7: U101.U16(SD1_DATA7) ; also on sheet 21
SD1_STROBE: U101.U12(SD1_STROBE) ; also on sheet 21
SD2_CLK: U101.M16(SD2_CLK) ; also on sheet 21
SD2_CMD: R311.2 U101.M17(SD2_CMD) ; also on sheet 21
SD2_DATA0: R310.2 U101.N17(SD2_DATA0) ; also on sheet 21
SD2_DATA1: U101.N16(SD2_DATA1) ; also on sheet 21
SD2_DATA2: U101.L17(SD2_DATA2) ; also on sheet 21
SD2_DATA3: U101.L16(SD2_DATA3) ; also on sheet 21
SD2_nCD: U101.P12(SD2_CD_B) ; also on sheet 21
SD2_nRST: R312.2 R723.2 U101.P10(SD2_RESET_B)
SD2_VSEL: U101.P14(SD2_VSELECT) U701.29(SD_VSEL)
SD3_CLK: U101.T16(SD3_CLK) ; also on sheet 7
SD3_CMD: U101.T17(SD3_CMD) ; also on sheet 7
SD3_DATA0: U101.R16(SD3_DATA0) ; also on sheet 7
SD3_DATA1: U101.R17(SD3_DATA1) ; also on sheet 7
SD3_DATA2: U101.P16(SD3_DATA2) ; also on sheet 7
SD3_DATA3: U101.P17(SD3_DATA3) ; also on sheet 7
STAR_I2C_SCL: J1406.3(A2) J1406.4(B2) R1443.2
STAR_I2C_SDA: J1406.5(A3) J1406.6(B3) R1445.2
SYS_nRST: C1410.1 R706.1 R1427.2 TP915.1(TP) ; also on sheet 5 22
TAMPER0: J1403.3(A2) R1431.2 R1436.1 ; also on sheet 1
TAMPER1: J1403.4(B2) R1432.2 R1437.1 ; also on sheet 1
UART1_RXD: U101.B13(UART1_RXD) ; also on sheet 5 22
UART1_TXD: U101.A13(UART1_TXD) ; also on sheet 5 22 23
UART2_RXD: U101.D14(UART2_RXD) ; also on sheet 5 22
UART2_TXD: U101.D12(UART2_TXD) ; also on sheet 5 22 23
USB1_DN: U101.A4(USB1_D_N) ; also on sheet 9 22
USB1_DP: U101.B4(USB1_D_P) ; also on sheet 9 22
USB1_ID: U101.D4(USB1_ID) ; also on sheet 9
USB1_VBUS_3V3: R301.2 ; also on sheet 9
VLDO3_1V8: C729.1 TP711.1(TP) U701.54(NC_2) ; also on sheet 16
VPCIe_3V3: L1403.1 ; also on sheet 7
VRPi_3V3: J1401.1(A1) J1401.17(A9) L1401.2 L1403.2
VRPi_5V: J1401.2(B1) J1401.4(B2) L1402.1
VSD_3V3: C725.1 U701.23(SWOUT) ; also on sheet 21
VSYS_5V: C701.2 C702.2 C704.1 C709.2 C712.2 C713.2 C718.2 C721.2 C726.1 U701.16(INB45_1) U701.17(INB45_2) U701.18(INB45_3) U701.33(INB13_1) U701.34(INB13_2) U701.35(INB13_3) U701.47(INB26_1) U701.48(INB26_2) U701.49(INB26_3) U701.53(VSYS) U701.56(INL1) ; also on sheet 7 9 11 22
WDOG_B: R710.1 TP916.1(TP) U101.H14(WDOG_ANY) ; also on sheet 5
XIN_32K: C716.1 QZ701.2 R720.1 U701.10(XTAL_IN)
XOUT_32K: C717.1 QZ701.1 R720.2 U701.11(XTAL_OUT)
N112168459: R1402.2 U1401.12(CS)
N112168530: TP1402.1(Pin1) U1401.11(SDO_AUX)
N112168572: R1409.2 U1401.1(SDO/SA0)
N112168574: TP1403.1(Pin1) U1401.10(OCS_AUX)
N112168590: R1410.2 U1401.2(SDX)
N112168603: R1412.2 U1401.3(SCX)
N112168605: TP1404.1(Pin1) U1401.9(INT2)
N112168607: D1401.C(CATHODE) R1420.2 U1401.4(INT1)
N112179037: J1401.37(A19) J1710.2
N112179124: J1401.36(B18) R856.1
N112179125: J1401.12(B6) R855.1
N112179128: J1401.16(B8) R853.1
N113364863: J1405.6(B3) J1405.8(B4) R1444.1
N113365543: J1405.3(A2) R1440.2 R1446.1
N113365548: J1405.5(A3) R1441.2 R1447.1
N113409056: R1426.1 SW1401.3(B1) SW1401.4(B2)
N113409060: R1427.1 SW1402.3(B1) SW1402.4(B2)
N113526638: L701.1 U701.45(LX2_1) U701.46(LX2_2)
N113526990: L702.1 U701.36(LX1_1) U701.37(LX1_2)
N113527145: R701.2 R711.1 U701.38(R_SNSP1)
N113527183: C710.1 C711.1 L703.2 R709.2 R716.1
N113527270: L703.1 U701.31(LX3_1) U701.32(LX3_2)
N113527381: R716.2 R718.1 U701.30(R_SNSP3_CFG)
N113527504: L704.1 U701.19(LX4_1) U701.20(LX4_2)
N113527663: L705.1 U701.15(LX5)
N113527832: L706.1 U701.50(LX6_1) U701.51(LX6_2)
N113528020: R723.1 U701.12(SW_EN)
N113528254: C728.1 TP710.1(TP) U701.2(NC_1)
N113528336: C730.1 R871.1 U701.1(LDO4)
N114629076: R703.2 R706.2 U701.8(PMIC_RST_B)
N114629170: R705.2 R710.2 U701.28(WDOG_B)
N114629754: R707.2 U701.39(PMIC_ON_REQ)
N114629773: R708.2 U701.40(PMIC_STBY_REQ)
N114629886: R715.2 U701.42(SDA)
N114629887: R714.2 U701.41(SCL)
N114636326: TP714.1(TP) U701.6(RTC_RESET_B)
N114797754: D1402.4(CATHODE3) R1423.1
N114797756: D1402.3(CATHODE2) R1424.1
N114797758: D1402.1(CATHODE1) R1425.1
N114798676: Q1403.1(GATE) R1435.1 R1439.2
N114798680: Q1401.1(GATE) R1434.1 R1438.2
N114800112: Q1402.1(GATE) R1429.2 R1433.1
N115329910: J1401.15(A8) R854.2
N115331791: J1405.2(B1) J1405.4(B2) R1442.1
N115575393: R303.1 U101.A3(USB1_TXRTUNE)
N115754842: J1405.7(A4) R1448.1
N116227167: J1710.1 R745.1
N116421020: R211.1 U201.A8(ZQ1)
N116438273: R719.2 U701.24(SDAH)
N116438275: R717.2 U701.25(SCLH)
N116438398: R713.1 U701.27(SCLL)
N116438407: R712.1 U701.26(SDAL)
N116439658: R1824.1 R1825.2 U1714.4(EN)
N116441929: R1827.2 TP45.1(Pin1) U58.3(FLG)
N116441950: C10.1 R14.1 R16.2 U58.4(EN)
N116479778: R102.2 U201.G11(NC)

Not connected (* = marked no-connect by the designer): U201 A1(DNU)* A2(DNU)* A11(DNU)* A12(DNU)* AA1(DNU)* AA2(DQ0_B)* AA4(DQ7_B)* AA9(DQ15_B)* AA11(DQ8_B)* AA12(DNU)* AB1(DNU)* AB2(DNU)* AB11(DNU)* AB12(DNU)* B1(DNU)* B12(DNU)* K5(NC)* K8(NC)* N5(NC)* N8(NC)* P2(CA1_B)* P4(CKE0_B)* P5(CKE1_B)* P8(CK_t_B)* P9(CK_c_B)* P11(CA5_B)* R2(CA0_B)* R3(CS1_B)* R4(CS0_B)* R9(CA2_B)* R10(CA3_B)* R11(CA4_B)* T2(ODT_CA_B)* U2(DQ3_B)* U4(DQ4_B)* U9(DQ12_B)* U11(DQ11_B)* V2(DQ2_B)* V3(DQS0_c_B)* V4(DQ5_B)* V9(DQ13_B)* V10(DQS1_c_B)* V11(DQ10_B)* W3(DQS0_t_B)* W10(DQS1_t_B)* Y2(DQ1_B)* Y3(DMI0_B)* Y4(DQ6_B)* Y9(DQ14_B)* Y10(DMI1_B)* Y11(DQ9_B)*

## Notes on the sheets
sheet 17
- SYS PMIC
- 3A / 0.8V  DVS
- 0.6V-2.1875V / 12.5mV
- Sense from Processor power pin
- # System Reset Button
- 3A / 0.8V  DVS
- OD+PU<LDO1>
- 0.6V-2.1875V / 12.5mV
- OD
- OD
- Sense from Processor power pin
- # BUCK1&3 Dual Phase Mode
- 3A / 0.8V  DVS
- 0.6V-2.1875V / 12.5mV
- Sense connect to GND for dual phase mode
- <LDO1>
- 3A / 3.3V
- 0.6V-3.4V / 25mV
- I2C ADDR: 0x25 (010 0101x)
- Add PU if using level translator (per DS). Float if unused.
- Note:
- 2A / 1.8V
- 1. PMIC_RST_B is used as Cold Reset as default.
- 0.6V-3.4V / 25mV
- 2. WDOG_B is used as Cold Reset, external pull up is needed for BSDL mode.
- PMIC: PCA9451AHN  CFG
- 2A / 1.1V
- SEQ
- REGULATOR
- VOL (V)
- MAX I (mA)
- PWR RAIL
- TYP VOL(V)
- REQ I (mA)
- 0.6V-3.4V / 25mV
- tstep=2ms
- 1
- LDO1
- 1.8
- 10
- NVCC_BBSM_1V8
- 1.8
- 2
- -
- 400mA / 3.3V
- -
- PMIC_ON_REQ
- 2
- T1
- BUCK1/3 DP
- 0.85
- 4000
- VDD_SOC
- DVS
- Ref to DS
- 3
- T2
- LDO4
- 0.8
- 200
- VDD_ANA_0P8
  VDD_MIPI_0P8
  VDD_USB_0P8
- 0.8
- 186
- 4
- 5
- T4
- BUCK5
- 1.8
- 2000
- VDD_ANAx_1P8
  VDD_LVDS_1P8
  VDD_MIPI_1P8
  VDD_USB_1P8
  NVCC_GPIO
- 1.8
- 1040
- 10mA / 1.8V
- PERI INCLUDE
- 1.6V-1.9V
  3.0V-3.3V / 100mV
- Note:
- 6
- T5
- BUCK6
- 1.1
- 1500
- VDD2_DDR
  VDDQ_DDR (1.1V for LPD4)
- 1.1
- 676
- PIN2/54 is NC, C728/C729 just keep the compatible with previous design.
- 7
- T6
- BUCK2
- 0.6
- 2000
- VDDQ_DDR (0.6V for LPD4x)
- 0.6
- 360
- 8
- T7
- BUCK4
- 3.3
- 3000
- NVCC_GPIO
  VDD_USB_3P3
- 3.3
- 2870
- PERI INCLUDE
- 200mA / 3.3V
- 8
- T7
- Load Switch
- -
- 400
- SD_CARD (from BUCK4 )
- 3.3
- 0.8V-3.3V / 100mV
- 9
- T8
- LDO5
- 1.8/3.3
- 150
- NVCC_SD2
- 1.8/3.3
- -
- -
- 150mA / (3.3V/1.8V)
- 1.8V-3.3V / 100mV
- 12
- POR_B
- --
- --
- POR_B
sheet 18
- LPDDR4/X
- # VDD1: 1.8V /400mA
- # VDD2 : 1.1V / 600mA
- # VDDQ: (0.6V/1.1V) / 360mA
- #0.6V for LPDDR4X
- #1.1V for LPDDR4
- LPDDR4X: 2GB (x16)
- Z:85 OHM
- Z:85 OHM
- # Power Supply Voltage Sequence:
- RESET_n is held LOW.
  VDD1 >= VDD2
  VDD2 >= VDDQ-200mV
- Z:85 OHM
- Power ramp duration tINIT0 (Tb¨CTa) must not exceed 20ms.
- # ZQ1 is reserved for 2CS LPDDR4/x
- For 100-ball LPDDR4/X
sheet 19
- IMU:
- Accelerometer/Gyroscope (w/o eCompass)
- EXP
- VDD: 1.71V-3.6V
  VDD_IO: 1.62V-3.6V
- #I3C SUPPORT
- GPIO2_I2C4.SDA
- GPIO3_I2C4.SCL
- GPIO4_PDM.CLK
- GPIO14_UART3.TX
- GPIO15_UART3.RX
- GPIO17_SAI3_MCLK
- GPIO18_SAI3.RXBCLK
- GPIO27_PUSHBUTTON_INT
- GPIO22_SPDIF_IN
- GPIO23_SPDIF_OUT
- GPIO10_SPI3.SOUT
- GPIO24_DC_INT
- Default: output forced to ground
- GPIO9_SPI3.SIN
- GPIO25_DC_RESET
- GPIO11_SPI3.SCK
- GPIO8_SPI3.CS0
- GPIO7_SPI3.CS1
- GPIO00_MIC_MUTE_INT
- DC_GPIO1
- GPIO05_PDM_BITSTREAM_0
- GPIO06_PDM_BITSTREAM_1
- GPIO13_PDM_BITSTREAM_3
- GPIO12_PDM_BITSTREAM
- GPIO19_SAI3.RXSYNC
- GPIO16_SAI3.TXBCLK
- GPIO26_SAI3.TXSYNC
- GPIO20_SAI3.RXDATA0
- GPIO21_SAI3.TXDATA0
- #I2C ADDR: 0b'110101[0]x
- Default: input with pull-down
- Push-pull/open-drain selection on INT1 and INT2 pins. Default value: 0
  (0: push-pull mode; 1: open-drain mode)
- INT1 pin floating (internal pull-down): I2C/I3C both active
  INT1 pin connected to VDD_IO: only I3C active
- No TXSYNC on IMX93 9x9 chip
  When Audio Hat Board  is connected,short J1710
- 2.7 V to 5.5 V / 2A
- TAMPER
- RGB LED w/ PWM
- 2.7 V to 5.5 V / 3A
- I2C CN
- ADC x2 CH
- # Prevent PWR SEQ violation from ADC port
- Buttons
sheet 20
- i.MX9D IO/PHY
- #eMMC
- #ENET1
- #M.2
- USB Z:90 OHM
- #USB1 C DRP
- #MicroSD
- PHY
- Note:
- If USB connector is MicroAB or MicroB, USBx_VBUS MUST not connect directly to the 5V VBUS voltage
  of connector. Instead, this pin must be isloated with an external 30K 1% resistor.
- I3C
- #RPi 40P
- External PU is necessary for SD2_RESET_B to enable SD card power as default!
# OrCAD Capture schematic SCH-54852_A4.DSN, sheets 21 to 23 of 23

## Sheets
21 C-08 eMMC/MicroSD: size C
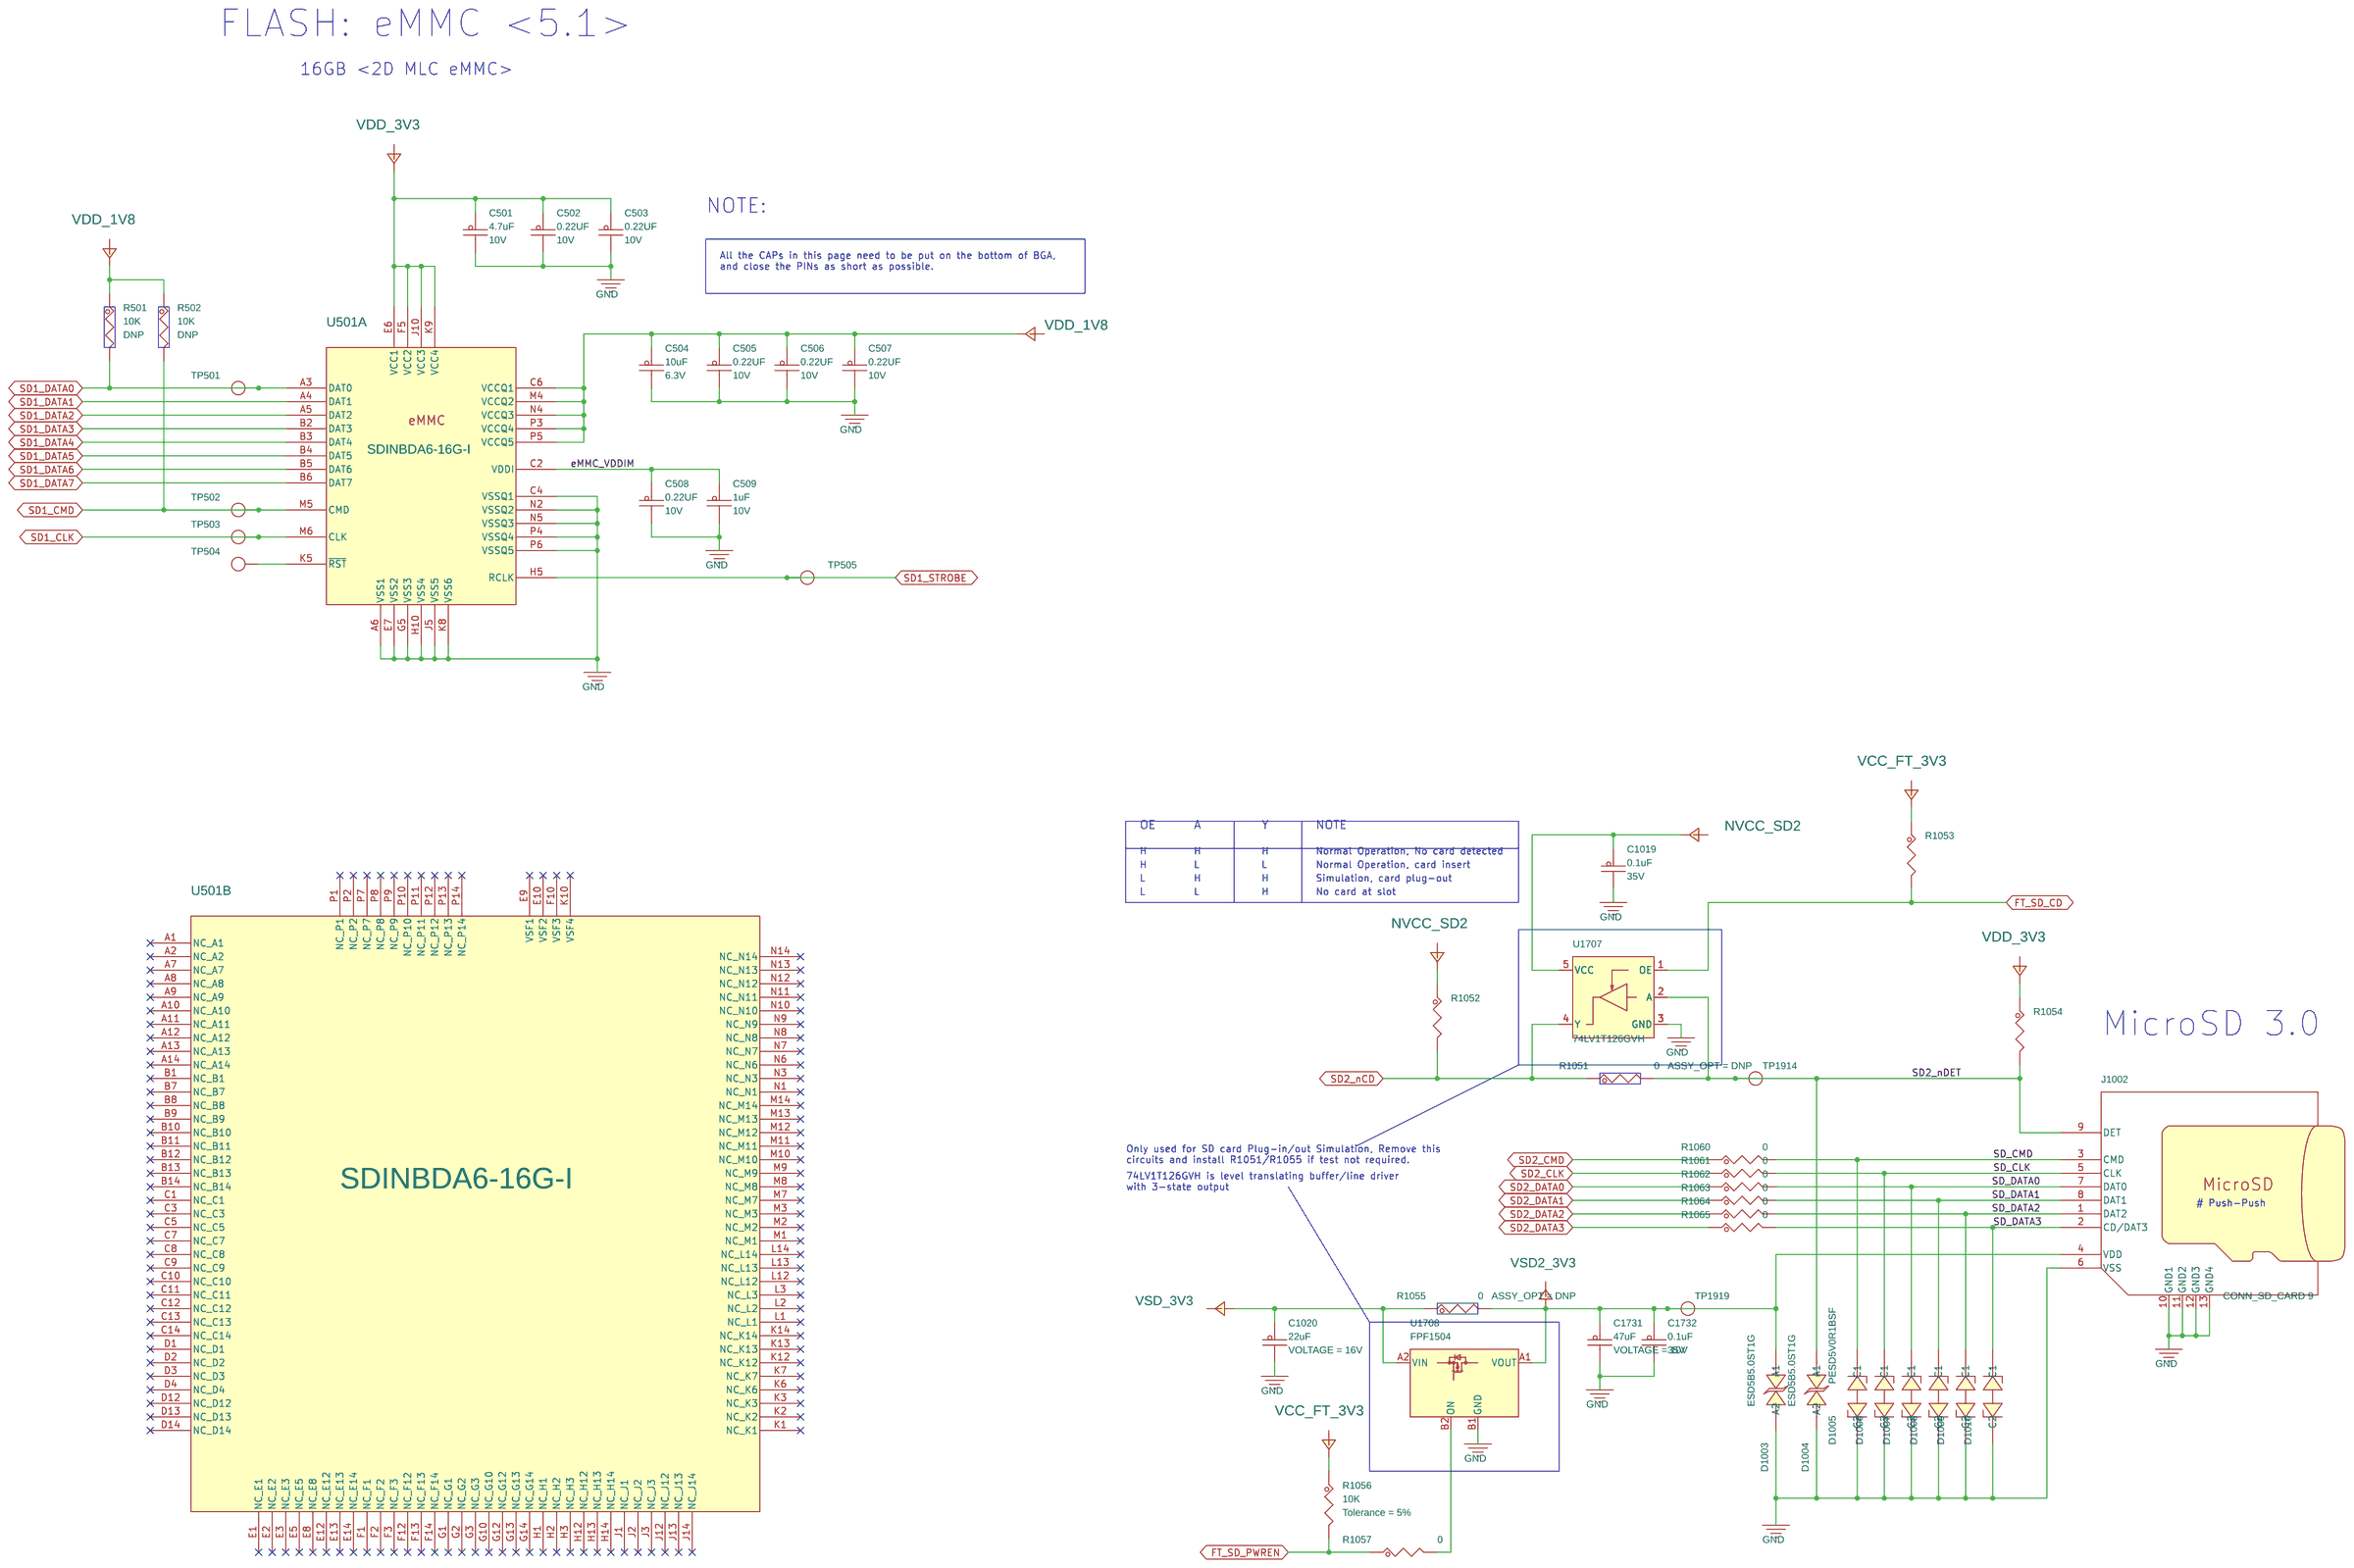
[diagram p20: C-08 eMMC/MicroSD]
22 C-17 CAN/Ext RTC: size C
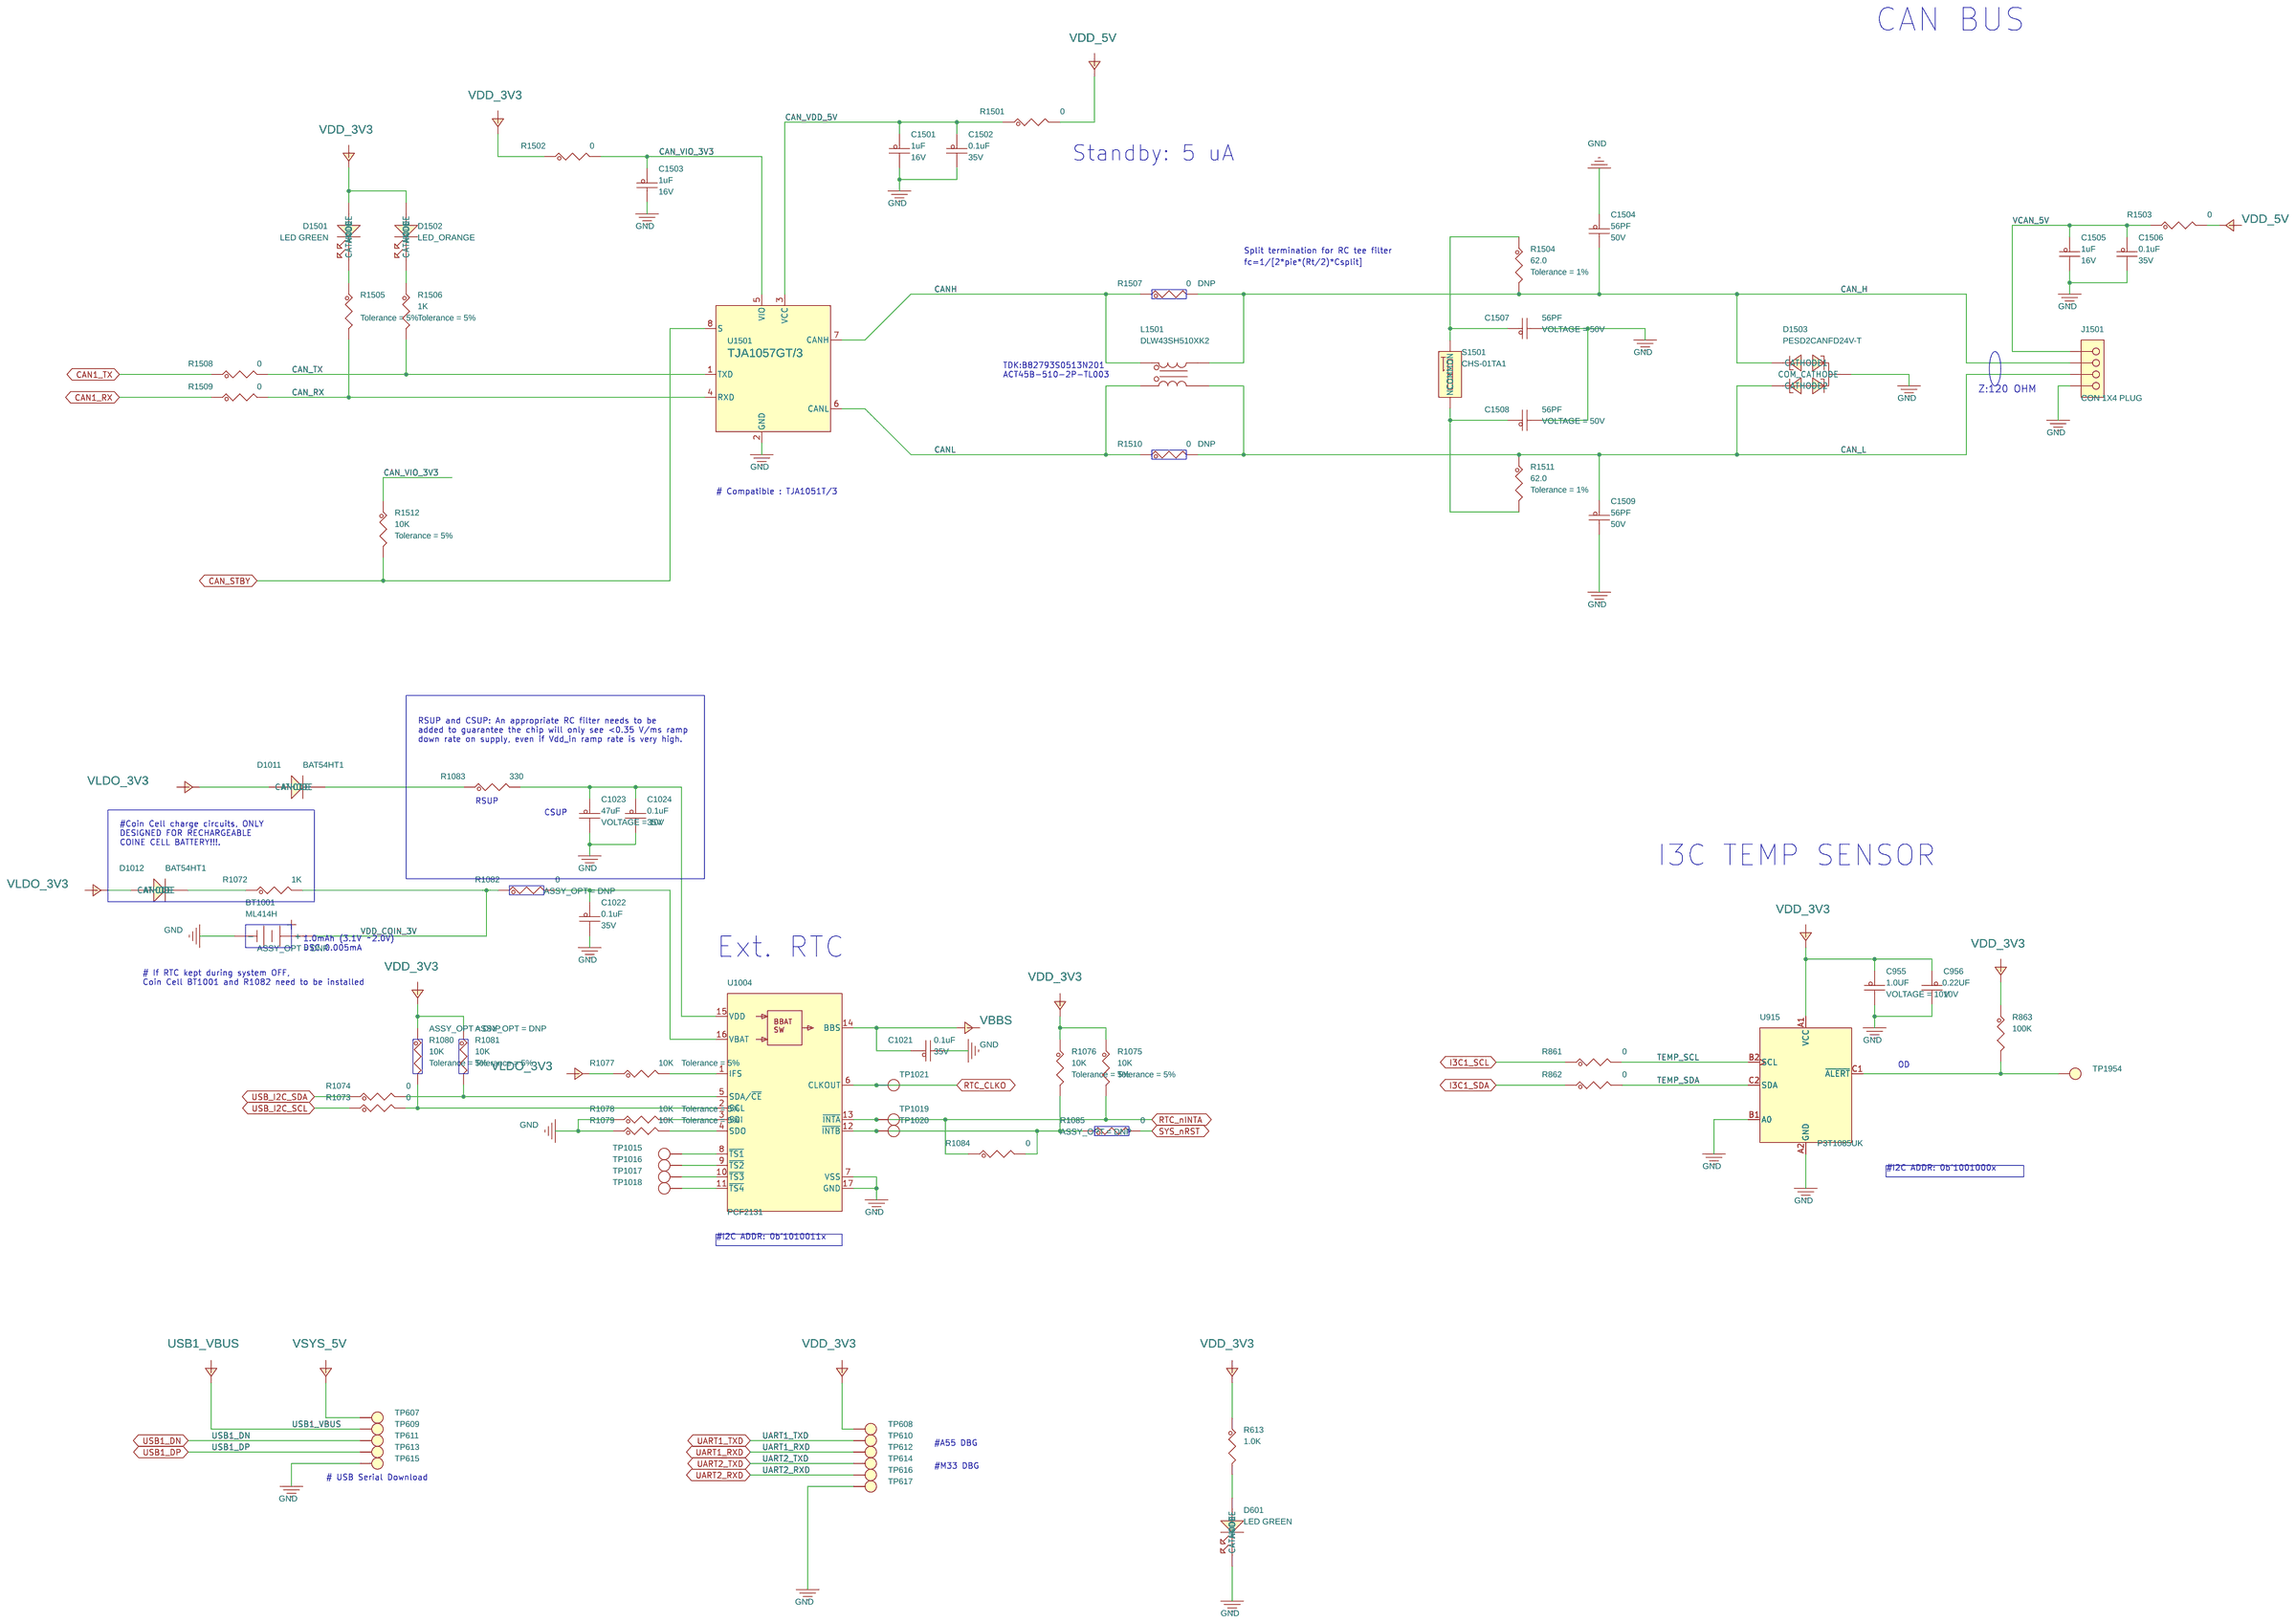
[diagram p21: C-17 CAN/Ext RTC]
23 C-19 BOOT CFG/PDM: size C

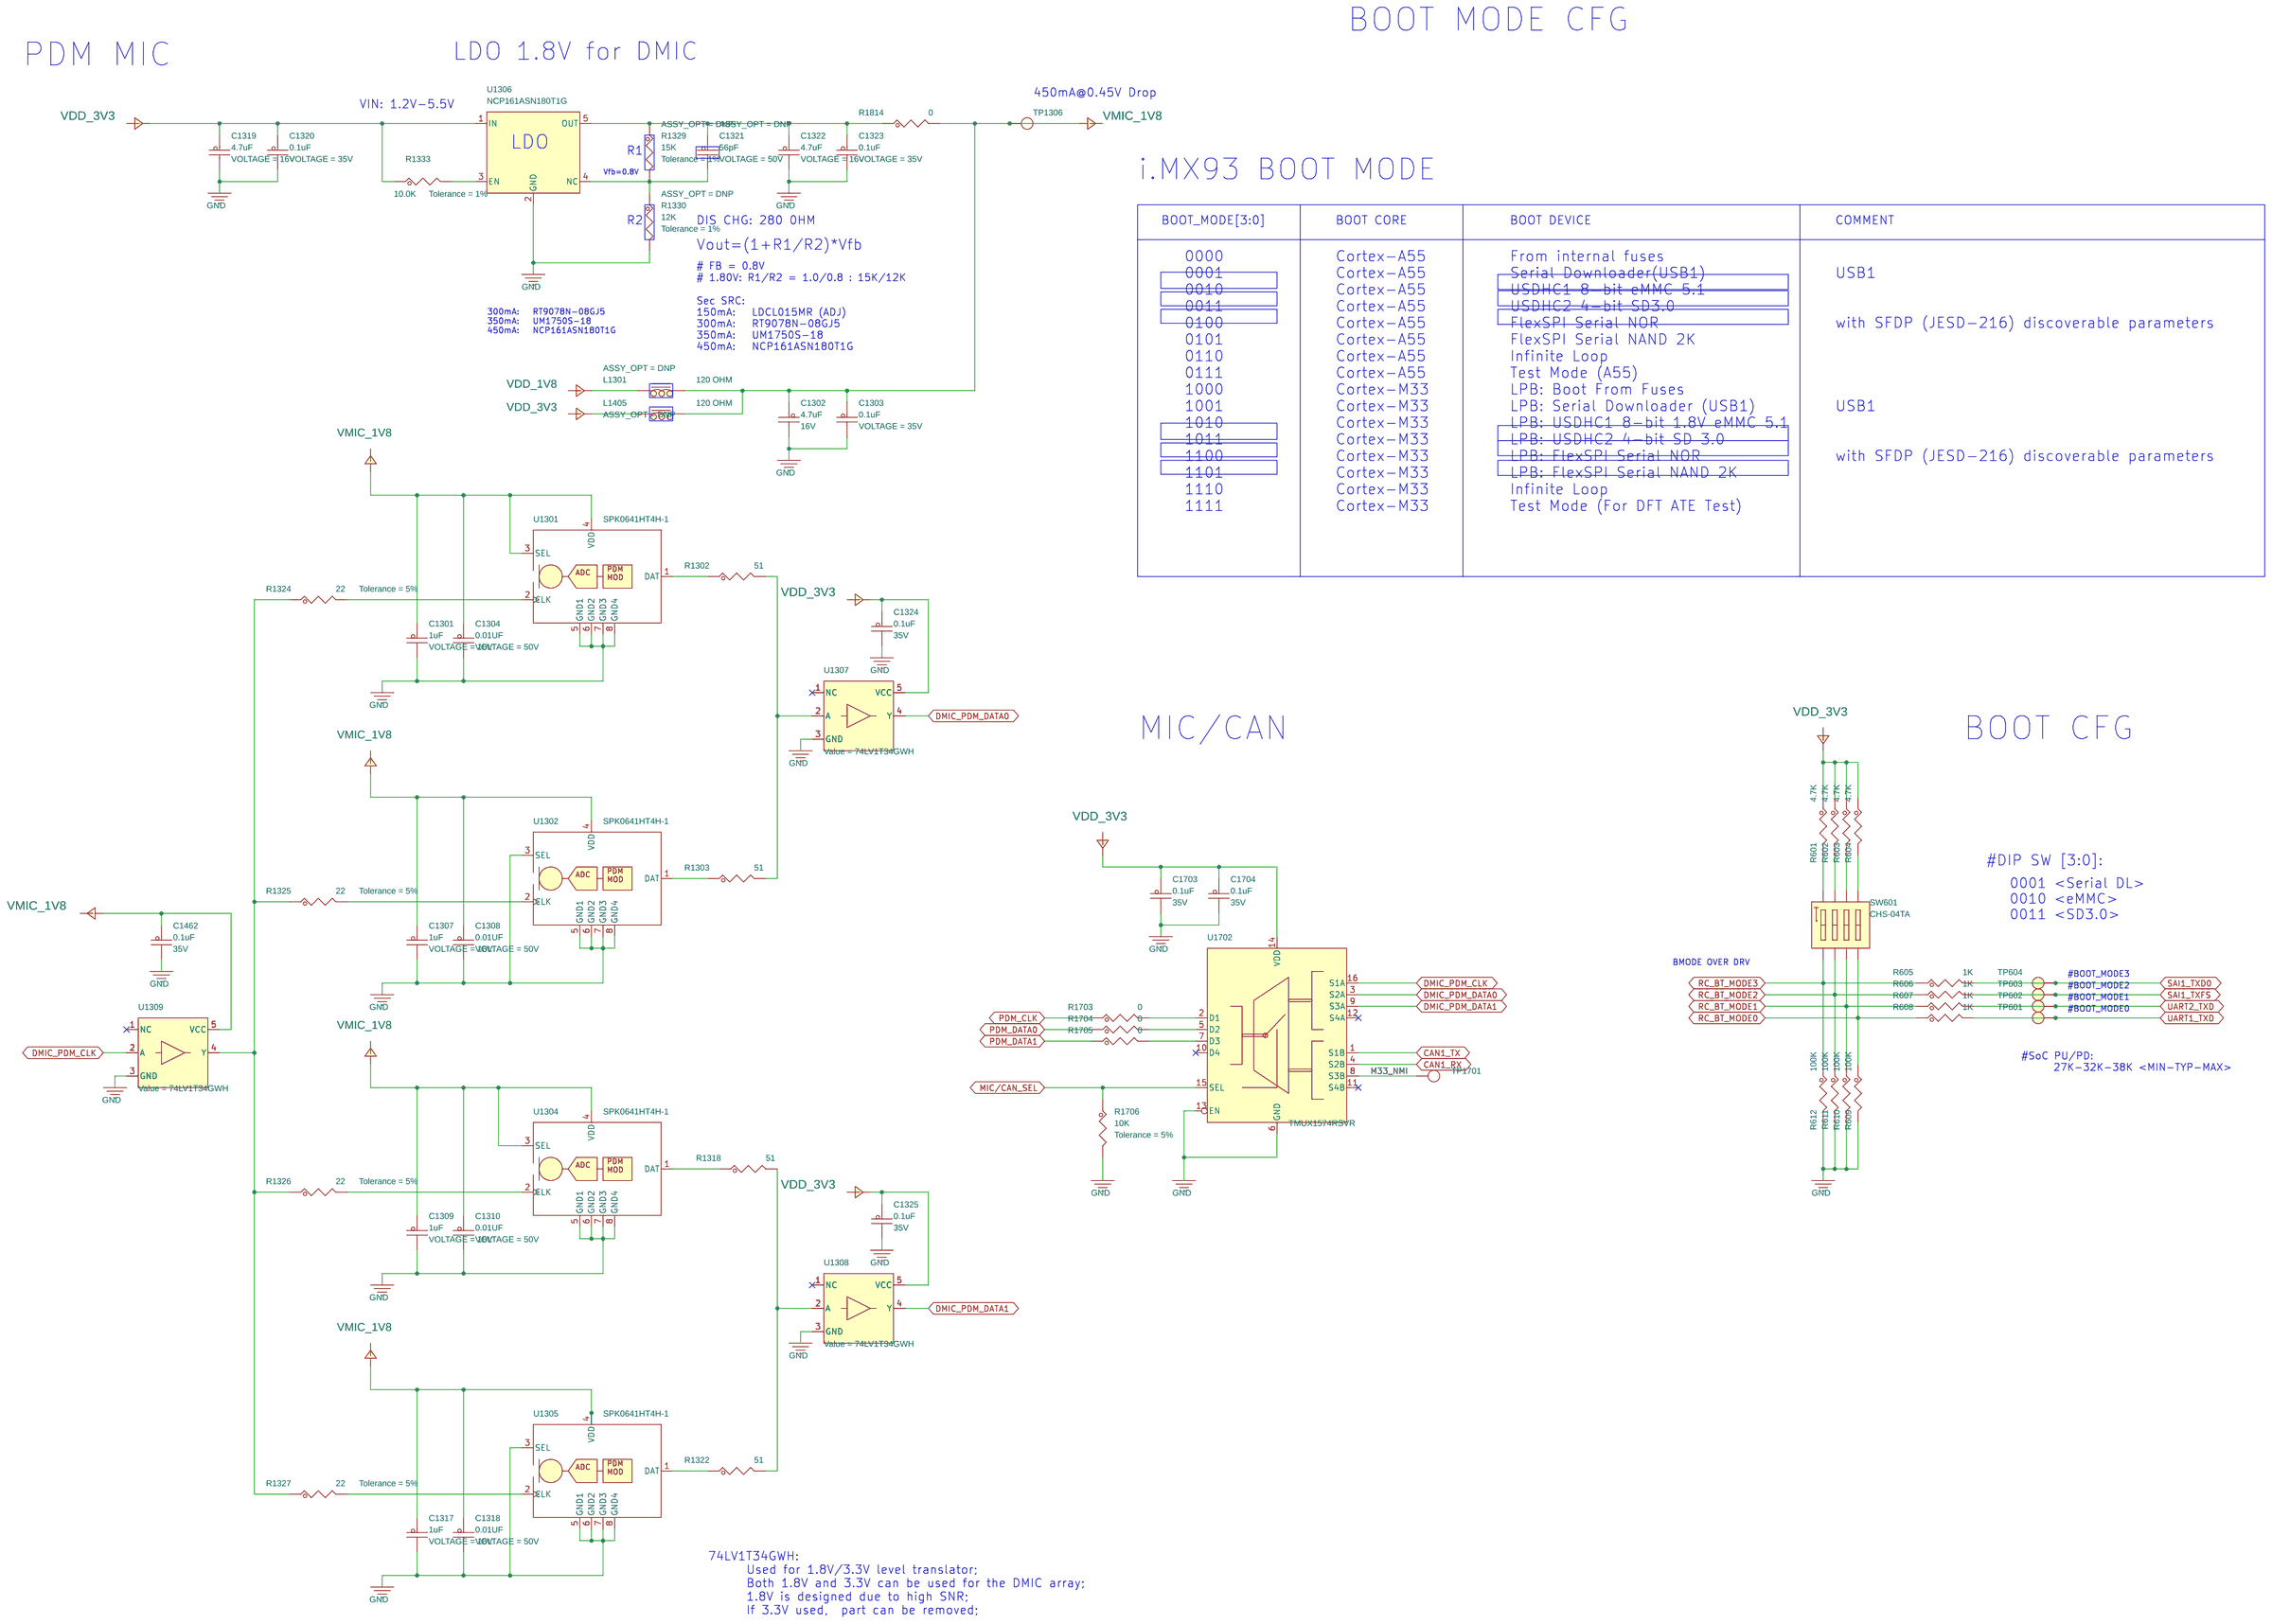
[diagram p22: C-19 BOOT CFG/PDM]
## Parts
sheet C-08 eMMC/MicroSD
C501  4.7uF  [cc0402_tol0p15]
C502  0.22UF  [0201_CC]
C503  0.22UF  [0201_CC]
C504  10uF  [0402_CC]
C505  0.22UF  [0201_CC]
C506  0.22UF  [0201_CC]
C507  0.22UF  [0201_CC]
C508  0.22UF  [0201_CC]
C509  1uF  [0201_CC]
C1019  0.1uF  [CC0402_25]
C1020  22uF  [CC0805_OV]
C1731  47uF  [0805_CC]
C1732  0.1uF  [CC0402_25]
D1003  ESD5B5.0ST1G  [diode2_sod523]
D1004  ESD5B5.0ST1G  [diode2_sod523]
D1005  PESD5V0R1BSF  [dsn0603-2]
D1006  PESD5V0R1BSF  [dsn0603-2]
D1007  PESD5V0R1BSF  [dsn0603-2]
D1008  PESD5V0R1BSF  [dsn0603-2]
D1009  PESD5V0R1BSF  [dsn0603-2]
D1010  PESD5V0R1BSF  [dsn0603-2]
J1002  CONN_SD_CARD 9  [con9_sdcard_1p1mm]
R501  10K  [0402_CC]
R502  10K  [0402_CC]
R1051  0  [0402_CC]
R1052  10K  [0402_CC]
R1053  10K  [0402_CC]
R1054  10K  [0402_CC]
R1055  0  [0603_CC]
R1056  10K  [0402_CC]
R1057  0  [0402_CC]
R1060  0  [0402_CC]
R1061  0  [0402_CC]
R1062  0  [0402_CC]
R1063  0  [0402_CC]
R1064  0  [0402_CC]
R1065  0  [0402_CC]
TP501  TPAD_020  [tpad_020]
TP502  TPAD_020  [tpad_020]
TP503  TPAD_020  [tpad_020]
TP504  TPAD_015  [TPAD_015]
TP505  TPAD_020  [tpad_020]
TP1914  TPAD_050  [TPAD_050]
TP1919  TPAD_050  [TPAD_050]
U501  SDINBDA6-16G-I  [fbga153_0p5_11p5x13]  (sections A,B)
U1707  74LV1T126GVH  [sot753_5p_1p7x3p1mm]
U1708  FPF1504  [wlcsp4_0p5_0p99x0P99]
sheet C-17 CAN/Ext RTC
BT1001  ML414H  [battery_4p8sq_s]
C955  1.0UF  [0402_CC]
C956  0.22UF  [0201_CC]
C1021  0.1uF  [CC0402_25]
C1022  0.1uF  [CC0402_25]
C1023  47uF  [0805_CC]
C1024  0.1uF  [CC0402_25]
C1501  1uF  [CC0402_25]
C1502  0.1uF  [CC0402_25]
C1503  1uF  [CC0402_25]
C1504  56PF  [0402_CC]
C1505  1uF  [CC0402_25]
C1506  0.1uF  [CC0402_25]
C1507  56PF  [0402_CC]
C1508  56PF  [0402_CC]
C1509  56PF  [0402_CC]
D601  LED GREEN  [LED_0603]
D1011  BAT54HT1  [SOD323]
D1012  BAT54HT1  [SOD323]
D1501  LED GREEN  [LED_0603]
D1502  LED_ORANGE  [led_0603_11mil]
D1503  PESD2CANFD24V-T  [sot23_a]
J1501  CON 1X4 PLUG  [con1x4_2mm_th_303h]
L1501  DLW43SH510XK2  [IND_DLW43]
R613  1.0K  [0402_CC]
R861  0  [0402_CC]
R862  0  [0402_CC]
R863  100K  [0402_CC]
R1072  1K  [0402_CC]
R1073  0  [0402_CC]
R1074  0  [0402_CC]
R1075  10K  [0402_CC]
R1076  10K  [0402_CC]
R1077  10K  [0402_CC]
R1078  10K  [0402_CC]
R1079  10K  [0402_CC]
R1080  10K  [0402_CC]
R1081  10K  [0402_CC]
R1082  0  [0402_CC]
R1083  330  [RC0402_25]
R1084  0  [0402_CC]
R1085  0  [0402_CC]
R1501  0  [0402_CC]
R1502  0  [0402_CC]
R1503  0  [0603_CC]
R1504  62.0  [0603_CC]
R1505  2.2K  [0402_CC]
R1506  1K  [0402_CC]
R1507  0  [0402_CC]
R1508  0  [0402_CC]
R1509  0  [0402_CC]
R1510  0  [0402_CC]
R1511  62.0  [0603_CC]
R1512  10K  [0402_CC]
S1501  CHS-01TA1  [sw_2p8x5p7_sm]
TP607  TP_35MIL  [testpoint_35mil]
TP608  TP_35MIL  [testpoint_35mil]
TP609  TP_35MIL  [testpoint_35mil]
TP610  TP_35MIL  [testpoint_35mil]
TP611  TP_35MIL  [testpoint_35mil]
TP612  TP_35MIL  [testpoint_35mil]
TP613  TP_35MIL  [testpoint_35mil]
TP614  TP_35MIL  [testpoint_35mil]
TP615  TP_35MIL  [testpoint_35mil]
TP616  TP_35MIL  [testpoint_35mil]
TP617  TP_35MIL  [testpoint_35mil]
TP1015  TPAD_020  [tpad_020]
TP1016  TPAD_020  [tpad_020]
TP1017  TPAD_020  [tpad_020]
TP1018  TPAD_020  [tpad_020]
TP1019  TPAD_020  [tpad_020]
TP1020  TPAD_020  [tpad_020]
TP1021  TPAD_020  [tpad_020]
TP1954  TP_35MIL  [testpoint_35mil]
U915  P3T1085UK  [wlcsp6_0p4_0p84x1p18]
U1004  PCF2131  [so16_0p5_3p5x4p5_mm]
U1501  TJA1057GT/3  [SO8_1P27_4X5]
sheet C-19 BOOT CFG/PDM
C1301  1uF  [CC0402_25]
C1302  4.7uF  [CC0603_OV]
C1303  0.1uF  [CC0402_25]
C1304  0.01UF  [0402_CC]
C1307  1uF  [CC0402_25]
C1308  0.01UF  [0402_CC]
C1309  1uF  [CC0402_25]
C1310  0.01UF  [0402_CC]
C1317  1uF  [CC0402_25]
C1318  0.01UF  [0402_CC]
C1319  4.7uF  [CC0603_OV]
C1320  0.1uF  [0201_CC]
C1321  56pF  [CC0402_25]
C1322  4.7uF  [CC0603_OV]
C1323  0.1uF  [0201_CC]
C1324  0.1uF  [CC0402_25]
C1325  0.1uF  [CC0402_25]
C1462  0.1uF  [CC0402_25]
C1703  0.1uF  [CC0402_25]
C1704  0.1uF  [CC0402_25]
L1301  120 OHM  [IND_0603]
L1405  120 OHM  [IND_0603]
R601  4.7K  [RC0402_25]
R602  4.7K  [RC0402_25]
R603  4.7K  [RC0402_25]
R604  4.7K  [RC0402_25]
R605  1K  [0402_CC]
R606  1K  [0402_CC]
R607  1K  [0402_CC]
R608  1K  [0402_CC]
R609  100K  [0402_CC]
R610  100K  [0402_CC]
R611  100K  [0402_CC]
R612  100K  [0402_CC]
R1302  51  [0402_CC]
R1303  51  [0402_CC]
R1318  51  [0402_CC]
R1322  51  [0402_CC]
R1324  22  [0402_CC]
R1325  22  [0402_CC]
R1326  22  [0402_CC]
R1327  22  [0402_CC]
R1329  15K  [RC0402_25]
R1330  12K  [RC0402_25]
R1333  10.0K  [0201_CC]
R1703  0  [0402_CC]
R1704  0  [0402_CC]
R1705  0  [0402_CC]
R1706  10K  [0402_CC]
R1814  0  [0402_CC]
SW601  CHS-04TA  [sw_chs_04_a]
TP601  TP_35MIL  [testpoint_35mil]
TP602  TP_35MIL  [testpoint_35mil]
TP603  TP_35MIL  [testpoint_35mil]
TP604  TP_35MIL  [testpoint_35mil]
TP1306  TPAD_020  [tpad_020]
TP1701  TPAD_050  [TPAD_050]
U1301  SPK0641HT4H-1  [lga8_3p1x4p1mm_spk0641]
U1302  SPK0641HT4H-1  [lga8_3p1x4p1mm_spk0641]
U1304  SPK0641HT4H-1  [lga8_3p1x4p1mm_spk0641]
U1305  SPK0641HT4H-1  [lga8_3p1x4p1mm_spk0641]
U1306  NCP161ASN180T1G  [SOT-23-5]
U1307  74LV1T34GWH  [sc70-5]
U1308  74LV1T34GWH  [sc70-5]
U1309  74LV1T34GWH  [sc70-5]
U1702  TMUX1574RSVR  [pqfn16_0p4_2p65x1p85]

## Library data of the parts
C501 = CAP_NP: CAP CER 4.7uF 10V 10% X5R 0402; AGILE_PN: 150-80044; CAD_APPROVED: Yes; FPLIST: cc0402_tol0p15,cc0402_tol0p15_ov,0402_cc_nsp; HEIGHT: 0.65MM; MFG_NAME01: SAMSUNG ELECTRO MECHANICS; MFG_PN01: CL05A475KP5NRNC; ROHS: Yes; Tolerance: 10%; VOLTAGE: 10V
C502 C503 C505-C508 = CAP_NP: CAP CER 0.22UF 10V 20% X5R 0201; AGILE_PN: 150-78815; CAD_APPROVED: Yes; FPLIST: CC0201,CC0201_HD,0201_CC; HEIGHT: 0.33MM; MFG_NAME01: Taiyo Yuden; MFG_PN01: LMK063BJ224MP-F; ROHS: Yes; Tolerance: 20%; VOLTAGE: 10V
C504 = CAP_NP: CAP CER 10UF 6.3V 20% X5R 0402; AGILE_PN: 150-79163; CAD_APPROVED: Yes; FPLIST: CC0402_25,CC0402_HD,0402_CC; HEIGHT: 0.65 MM; MFG_NAME01: SAMSUNG ELECTRO MECHANICS; MFG_PN01: CL05A106MQ5NUNC; ROHS: Yes; Tolerance: 20%; VOLTAGE: 6.3V
C509 = CAP_NP: CAP CER 1.0uF 10V 10% X5R 0201; AGILE_PN: 150-81088; CAD_APPROVED: Yes; FPLIST: CC0201,CC0201_HD,0201_CC,cc_0201_cir; HEIGHT: 0.35MM; MFG_NAME01: SAMSUNG ELECTRO MECHANICS; MFG_PN01: CL03A105KP3NSNC; Package Size: 0201 (0603 Metric); Package Type: SMD/SMT; ROHS: Yes; Temp Range: -55°C to 85°C; Tolerance: 10%; VOLTAGE: 10V
C1019 C1022 C1024 C1303 C1324 C1325 C1462 C1502 C1506 C1703 C1704 C1732 = CAP_NP: CAP CER 0.1UF 35V 10% X5R 0402; AGILE_PN: 150-78506; CAD_APPROVED: Yes; FPLIST: CC0402_25,CC0402_HD,0402_CC,capc0402_l; HEIGHT: 0.55MM; MFG_NAME01: TAIYO YUDEN; MFG_PN01: GMK105BJ104KV-F; ROHS: Yes; Tolerance: 10%; VOLTAGE: 35V
C1020 = CAP_NP: CAP CER 22UF 16V 20% X5R 0805; AGILE_PN: 150-81221; CAD_APPROVED: Yes; FPLIST: CC0805_OV,CC0805,0805_CC; HEIGHT: 1.45MM; MFG_NAME01: TDK Corporation; MFG_PN01: C2012X5R1C226M125AC; ROHS: Yes; Tolerance: 20%; VOLTAGE: 16V
C1023 C1731 = CAP_NP: CAP CER 47uF 10V 20% X5R 0805; AGILE_PN: 150-78979; CAD_APPROVED: Yes; FPLIST: CC0805_OV,CC0805,0805_CC; HEIGHT: 1.45 MM; MFG_NAME01: TDK; MFG_PN01: C2012X5R1A476M125AC; ROHS: Yes; Tolerance: 20%; VOLTAGE: 10V
D1003 D1004 = DIODE_TVS_BIDIR: DIODE SUPPRESSOR 16A@30NS 5V@1UA SOD-523; AGILE_PN: 480-76937; CAD_APPROVED: Yes; HEIGHT: 0.7MM; MFG_NAME01: ON SEMICONDUCTOR
D1005-D1010 = DIODE_BIDIR: DIODE TVS 5VWM 9.2VC DSN0603-2; AGILE_PN: 480-79664; CAD_APPROVED: Yes; HEIGHT: 0.32MM; MFG_NAME01: NEXPERIA; MFG_PN01: PESD5V0R1BSFYL
J1002 = CONN_MICRO_SDCARD: CON 9 SD CARD PUSH SMT 1.1MM SP 81H AU; AGILE_PN: 211-79878; CAD_APPROVED: Yes; HEIGHT: 2.05 MM; MFG_NAME01: SHENZHEN ATOM TECHNOLOGY CO.,LTD; MFG_PN01: MR01A-01202; Package Type: SMT; ROHS: Yes
R501 R502 R1080 R1081 = RES: RES MF 10K 1/16W 5% 0402; AGILE_PN: 470-75557; ASSY_OPT: DNP; CAD_APPROVED: Yes; FPLIST: RC0402_25,RC0402_HD,0402_CC; HEIGHT: 0.4 MM; MFG_NAME01: VISHAY INTERTECHNOLOGY; MFG_PN01: CRCW040210K0JNED; ROHS: Yes; Tolerance: 5%
R1051 R1082 R1085 = RES: RES MF ZERO OHM 1/16W 5% 0402; AGILE_PN: 470-75394; ASSY_OPT: DNP; CAD_APPROVED: Yes; FPLIST: RC0402_25,RC0402_HD,RC0402_X2,0402_CC; HEIGHT: 0.45 MM; MFG_NAME01: YAGEO AMERICA; MFG_PN01: RC0402JR-070RL; ROHS: Yes; Tolerance: 5%; VOLTAGE: 1/16W
R1052-R1054 R1056 R1075-R1079 R1512 R1706 = RES: RES MF 10K 1/16W 5% 0402; AGILE_PN: 470-75557; CAD_APPROVED: Yes; FPLIST: RC0402_25,RC0402_HD,0402_CC; HEIGHT: 0.4 MM; MFG_NAME01: VISHAY INTERTECHNOLOGY; MFG_PN01: CRCW040210K0JNED; ROHS: Yes; Tolerance: 5%
R1055 = RES: RES MF ZERO OHM 1/10W -- 0603; AGILE_PN: 470-80866; ASSY_OPT: DNP; CAD_APPROVED: Yes; FPLIST: RC0603_OV,RC0603,R603-X2,0603_CC,IND_0603HP_NSP,CC0603_OV_NSP; HEIGHT: 0.6MM; MFG_NAME01: WALSIN TECHNOLOGY CORP.; MFG_PN01: WR06X000PTL; ROHS: Yes; Temp Range: –55 °C to +155 °C
R1057 = RES: RES MF ZERO OHM 1/16W 5% 0402; AGILE_PN: 470-75394; CAD_APPROVED: Yes; FPLIST: RC0402_25,RC0402_HD,RC0402_X2,0402_CC; HEIGHT: 0.45 MM; MFG_NAME01: ROHM; MFG_PN01: MCR01MZPJ000; ROHS: Yes; Tolerance: 5%; VOLTAGE: 1/16W
R861 R862 R1060-R1065 R1073 R1074 R1084 R1501 R1502 = RES: RES MF ZERO OHM 1/16W 5% 0402; AGILE_PN: 470-75394; CAD_APPROVED: Yes; FPLIST: RC0402_25,RC0402_HD,RC0402_X2,0402_CC; HEIGHT: 0.45 MM; MFG_NAME01: YAGEO AMERICA; MFG_PN01: RC0402JR-070RL; ROHS: Yes; Tolerance: 5%; VOLTAGE: 1/16W
TP501-TP503 TP505 TP1015-TP1021 TP1306 = TESTLOOP: TEST POINT PAD 0.5MM DIA SMT, NO PART TO ORDER; AGILE_PN: 211-77484; ASSY_OPT: DNP; CAD_APPROVED: Yes; HEIGHT: 0.1MM; ROHS: Yes
TP504 = TESTLOOP: TEST POINT PAD 15MIL DIA SMT, NO PART TO ORDER; AGILE_PN: 211-76645; ASSY_OPT: DNP; CAD_APPROVED: Yes; HEIGHT: 0.1MM; MFG_NAME01: NOTACOMPONENT; MFG_PN01: NOTACOMPONENT; ROHS: Yes
TP1701 TP1914 TP1919 = TESTLOOP: TEST POINT PAD 50MIL DIA SMT, NO PART TO ORDER; AGILE_PN: 211-76644; ASSY_OPT: DNP; CAD_APPROVED: Yes; HEIGHT: 0.1MM; MFG_NAME01: NOTACOMPONENT; MFG_PN01: NOTACOMPONENT; ROHS: Yes
U501 = SDINBDA6_32G_I_VFBGA_153P: IC MEM NAND FLASH 16GB MMC 5.1 CTLR 2.7-3.6V FBGA153; AGILE_PN: 342-00870; CAD_APPROVED: Yes; HEIGHT: 1MM; MFG_NAME01: SANDISK CORPORATION; ROHS: Yes; Temp Range: -25°C to 85°C
U1707 = 74LV1T126GVH: IC VXLTR 1BIT BUF DRV 1.6-5.5V SOT753; 3D_Mechanical_Footprint_File: ftp://fcl.am.freescale.net/ALLEGRO/step/sot753_5p_1p7x3p1mm.STEP; AGILE_PN: 312-83148; CAD_APPROVED: Yes; HEIGHT: 1.1MM; MFG_NAME01: Nexperia; Package Size: SC-74A-5; ROHS: Yes; Temp Range: -40°C to +125°C; VOLTAGE: 1.6-5.5V
U1708 = FPF1504UCX_CSP4_A: IC LOAD SW 15mOHM PMOS 1-3.6V WLCSP4; 3D_Mechanical_Footprint_File: ftp://fcl.am.freescale.net/ALLEGRO/step/wlcsp4_0p5_0p99x0P99.STEP; AGILE_PN: 315-80912; CAD_APPROVED: Yes; HEIGHT: 0.625MM; MFG_NAME01: FAIRCHILD; MFG_PN01: FPF1504UCX; ROHS: Yes; VOLTAGE: 1.0-3.6V
BT1001 = BATTERY: BATTERY LITHIUM -- 3V 1MAH SMD; AGILE_PN: 801-76342; ASSY_OPT: DNP; CAD_APPROVED: Yes; HEIGHT: 1.77mm; MFG_NAME01: SEIKO; MFG_PN01: ML414H  IV01E; ROHS: YES; Temp Range: -20°C to 60°C
C955 = CAP_NP: CAP CER 1.0UF 10V 10% X5R 0402; AGILE_PN: 150-75772; CAD_APPROVED: Yes; FPLIST: CC0402_25,CC0402_HD,0402_CC; HEIGHT: 0.6MM; MFG_NAME01: YAGEO AMERICA; MFG_PN01: CC0402KRX5R6BB105; Package Size: 0402; ROHS: Yes; SIGNAL_MODEL: DEFAULT_CAPACITOR_1e+06pF_2_1; TOL: 10%; VOLTAGE: 10V; voltage rating: 10V
C956 = CAP_NP: CAP CER 0.22UF 10V 20% X5R 0201; AGILE_PN: 150-78815; CAD_APPROVED: Yes; FPLIST: CC0201,CC0201_HD,0201_CC,0201_CC_012SM_NSP; HEIGHT: 0.33MM; MFG_NAME01: Taiyo Yuden; MFG_PN01: LMK063BJ224MP-F; ROHS: Yes; Tolerance: 20%; VOLTAGE: 10V
C1021 = CAP_NP: CAP CER 0.1UF 35V 10% X5R 0402; AGILE_PN: 150-78506; CAD_APPROVED: Yes; EN: 102-1-02300; FPLIST: CC0402_25,CC0402_HD,0402_CC,capc0402_l; HEIGHT: 0.55MM; MFG_NAME01: TAIYO YUDEN; MFG_PN01: GMK105BJ104KV-F; ROHS: Yes; TOL: 10%; Tolerance: 10%; VOLTAGE: 35V
C1501 C1503 C1505 = CAP_NP: CAP CER 1uF 16V 10% X5R 0402; AGILE_PN: 150-78973; CAD_APPROVED: Yes; FPLIST: CC0402_25,CC0402_HD,0402_CC,capc0402_l; HEIGHT: 0.55 MM; MFG_NAME01: YAGEO; MFG_PN01: CC0402KRX5R7BB105; ROHS: Yes; Tolerance: 10%; VOLTAGE: 16V
C1504 C1509 = CAP_NP: CAP CER 56PF 50V 5% C0G 0402; AGILE_PN: 150-30269; CAD_APPROVED: Yes; FPLIST: CC0402_25,CC0402_HD,0402_CC; HEIGHT: 0.55 MM; MFG_NAME01: VENKEL COMPANY; MFG_PN01: C0402C0G500-560JNE; ROHS: Yes; Tolerance: 5%; VOLTAGE: 50V
C1507 C1508 = CAP_NP: CAP CER 56PF 50V 5% C0G 0402; AGILE_PN: 150-30269; CAD_APPROVED: Yes; FPLIST: CC0402_25,CC0402_HD,0402_CC,capc0402_l; HEIGHT: 0.55 MM; MFG_NAME01: VENKEL COMPANY; MFG_PN01: C0402C0G500-560JNE; ROHS: Yes; Tolerance: 5%; VOLTAGE: 50V
D601 D1501 = LED: LED GRN SGL 25MA SMT 0603; AGILE_PN: 370-76672; CAD_APPROVED: Yes; HEIGHT: 0.8 MM; MFG_NAME01: DIALIGHT; MFG_PN01: 598-8070-107F; ROHS: Yes; VOLTAGE: 2V
D1011 D1012 = DIODE: DIODE SCH 30V 200MA -- SOD323; AGILE_PN: 480-30039; CAD_APPROVED: Yes; HEIGHT: 1.15MM; MFG_NAME01: ON SEMICONDUCTOR; MFG_PN01: BAT54HT1G
D1502 = LED: LED OR SGL 20MA 0603; AGILE_PN: 370-76572; CAD_APPROVED: Yes; HEIGHT: 0.28MM; MFG_NAME01: KINGBRIGHT; MFG_PN01: APG1608SEKC/T; ROHS: Yes; Rated Voltage: 2V; Temp Range: -40°C to +85°C; Temp_Range: -40°C to +85°C; VOLTAGE: 2v
D1503 = ESD_DIODE_2LINE: DIODE BIDIR CAN BUS ESD PROTECTION 2.6A 24V AEC-Q101 SOT23; AGILE_PN: 480-80386; HEIGHT: 1.1MM; Package Size: TO-236-3, SC-59, SOT-23-3; Rated Voltage: 24V
J1501 = CONN_HDR_4X1: CON 1X4 SHRD TH 2MM SP 303H SN 126L; 3D_Mechanical_Footprint_File: http://www.hxdy.com/NewProductsLook.asp?id=18; AGILE_PN: 210-82576; CAD_APPROVED: Yes; HEIGHT: 7.7MM; MFG_NAME01: HONGXING ELECTRICAL; MFG_PN01: HX20020-4A; ROHS: Yes; Temp Range: -25 to +85°C
L1501 = DLW43: IND CHK 51uH@1MHZ 230mA -30%/+50% 1812; AGILE_PN: 180-78178; CAD_APPROVED: Yes; HEIGHT: 2.8MM; MFG_NAME01: MURATA; ROHS: Yes
R613 = RES: RES MF 1.0K 1/16W 1% 0402; AGILE_PN: 470-76037; CAD_APPROVED: Yes; FPLIST: RC0402_25,RC0402_HD,RC0402_X2,0402_CC; HEIGHT: 0.4MM; MFG_NAME01: VISHAY; MFG_PN01: CRCW04021K00FKEDC; ROHS: Yes; Tolerance: 1%; VOLTAGE: 1/16W
R609-R612 R863 = RES: RES MF 100K 1/16W 5% 0402; AGILE_PN: 470-75597; CAD_APPROVED: Yes; FPLIST: RC0402_25,RC0402_HD,0402_CC; HEIGHT: 0.40 MM; MFG_NAME01: VENKEL COMPANY; MFG_PN01: CR0402-16W-104JT; ROHS: Yes; Temp Range: -55C to +155C; Tolerance: 5%; VOLTAGE: 50V
R1072 = RES: RES MF 1.0K 1/16W 5% 0402; AGILE_PN: 470-75555; CAD_APPROVED: Yes; FPLIST: RC0402_25,RC0402_HD,RC0402_X2,0402_CC; HEIGHT: 0.41mm; MFG_NAME01: VISHAY INTERTECHNOLOGY; MFG_PN01: CRCW04021K00JNED; RATING: 1/16W; ROHS: Yes; Tolerance: 5%
R1083 = RES: RES MF 330 OHM 1/16W 5% 0402; AGILE_PN: 470-75613; CAD_APPROVED: Yes; FPLIST: RC0402_25,RC0402_HD,0402_CC; HEIGHT: 0.41mm; MFG_NAME01: VISHAY INTERTECHNOLOGY; MFG_PN01: CRCW0402330RJNEA; ROHS: Yes; Tolerance: 5%
R1503 = RES: RES MF ZERO OHM 1/10W -- 0603; AGILE_PN: 470-80866; CAD_APPROVED: Yes; FPLIST: RC0603_OV,RC0603,R603-X2,0603_CC,IND_0603HP_NSP,CC0603_OV_NSP; HEIGHT: 0.6MM; MFG_NAME01: YAGEO AMERICA; MFG_PN01: RC0603FR-070RL; ROHS: Yes; Temp Range: –55 °C to +155 °C
R1504 R1511 = RES: RES MF 62.0 OHM 1/8W 1% AEC-Q200 0603; AGILE_PN: 470-77889; CAD_APPROVED: Yes; FPLIST: RC0603_OV,RC0603,0603_CC; HEIGHT: 0.55MM; MFG_NAME01: KOA SPEER; MFG_PN01: RK73H1JTTD62R0F; ROHS: Yes; Temp Range: -55C to +155C; Tolerance: 1%
R1505 = RES: RES MF 2.2K 1/16W 5% 0402; AGILE_PN: 470-76602; CAD_APPROVED: Yes; FPLIST: RC0402_25,RC0402_HD,0402_CC; HEIGHT: 0.4 MM; MFG_NAME01: YAGEO AMERICA; MFG_PN01: RC0402JR-072K2L; RATING: 1/16W; ROHS: Yes; Tolerance: 5%
R605-R608 R1506 = RES: RES MF 1.0K 1/16W 5% 0402; AGILE_PN: 470-75555; CAD_APPROVED: Yes; FPLIST: RC0402_25,RC0402_HD,RC0402_X2,0402_CC,CAPC0402_L; HEIGHT: 0.41mm; MFG_NAME01: VISHAY INTERTECHNOLOGY; MFG_PN01: CRCW04021K00JNED; RATING: 1/16W; ROHS: Yes; Tolerance: 5%
R1507 R1510 = RES: RES MF ZERO OHM 1/16W 5% 0402; AGILE_PN: 470-75394; ASSY_OPT: DNP; CAD_APPROVED: Yes; FPLIST: RC0402_25,RC0402_HD,RC0402_X2,0402_CC; HEIGHT: 0.45 MM; MFG_NAME01: YAGEO AMERICA; MFG_PN01: RC0402JR-070RL; RATING: 1/16W; ROHS: Yes; Tolerance: 5%; VOLTAGE: 1/16W
R1508 R1509 R1703-R1705 = RES: RES MF ZERO OHM 1/16W 5% 0402; AGILE_PN: 470-75394; CAD_APPROVED: Yes; FPLIST: RC0402_25,RC0402_HD,RC0402_X2,0402_CC; HEIGHT: 0.45 MM; MFG_NAME01: YAGEO AMERICA; MFG_PN01: RC0402JR-070RL; RATING: 1/16W; ROHS: Yes; Tolerance: 5%; VOLTAGE: 1/16W
S1501 = SW-SPST_A: SW DIP 1 POS 0.025A@24VDC SMT; 3D_Mechanical_Footprint_File: ftp://fcl.am.freescale.net/ALLEGRO/step/sw_2p8x5p7_sm.step; AGILE_PN: 510-78408; CAD_APPROVED: Yes; HEIGHT: 2.5MM; MFG_NAME01: Nidec Copal Electronics Corporation; ROHS: Yes; Temp Range: -40C ~ 85C
TP601-TP604 TP607-TP617 TP1954 = T_POINT_R: TEST POINT PAD .035 SMT, no part to order; AGILE_PN: 510-75618; ASSY_OPT: DNP; CAD_APPROVED: Yes; HEIGHT: 0.1MM; ROHS: Yes
U915 = P3T2108_6P: IC DIG TEMP SENSOR 12BIT I3C/I2C 12.5MHz/3.4MHz 1.4-3.6V WLCSP6; AGILE_PN: TMP-CIP-12138; HEIGHT: 0.485MM; MFG_NAME01: NXP SEMICONDUCTORS; MFG_PN01: P3T1085UKZ; PRE_APN: 312-83691; ROHS: Yes; Temp Range: -40°C to +125°C; VOLTAGE: 1.4-3.6V
U1004 = PCF2131_4: IC RTC CALENDAR W/XTAL TCXO 3.3V AEC-Q100 SO16; AGILE_PN: 312-82330; CAD_APPROVED: Yes; HEIGHT: 1.75MM; MFG_NAME01: NXP SEMICONDUCTORS; ROHS: Yes
U1501 = TJA1057GT3_8P: IC XCVR CAN 4.75-5.25V/2.95-5.25V AEC-Q100 SO8; 3D_Mechanical_Footprint_File: ftp://fcl.am.freescale.net/ALLEGRO/step/so8_1p27_4x5.step; AGILE_PN: 312-81479; CAD_APPROVED: Yes; HEIGHT: 1.75MM; MFG_NAME01: NXP SEMICONDUCTORS; ROHS: Yes; VOLTAGE: 4.75-5.25V/2.95-5.25V
C1301 C1307 C1309 C1317 = CAP_NP: CAP CER 1uF 16V 10% X5R 0402; AGILE_PN: 150-78973; CAD_APPROVED: Yes; FPLIST: CC0402_25,CC0402_HD,0402_CC,capc0402_l; HEIGHT: 0.55 MM; MFG_NAME01: YAGEO; MFG_PN01: CC0402KRX5R7BB105; ROHS: Yes; SIGNAL_MODEL: DEFAULT_CAPACITOR_1e+06pF_2_1; Temp_Range: -55°C to +85°C; Tolerance: 10%; VOLTAGE: 16V
C1302 = CAP_NP: CAP CER 4.7uF 16V 10% X5R 0603; AGILE_PN: 150-80061; CAD_APPROVED: Yes; FPLIST: CC0603_OV,CC0603,cc0603_0805_nsp,0603_CC_NSP; HEIGHT: 0.95MM; MFG_NAME01: MURATA; MFG_PN01: GRM188R61C475KE11D; ROHS: Yes; Temp Range: -55°C to + 85°C; VOLTAGE: 16V
C1304 C1308 C1310 C1318 = CAP_NP: CAP CER 0.01UF 50V 10% X7R 0402; AGILE_PN: 150-30114; CAD_APPROVED: Yes; FPLIST: CC0402_25,CC0402_HD,0402_CC; HEIGHT: 0.74 MM; MFG_NAME01: KEMET; MFG_PN01: C0402C103K5RAC; ROHS: Yes; TOL: 10%; Tolerance: 10%; VOLTAGE: 50V
C1319 C1322 = CAP_NP: CAP CER 4.7uF 16V 20% X5R 0603; AGILE_PN: 150-80930; CAD_APPROVED: Yes; FPLIST: CC0603_OV,CC0603,0603_CC_NSP; HEIGHT: 0.55MM; MFG_NAME01: Murata Electronics; MFG_PN01: GRM185R61C475ME11D; Package Size: 0603 (1608 Metric); Package Type: Surface Mount, MLCC; ROHS: Yes; Rated Voltage: 16V; Tolerance: 20%; VOLTAGE: 16V
C1320 C1323 = CAP_NP: CAP CER 0.1uF 35V 10% X5R 0201; AGILE_PN: 150-79857; CAD_APPROVED: Yes; EN: 102-1-02300; FPLIST: CC0201,CC0201_HD,0201_CC,cc_0201_cir; HEIGHT: 0.33MM; MFG_NAME01: MURATA; MFG_PN01: GRM033R6YA104KE14D; Package Size: 0201; Package Type: SMD; ROHS: Yes; TOL: 10%; Tolerance: 10%; VOLTAGE: 35V
C1321 = CAP_NP: CAP CER 56PF 50V 5% C0G 0402; AGILE_PN: 150-80332; ASSY_OPT: DNP; CAD_APPROVED: Yes; FPLIST: CC0402_25,CC0402_HD,0402_CC,capc0402_l; HEIGHT: 0.55MM; MFG_NAME01: KEMET; MFG_PN01: C0402C560J5GAC; Package Size: 0402; ROHS: Yes; Temp Range: -55C to +125C; Tolerance: 5%; VOLTAGE: 50V
L1301 L1405 = BEAD_0: IND FER BEAD 120OHM@100MHZ 2A 25% 0603; AGILE_PN: 180-78419; ASSY_OPT: DNP; CAD_APPROVED: Yes; FPLIST: IND_0603,0603_CC; HEIGHT: 0.95MM; MFG_NAME01: MURATA; MFG_PN01: BLM18PG121SN1D; ROHS: Yes
R601-R604 = RES: RES MF 4.7K 1/16W 5% 0402; AGILE_PN: 470-75626; CAD_APPROVED: Yes; FPLIST: RC0402_25,RC0402_HD,0402_CC,RC0402_X2; HEIGHT: 0.41mm; MFG_NAME01: NIC COMPONENTS CORP; MFG_PN01: NRCL04J472TRF; ROHS: Yes; Tolerance: 5%
R1302 R1303 R1318 R1322 = RES: RES MF 51 OHM 1/16W 5% 0402; AGILE_PN: 470-76089; CAD_APPROVED: Yes; FPLIST: RC0402_25,RC0402_HD,0402_CC; HEIGHT: 0.40 MM; MFG_NAME01: YAGEO AMERICA; MFG_PN01: RC0402JR-0751RL; ROHS: Yes; Tolerance: 5%
R1324-R1327 = RES: RES MF 22 OHM 1/16W 5% 0402; AGILE_PN: 470-75605; CAD_APPROVED: Yes; FPLIST: RC0402_25,RC0402_HD,0402_CC; HEIGHT: 0.4MM; MFG_NAME01: BOURNS; MFG_PN01: CR0402-JW-220GLF; ROHS: Yes; Tolerance: 5%
R1329 = RES: RES MF 15K  1/16W 1% 0402; AGILE_PN: 470-30965; ASSY_OPT: DNP; CAD_APPROVED: Yes; FPLIST: RC0402_25,RC0402_HD,0402_CC; HEIGHT: 0.40 MM; MFG_NAME01: WALSIN TECHNOLOGY CORP.; MFG_PN01: WR04X1502FTL; ROHS: Yes; Tolerance: 1%
R1330 = RES: RES MF 12K 1/10W 1% AEC-Q200 0402; AGILE_PN: 470-30955; ASSY_OPT: DNP; CAD_APPROVED: Yes; FPLIST: RC0402_25,RC0402_HD,0402_CC; HEIGHT: 0.40 MM; MFG_NAME01: KOA SPEER; MFG_PN01: RK73H1ETTP1202F; ROHS: Yes; Temp Range: -55C to +155C; Tolerance: 1%; VOLTAGE: 50V
R1333 = RES: RES MF 10.0K 1/20W 1% 0201; AGILE_PN: 470-77702; CAD_APPROVED: Yes; FPLIST: RC0201,0201_CC; HEIGHT: 0.26MM; MFG_NAME01: PANASONIC; MFG_PN01: ERJ-1GNF1002C; ROHS: Yes; Tolerance: 1%; VOLTAGE: 1/20W
R1814 = RES: RES MF ZERO OHM 1/16W 5% 0402; AGILE_PN: 470-75394; CAD_APPROVED: Yes; FPLIST: RC0402_25,RC0402_HD,RC0402_X2,0402_CC; HEIGHT: 0.45 MM; MFG_NAME01: ROHM; MFG_PN01: MCR01MZPJ000; RATING: 1/16W; ROHS: Yes; Tolerance: 5%; VOLTAGE: 1/16W
SW601 = CHS-04TA_SW: SW SPST SLD WSH 25MA 24V DIP-4 SMT; 3D_Mechanical_Footprint_File: ftp://fcl.am.freescale.net/ALLEGRO/step/sw_chs_04_a.step; AGILE_PN: 510-77691; CAD_APPROVED: Yes; HEIGHT: 2.5MM; MFG_NAME01: NIDEC COPAL ELECTRONICS CORP; ROHS: Yes
U1301 U1302 U1304 U1305 = SPK0641HT4H_8P_A: IC MIC MEMS PDM DIGITAL SISONIC -26DB 1.6-3.6V LGA8; AGILE_PN: 510-78247; MFG_NAME01: KNOWLES ACOUSTICS
U1306 = NCP161ASN180T1G_A: IC VREG LDO FIXED 1.8V 450mA 1.9-5.5V SOT23-5; 3D_Mechanical_Footprint_File: ftp://fcl.am.freescale.net/ALLEGRO/step/sot-23-5.STEP; AGILE_PN: 315-83463; CAD_APPROVED: Yes; HEIGHT: 1.3 MM; MFG_NAME01: ONSEMI; ROHS: Yes; Temp Range: -40°C ~ 125°C (TJ); VOLTAGE: 1.9-5.5V
U1307-U1309 = 74LV1T34GWH_TSSOP6: IC BUF NON-INVERT 1.6-5.5V TSSOP5; 3D_Mechanical_Footprint_File: ftp://fcl.am.freescale.net/ALLEGRO/step/sc70-5.STEP; AGILE_PN: 312-83344; CAD_APPROVED: Yes; HEIGHT: 1.1 MM; MFG_NAME01: Nexperia; Package Size: TSSOP-5; ROHS: Yes; Temp Range: -40  °C - 125 °C
U1702 = TMUX1574RSVR_A: IC MUX SW SPDT 1.8V UQFN16; AGILE_PN: 312-82341; CAD_APPROVED: Yes; HEIGHT: 0.55MM; MFG_NAME01: TEXAS INSTRUMENTS; ROHS: Yes; Temp Range: -40C to +125C; VOLTAGE: 1.5-5.5V

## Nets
GND: BT1001.2(-) C501.2 C502.2 C503.2 C504.2 C505.2 C506.2 C507.2 C508.2 C509.2 C955.2 C956.2 C1019.2 C1020.2 C1021.2 C1022.2 C1023.2 C1024.2 C1301.2 C1302.2 C1303.2 C1304.2 C1307.2 C1308.2 C1309.2 C1310.2 C1317.2 C1318.2 C1319.2 C1320.2 C1322.2 C1323.2 C1324.2 C1325.2 C1462.2 C1501.2 C1502.2 C1503.2 C1504.1 C1505.2 C1506.2 C1507.2 C1508.2 C1509.2 C1703.2 C1704.2 C1731.2 C1732.2 D601.C(CATHODE) D1003.2(A2) D1004.2(A2) D1005.2(C2) D1006.2(C2) D1007.2(C2) D1008.2(C2) D1009.2(C2) D1010.2(C2) D1503.3(COM_CATHODE) J1002.6(VSS) J1002.10(GND1) J1002.11(GND2) J1002.12(GND3) J1002.13(GND4) J1501.4 R609.2 R610.2 R611.2 R612.2 R1078.1 R1079.1 R1330.2 R1706.2 TP615.1(TP) TP617.1(TP) U501.A6(VSS1) U501.C4(VSSQ1) U501.E7(VSS2) U501.G5(VSS3) U501.H10(VSS4) U501.J5(VSS5) U501.K8(VSS6) U501.N2(VSSQ2) U501.N5(VSSQ3) U501.P4(VSSQ4) U501.P6(VSSQ5) U915.A2(GND) U915.B1(A0) U1004.7(VSS) U1004.17(GND) U1301.5(GND1) U1301.6(GND2) U1301.7(GND3) U1301.8(GND4) U1302.3(SEL) U1302.5(GND1) U1302.6(GND2) U1302.7(GND3) U1302.8(GND4) U1304.5(GND1) U1304.6(GND2) U1304.7(GND3) U1304.8(GND4) U1305.3(SEL) U1305.5(GND1) U1305.6(GND2) U1305.7(GND3) U1305.8(GND4) U1306.2(GND) U1307.3(GND) U1308.3(GND) U1309.3(GND) U1501.2(GND) U1702.6(GND) U1702.13(EN) U1707.3(GND) U1708.B1(GND) ; also on sheet 1 4 5 6 7 8 9 10 11 12 16 17 18 19 20
VCC_FT_3V3: R1053.1 R1056.1 ; also on sheet 5
VDD_1V8: C504.1 C505.1 C506.1 C507.1 L1301.1 R501.1 R502.1 U501.C6(VCCQ1) U501.M4(VCCQ2) U501.N4(VCCQ3) U501.P3(VCCQ4) U501.P5(VCCQ5) ; also on sheet 5 6 7 8 9 12 16 17 18 19
VDD_3V3: C501.1 C502.1 C503.1 C955.1 C956.1 C1319.1 C1320.1 C1324.1 C1325.1 C1703.1 C1704.1 D1501.A(ANODE) D1502.A(ANODE) L1405.1 R601.1 R602.1 R603.1 R604.1 R613.1 R863.1 R1054.1 R1075.1 R1076.1 R1080.1 R1081.1 R1333.1 R1502.1 TP608.1(TP) U501.E6(VCC1) U501.F5(VCC2) U501.J10(VCC3) U501.K9(VCC4) U915.A1(VCC) U1306.1(IN) U1307.5(VCC) U1308.5(VCC) U1702.14(VDD) ; also on sheet 5 6 7 8 9 10 11 12 16 17 19 20
VDD_5V: R1501.2 R1503.2 ; also on sheet 6 9 10 11 19
VDD_COIN_3V: BT1001.1(+) R1072.2 R1082.1
CAN1_RX: R1509.1 U1702.4(S2B)
CAN1_TX: R1508.1 U1702.1(S1B)
CAN_H: C1504.2 D1503.1(CATHODE1) J1501.2 L1501.2 R1504.2 R1507.2
CAN_L: C1509.1 D1503.2(CATHODE2) J1501.3 L1501.3 R1510.2 R1511.1
CAN_RX: R1505.2 R1509.2 U1501.4(RXD)
CAN_STBY: R1512.2 U1501.8(S) ; also on sheet 12
CAN_TX: R1506.2 R1508.2 U1501.1(TXD)
CAN_VDD_5V: C1501.1 C1502.1 R1501.1 U1501.3(VCC)
CAN_VIO_3V3: C1503.1 R1502.2 R1512.1 U1501.5(VIO)
CANH: L1501.1 R1507.1 U1501.7(CANH)
CANL: L1501.4 R1510.1 U1501.6(CANL)
DMIC_PDM_CLK: U1309.2(A) U1702.16(S1A)
DMIC_PDM_DATA0: U1307.4(Y) U1702.3(S2A)
DMIC_PDM_DATA1: U1308.4(Y) U1702.9(S3A)
eMMC_VDDIM: C508.1 C509.1 U501.C2(VDDI)
FT_SD_CD: R1053.2 U1707.1(OE) ; also on sheet 5
FT_SD_PWREN: R1056.2 R1057.1 ; also on sheet 5
I3C1_SCL: R861.1 ; also on sheet 19 20
I3C1_SDA: R862.1 ; also on sheet 19 20
M33_NMI: TP1701.1(Pin1) U1702.8(S3B)
MIC/CAN_SEL: R1706.1 U1702.15(SEL) ; also on sheet 12
NVCC_SD2: C1019.1 R1052.1 U1707.5(VCC) ; also on sheet 16 17 20
PDM_CLK: R1703.1 ; also on sheet 20
PDM_DATA0: R1704.1 ; also on sheet 20
PDM_DATA1: R1705.1 ; also on sheet 20
RC_BT_MODE0: R608.1 R609.1 SW601.7 ; also on sheet 5
RC_BT_MODE1: R607.1 R610.1 SW601.5 ; also on sheet 5
RC_BT_MODE2: R606.1 R611.1 SW601.3 ; also on sheet 5
RC_BT_MODE3: R605.1 R612.1 SW601.1 ; also on sheet 5
RTC_CLKO: TP1021.1(Pin1) U1004.6(CLKOUT) ; also on sheet 7
RTC_nINTA: R1075.2 R1084.1 TP1019.1(Pin1) U1004.13(~{INTA}) ; also on sheet 12
SAI1_TXD0: R605.2 TP604.1(TP) ; also on sheet 7 20
SAI1_TXFS: R606.2 TP603.1(TP) ; also on sheet 7 20
SD1_CLK: TP503.1(Pin1) U501.M6(CLK) ; also on sheet 20
SD1_CMD: R502.2 TP502.1(Pin1) U501.M5(CMD) ; also on sheet 20
SD1_DATA0: R501.2 TP501.1(Pin1) U501.A3(DAT0) ; also on sheet 20
SD1_DATA1: U501.A4(DAT1) ; also on sheet 20
SD1_DATA2: U501.A5(DAT2) ; also on sheet 20
SD1_DATA3: U501.B2(DAT3) ; also on sheet 20
SD1_DATA4: U501.B3(DAT4) ; also on sheet 20
SD1_DATA5: U501.B4(DAT5) ; also on sheet 20
SD1_DATA6: U501.B5(DAT6) ; also on sheet 20
SD1_DATA7: U501.B6(DAT7) ; also on sheet 20
SD1_STROBE: TP505.1(Pin1) U501.H5(RCLK) ; also on sheet 20
SD2_CLK: R1061.1 ; also on sheet 20
SD2_CMD: R1060.1 ; also on sheet 20
SD2_DATA0: R1062.1 ; also on sheet 20
SD2_DATA1: R1063.1 ; also on sheet 20
SD2_DATA2: R1064.1 ; also on sheet 20
SD2_DATA3: R1065.1 ; also on sheet 20
SD2_nCD: R1051.1 R1052.2 U1707.4(Y) ; also on sheet 20
SD2_nDET: D1004.1(A1) J1002.9(DET) R1051.2 R1054.2 TP1914.1(Pin1) U1707.2(A)
SD_CLK: D1006.1(C1) J1002.5(CLK) R1061.2
SD_CMD: D1005.1(C1) J1002.3(CMD) R1060.2
SD_DATA0: D1007.1(C1) J1002.7(DAT0) R1062.2
SD_DATA1: D1008.1(C1) J1002.8(DAT1) R1063.2
SD_DATA2: D1009.1(C1) J1002.1(DAT2) R1064.2
SD_DATA3: D1010.1(C1) J1002.2(CD/DAT3) R1065.2
SYS_nRST: R1085.2 ; also on sheet 5 17 19
TEMP_SCL: R861.2 U915.B2(SCL)
TEMP_SDA: R862.2 U915.C2(SDA)
UART1_RXD: TP612.1(TP) ; also on sheet 5 20
UART1_TXD: R608.2 TP601.1(TP) TP610.1(TP) ; also on sheet 5 20
UART2_RXD: TP616.1(TP) ; also on sheet 5 20
UART2_TXD: R607.2 TP602.1(TP) TP614.1(TP) ; also on sheet 5 20
USB1_DN: TP611.1(TP) ; also on sheet 9 20
USB1_DP: TP613.1(TP) ; also on sheet 9 20
USB_I2C_SCL: R1073.1 ; also on sheet 9 10
USB_I2C_SDA: R1074.1 ; also on sheet 9 10
USBC_VBUS: TP609.1(TP) ; also on sheet 9
VBBS: C1021.1 U1004.14(BBS)
VCAN_5V: C1505.1 C1506.1 J1501.1 R1503.1
VLDO_3V3: D1011.A(ANODE) D1012.A(ANODE) R1077.1 ; also on sheet 9 10
VMIC_1V8: C1301.1 C1302.1 C1303.1 C1304.1 C1307.1 C1308.1 C1309.1 C1310.1 C1317.1 C1318.1 C1462.1 L1301.2 L1405.2 R1814.2 TP1306.1(Pin1) U1301.3(SEL) U1301.4(VDD) U1302.4(VDD) U1304.3(SEL) U1304.4(VDD) U1305.4(VDD) U1309.5(VCC)
VSD2_3V3: C1731.1 C1732.1 D1003.1(A1) J1002.4(VDD) R1055.2 TP1919.1(Pin1) U1708.A1(VOUT)
VSD_3V3: C1020.1 R1055.1 U1708.A2(VIN) ; also on sheet 17
VSYS_5V: TP607.1(TP) ; also on sheet 7 9 11 17
N111682856: C1507.1 R1504.1 S1501.2(COMMON)
N111682880: D1501.C(CATHODE) R1505.1
N111682886: D1502.C(CATHODE) R1506.1
N111683153: C1508.1 R1511.2 S1501.1(NC)
N114502549: R1703.2 U1702.2(D1)
N114502556: R1704.2 U1702.5(D2)
N114502597: R1705.2 U1702.7(D3)
N115688375: R1057.2 U1708.B2(ON)
N115782425: C1321.1 C1322.1 C1323.1 R1329.1 R1814.1 U1306.5(OUT)
N115782532: C1321.2 R1329.2 R1330.1 U1306.4(NC)
N115782544: R1333.2 U1306.3(EN)
N115782790: R1302.1 U1301.1(DAT)
N115782792: R1302.2 R1303.2 U1307.2(A)
N115782811: R1324.1 R1325.1 R1326.1 R1327.1 U1309.4(Y)
N115782815: R1324.2 U1301.2(CLK)
N115783013: R1303.1 U1302.1(DAT)
N115783041: R1325.2 U1302.2(CLK)
N115783217: R1318.1 U1304.1(DAT)
N115783219: R1318.2 R1322.2 U1308.2(A)
N115783240: R1326.2 U1304.2(CLK)
N115783428: R1322.1 U1305.1(DAT)
N115783445: R1327.2 U1305.2(CLK)
N115785368: R601.2 SW601.2
N115785370: R602.2 SW601.4
N115785372: R603.2 SW601.6
N115785374: R604.2 SW601.8
N115788648: D601.A(ANODE) R613.2
N115837191: TP504.1(Pin1) U501.K5(~{RST})
N116167004: C1023.1 C1024.1 R1083.2 U1004.15(VDD)
N116167167: D1012.C(CATHODE) R1072.1
N116167227: C1022.1 R1082.2 U1004.16(VBAT)
N116167406: R1077.2 U1004.1(IFS)
N116167434: R1073.2 R1080.2 U1004.2(SCL)
N116167436: R1074.2 R1081.2 U1004.5(SDA/~{CE})
N116167463: R1076.2 R1084.2 R1085.1 TP1020.1(Pin1) U1004.12(~{INTB})
N116167513: R1078.2 U1004.3(SDI)
N116167550: R1079.2 U1004.4(SDO)
N116167586: TP1015.1(Pin1) U1004.8(~{TS1})
N116167598: TP1016.1(Pin1) U1004.9(~{TS2})
N116167606: TP1017.1(Pin1) U1004.10(~{TS3})
N116167616: TP1018.1(Pin1) U1004.11(~{TS4})
N116260997: R863.2 TP1954.1(TP) U915.C1(~{ALERT})
N116323997: D1011.C(CATHODE) R1083.1

Not connected (* = marked no-connect by the designer): U501 A1(NC)* A2(NC)* A7(NC)* A8(NC)* A9(NC)* A10(NC)* A11(NC)* A12(NC)* A13(NC)* A14(NC)* B1(NC)* B7(NC)* B8(NC)* B9(NC)* B10(NC)* B11(NC)* B12(NC)* B13(NC)* B14(NC)* C1(NC)* C3(NC)* C5(NC)* C7(NC)* C8(NC)* C9(NC)* C10(NC)* C11(NC)* C12(NC)* C13(NC)* C14(NC)* D1(NC)* D2(NC)* D3(NC)* D4(NC)* D12(NC)* D13(NC)* D14(NC)* E1(NC)* E2(NC)* E3(NC)* E5(NC)* E8(NC)* E9(VSF1)* E10(VSF2)* E12(NC)* E13(NC)* E14(NC)* F1(NC)* F2(NC)* F3(NC)* F10(VSF3)* F12(NC)* F13(NC)* F14(NC)* G1(NC)* G2(NC)* G3(NC)* G10(NC)* G12(NC)* G13(NC)* G14(NC)* H1(NC)* H2(NC)* H3(NC)* H12(NC)* H13(NC)* H14(NC)* J1(NC)* J2(NC)* J3(NC)* J12(NC)* J13(NC)* J14(NC)* K1(NC)* K2(NC)* K3(NC)* K6(NC)* K7(NC)* K10(VSF4)* K12(NC)* K13(NC)* K14(NC)* L1(NC)* L2(NC)* L3(NC)* L12(NC)* L13(NC)* L14(NC)* M1(NC)* M2(NC)* M3(NC)* M7(NC)* M8(NC)* M9(NC)* M10(NC)* M11(NC)* M12(NC)* M13(NC)* M14(NC)* N1(NC)* N3(NC)* N6(NC)* N7(NC)* N8(NC)* N9(NC)* N10(NC)* N11(NC)* N12(NC)* N13(NC)* N14(NC)* P1(NC)* P2(NC)* P7(NC)* P8(NC)* P9(NC)* P10(NC)* P11(NC)* P12(NC)* P13(NC)* P14(NC)*; U1307 1(NC)*; U1308 1(NC)*; U1309 1(NC)*; U1702 10(D4)* 11(S4B)* 12(S4A)*

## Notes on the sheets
sheet 21
- FLASH: eMMC <5.1>
- 16GB <2D MLC eMMC>
- NOTE:
- All the CAPs in this page need to be put on the bottom of BGA,
  and close the PINs as short as possible.
- OE
- A
- Y
- NOTE
- H
- H
- H
- Normal Operation, No card detected
- H
- L
- H
- L
- H
- L
- Normal Operation, card insert
- Simulation, card plug-out
- L
- L
- H
- No card at slot
- MicroSD 3.0
- Only used for SD card Plug-in/out Simulation, Remove this
  circuits and install R1051/R1055 if test not required.
- 74LV1T126GVH is level translating buffer/line driver
  with 3-state output
- # Push-Push
sheet 22
- CAN BUS
- Standby: 5 uA
- Split termination for RC tee filter
- fc=1/[2*pie*(Rt/2)*Csplit]
- TDK:B82793S0513N201
  ACT45B-510-2P-TL003
- Z:120 OHM
- # Compatible : TJA1051T/3
- RSUP and CSUP: An appropriate RC filter needs to be
  added to guarantee the chip will only see <0.35 V/ms ramp
  down rate on supply, even if Vdd_in ramp rate is very high.
- RSUP
- CSUP
- #Coin Cell charge circuits, ONLY
  DESIGNED FOR RECHARGEABLE
  COINE CELL BATTERY!!!.
- I3C TEMP SENSOR
- 1.0mAh (3.1V ～2.0V)
  DSC 0.005mA
- Ext. RTC
- # If RTC kept during system OFF,
  Coin Cell BT1001 and R1082 need to be installed
- OD
- #I2C ADDR: 0b'1001000x
- #I2C ADDR: 0b'1010011x
- #A55 DBG
- #M33 DBG
- # USB Serial Download
sheet 23
- BOOT MODE CFG
- PDM MIC
- LDO 1.8V for DMIC
- VIN: 1.2V-5.5V
- 450mA@0.45V Drop
- LDO
- R1
- Vfb=0.8V
- i.MX93 BOOT MODE
- R2
- DIS CHG: 280 0HM
- BOOT_MODE[3:0]
- BOOT CORE
- BOOT DEVICE
- COMMENT
- Vout=(1+R1/R2)*Vfb
- 0000
  0001
  0010
  0011
  0100
  0101
  0110
  0111
  1000
  1001
  1010
  1011
  1100
  1101
  1110
  1111
- Cortex-A55
  Cortex-A55
  Cortex-A55
  Cortex-A55
  Cortex-A55
  Cortex-A55
  Cortex-A55
  Cortex-A55
  Cortex-M33
  Cortex-M33
  Cortex-M33
  Cortex-M33
  Cortex-M33
  Cortex-M33
  Cortex-M33
  Cortex-M33
- From internal fuses
  Serial Downloader(USB1)
  USDHC1 8-bit eMMC 5.1
  USDHC2 4-bit SD3.0
  FlexSPI Serial NOR
  FlexSPI Serial NAND 2K
  Infinite Loop
  Test Mode (A55)
  LPB: Boot From Fuses
  LPB: Serial Downloader (USB1)
  LPB: USDHC1 8-bit 1.8V eMMC 5.1
  LPB: USDHC2 4-bit SD 3.0
  LPB: FlexSPI Serial NOR
  LPB: FlexSPI Serial NAND 2K
  Infinite Loop
  Test Mode (For DFT ATE Test)
- USB1
  with SFDP (JESD-216) discoverable parameters
  USB1
  with SFDP (JESD-216) discoverable parameters
- # FB = 0.8V
- # 1.80V: R1/R2 = 1.0/0.8 : 15K/12K
- Sec SRC:
  150mA:   LDCL015MR (ADJ)
  300mA:   RT9078N-08GJ5
  350mA:   UM1750S-18
  450mA:   NCP161ASN180T1G
- 300mA:   RT9078N-08GJ5
  350mA:   UM1750S-18
  450mA:   NCP161ASN180T1G
- MIC/CAN
- BOOT CFG
- #DIP SW [3:0]:
- 0001 <Serial DL>
  0010 <eMMC>
  0011 <SD3.0>
- BMODE OVER DRV
- #BOOT_MODE3
- #BOOT_MODE2
- #BOOT_MODE0
- #BOOT_MODE1
- #SoC PU/PD:
        27K-32K-38K <MIN-TYP-MAX>
- 74LV1T34GWH:
        Used for 1.8V/3.3V level translator;
        Both 1.8V and 3.3V can be used for the DMIC array;
        1.8V is designed due to high SNR;
        If 3.3V used,  part can be removed;
